VERSION 5.8 ;
BUSBITCHARS "[]" ;
DIVIDERCHAR "/" ;
UNITS
    DATABASE MICRONS 1000 ;
END UNITS

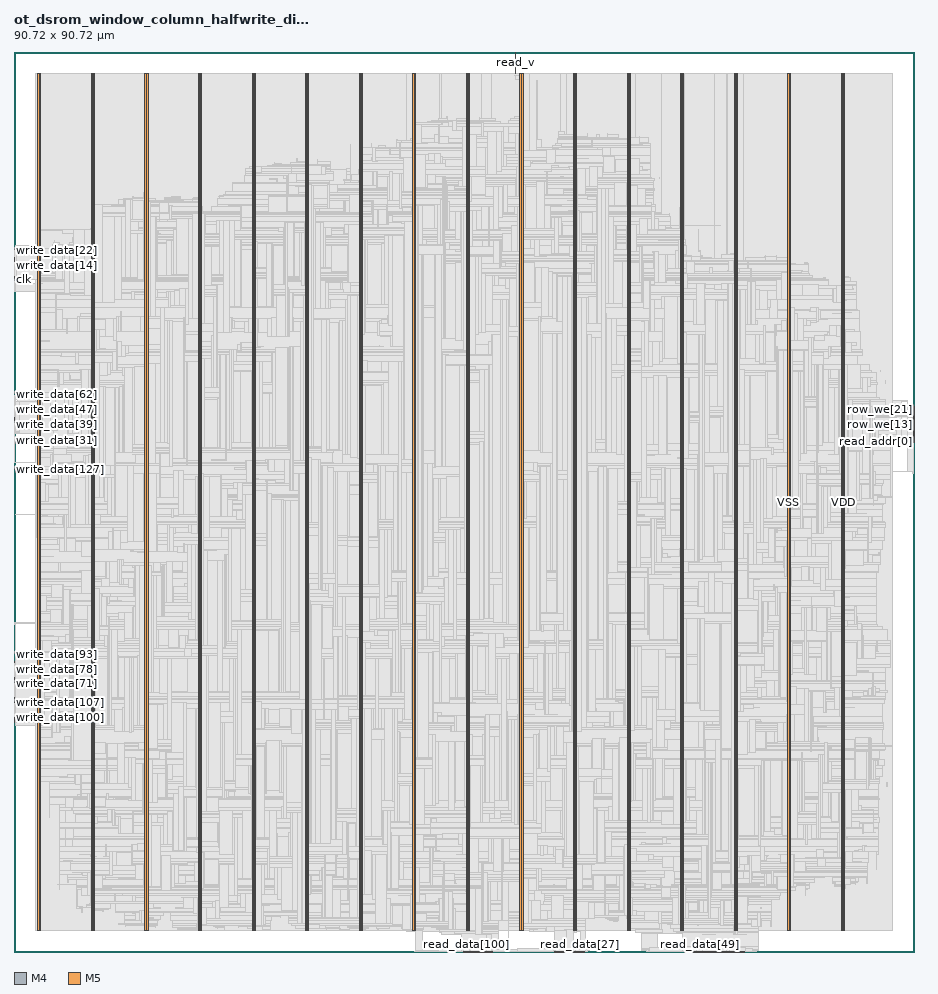
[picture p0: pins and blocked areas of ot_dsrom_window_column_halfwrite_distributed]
MACRO ot_dsrom_window_column_halfwrite_distributed
  FOREIGN ot_dsrom_window_column_halfwrite_distributed 0 0 ;
  CLASS BLOCK ;
  SIZE 90.72 BY 90.72 ;
  PIN clk
    DIRECTION INPUT ;
    USE SIGNAL ;
    PORT
      LAYER M4 ;
        RECT  0 67.728 0.084 67.752 ;
    END
  END clk
  PIN read_addr[0]
    DIRECTION INPUT ;
    USE SIGNAL ;
    PORT
      LAYER M4 ;
        RECT  90.636 51.408 90.72 51.432 ;
    END
  END read_addr[0]
  PIN read_addr[1]
    DIRECTION INPUT ;
    USE SIGNAL ;
    PORT
      LAYER M4 ;
        RECT  90.636 51.504 90.72 51.528 ;
    END
  END read_addr[1]
  PIN read_addr[2]
    DIRECTION INPUT ;
    USE SIGNAL ;
    PORT
      LAYER M4 ;
        RECT  90.636 51.6 90.72 51.624 ;
    END
  END read_addr[2]
  PIN read_addr[3]
    DIRECTION INPUT ;
    USE SIGNAL ;
    PORT
      LAYER M4 ;
        RECT  90.636 51.696 90.72 51.72 ;
    END
  END read_addr[3]
  PIN read_addr[4]
    DIRECTION INPUT ;
    USE SIGNAL ;
    PORT
      LAYER M4 ;
        RECT  90.636 51.792 90.72 51.816 ;
    END
  END read_addr[4]
  PIN read_data[0]
    DIRECTION OUTPUT ;
    USE SIGNAL ;
    PORT
      LAYER M5 ;
        RECT  54.48 0 54.504 0.084 ;
    END
  END read_data[0]
  PIN read_data[100]
    DIRECTION OUTPUT ;
    USE SIGNAL ;
    PORT
      LAYER M5 ;
        RECT  45.648 0 45.672 0.084 ;
    END
  END read_data[100]
  PIN read_data[101]
    DIRECTION OUTPUT ;
    USE SIGNAL ;
    PORT
      LAYER M5 ;
        RECT  45.744 0 45.768 0.084 ;
    END
  END read_data[101]
  PIN read_data[102]
    DIRECTION OUTPUT ;
    USE SIGNAL ;
    PORT
      LAYER M5 ;
        RECT  45.84 0 45.864 0.084 ;
    END
  END read_data[102]
  PIN read_data[103]
    DIRECTION OUTPUT ;
    USE SIGNAL ;
    PORT
      LAYER M5 ;
        RECT  45.936 0 45.96 0.084 ;
    END
  END read_data[103]
  PIN read_data[104]
    DIRECTION OUTPUT ;
    USE SIGNAL ;
    PORT
      LAYER M5 ;
        RECT  46.032 0 46.056 0.084 ;
    END
  END read_data[104]
  PIN read_data[105]
    DIRECTION OUTPUT ;
    USE SIGNAL ;
    PORT
      LAYER M5 ;
        RECT  46.128 0 46.152 0.084 ;
    END
  END read_data[105]
  PIN read_data[106]
    DIRECTION OUTPUT ;
    USE SIGNAL ;
    PORT
      LAYER M5 ;
        RECT  46.224 0 46.248 0.084 ;
    END
  END read_data[106]
  PIN read_data[107]
    DIRECTION OUTPUT ;
    USE SIGNAL ;
    PORT
      LAYER M5 ;
        RECT  46.32 0 46.344 0.084 ;
    END
  END read_data[107]
  PIN read_data[108]
    DIRECTION OUTPUT ;
    USE SIGNAL ;
    PORT
      LAYER M5 ;
        RECT  46.416 0 46.44 0.084 ;
    END
  END read_data[108]
  PIN read_data[109]
    DIRECTION OUTPUT ;
    USE SIGNAL ;
    PORT
      LAYER M5 ;
        RECT  46.512 0 46.536 0.084 ;
    END
  END read_data[109]
  PIN read_data[10]
    DIRECTION OUTPUT ;
    USE SIGNAL ;
    PORT
      LAYER M5 ;
        RECT  55.44 0 55.464 0.084 ;
    END
  END read_data[10]
  PIN read_data[110]
    DIRECTION OUTPUT ;
    USE SIGNAL ;
    PORT
      LAYER M5 ;
        RECT  46.608 0 46.632 0.084 ;
    END
  END read_data[110]
  PIN read_data[111]
    DIRECTION OUTPUT ;
    USE SIGNAL ;
    PORT
      LAYER M5 ;
        RECT  46.704 0 46.728 0.084 ;
    END
  END read_data[111]
  PIN read_data[112]
    DIRECTION OUTPUT ;
    USE SIGNAL ;
    PORT
      LAYER M5 ;
        RECT  46.8 0 46.824 0.084 ;
    END
  END read_data[112]
  PIN read_data[113]
    DIRECTION OUTPUT ;
    USE SIGNAL ;
    PORT
      LAYER M5 ;
        RECT  46.896 0 46.92 0.084 ;
    END
  END read_data[113]
  PIN read_data[114]
    DIRECTION OUTPUT ;
    USE SIGNAL ;
    PORT
      LAYER M5 ;
        RECT  46.992 0 47.016 0.084 ;
    END
  END read_data[114]
  PIN read_data[115]
    DIRECTION OUTPUT ;
    USE SIGNAL ;
    PORT
      LAYER M5 ;
        RECT  47.088 0 47.112 0.084 ;
    END
  END read_data[115]
  PIN read_data[116]
    DIRECTION OUTPUT ;
    USE SIGNAL ;
    PORT
      LAYER M5 ;
        RECT  47.184 0 47.208 0.084 ;
    END
  END read_data[116]
  PIN read_data[117]
    DIRECTION OUTPUT ;
    USE SIGNAL ;
    PORT
      LAYER M5 ;
        RECT  47.28 0 47.304 0.084 ;
    END
  END read_data[117]
  PIN read_data[118]
    DIRECTION OUTPUT ;
    USE SIGNAL ;
    PORT
      LAYER M5 ;
        RECT  47.376 0 47.4 0.084 ;
    END
  END read_data[118]
  PIN read_data[119]
    DIRECTION OUTPUT ;
    USE SIGNAL ;
    PORT
      LAYER M5 ;
        RECT  47.472 0 47.496 0.084 ;
    END
  END read_data[119]
  PIN read_data[11]
    DIRECTION OUTPUT ;
    USE SIGNAL ;
    PORT
      LAYER M5 ;
        RECT  55.536 0 55.56 0.084 ;
    END
  END read_data[11]
  PIN read_data[120]
    DIRECTION OUTPUT ;
    USE SIGNAL ;
    PORT
      LAYER M5 ;
        RECT  47.568 0 47.592 0.084 ;
    END
  END read_data[120]
  PIN read_data[121]
    DIRECTION OUTPUT ;
    USE SIGNAL ;
    PORT
      LAYER M5 ;
        RECT  47.664 0 47.688 0.084 ;
    END
  END read_data[121]
  PIN read_data[122]
    DIRECTION OUTPUT ;
    USE SIGNAL ;
    PORT
      LAYER M5 ;
        RECT  47.76 0 47.784 0.084 ;
    END
  END read_data[122]
  PIN read_data[123]
    DIRECTION OUTPUT ;
    USE SIGNAL ;
    PORT
      LAYER M5 ;
        RECT  47.856 0 47.88 0.084 ;
    END
  END read_data[123]
  PIN read_data[124]
    DIRECTION OUTPUT ;
    USE SIGNAL ;
    PORT
      LAYER M5 ;
        RECT  47.952 0 47.976 0.084 ;
    END
  END read_data[124]
  PIN read_data[125]
    DIRECTION OUTPUT ;
    USE SIGNAL ;
    PORT
      LAYER M5 ;
        RECT  48.048 0 48.072 0.084 ;
    END
  END read_data[125]
  PIN read_data[126]
    DIRECTION OUTPUT ;
    USE SIGNAL ;
    PORT
      LAYER M5 ;
        RECT  48.144 0 48.168 0.084 ;
    END
  END read_data[126]
  PIN read_data[127]
    DIRECTION OUTPUT ;
    USE SIGNAL ;
    PORT
      LAYER M5 ;
        RECT  48.24 0 48.264 0.084 ;
    END
  END read_data[127]
  PIN read_data[12]
    DIRECTION OUTPUT ;
    USE SIGNAL ;
    PORT
      LAYER M5 ;
        RECT  55.632 0 55.656 0.084 ;
    END
  END read_data[12]
  PIN read_data[13]
    DIRECTION OUTPUT ;
    USE SIGNAL ;
    PORT
      LAYER M5 ;
        RECT  55.728 0 55.752 0.084 ;
    END
  END read_data[13]
  PIN read_data[14]
    DIRECTION OUTPUT ;
    USE SIGNAL ;
    PORT
      LAYER M5 ;
        RECT  55.824 0 55.848 0.084 ;
    END
  END read_data[14]
  PIN read_data[15]
    DIRECTION OUTPUT ;
    USE SIGNAL ;
    PORT
      LAYER M5 ;
        RECT  55.92 0 55.944 0.084 ;
    END
  END read_data[15]
  PIN read_data[16]
    DIRECTION OUTPUT ;
    USE SIGNAL ;
    PORT
      LAYER M5 ;
        RECT  56.016 0 56.04 0.084 ;
    END
  END read_data[16]
  PIN read_data[17]
    DIRECTION OUTPUT ;
    USE SIGNAL ;
    PORT
      LAYER M5 ;
        RECT  56.112 0 56.136 0.084 ;
    END
  END read_data[17]
  PIN read_data[18]
    DIRECTION OUTPUT ;
    USE SIGNAL ;
    PORT
      LAYER M5 ;
        RECT  56.208 0 56.232 0.084 ;
    END
  END read_data[18]
  PIN read_data[19]
    DIRECTION OUTPUT ;
    USE SIGNAL ;
    PORT
      LAYER M5 ;
        RECT  56.304 0 56.328 0.084 ;
    END
  END read_data[19]
  PIN read_data[1]
    DIRECTION OUTPUT ;
    USE SIGNAL ;
    PORT
      LAYER M5 ;
        RECT  54.576 0 54.6 0.084 ;
    END
  END read_data[1]
  PIN read_data[20]
    DIRECTION OUTPUT ;
    USE SIGNAL ;
    PORT
      LAYER M5 ;
        RECT  56.4 0 56.424 0.084 ;
    END
  END read_data[20]
  PIN read_data[21]
    DIRECTION OUTPUT ;
    USE SIGNAL ;
    PORT
      LAYER M5 ;
        RECT  56.496 0 56.52 0.084 ;
    END
  END read_data[21]
  PIN read_data[22]
    DIRECTION OUTPUT ;
    USE SIGNAL ;
    PORT
      LAYER M5 ;
        RECT  56.592 0 56.616 0.084 ;
    END
  END read_data[22]
  PIN read_data[23]
    DIRECTION OUTPUT ;
    USE SIGNAL ;
    PORT
      LAYER M5 ;
        RECT  56.688 0 56.712 0.084 ;
    END
  END read_data[23]
  PIN read_data[24]
    DIRECTION OUTPUT ;
    USE SIGNAL ;
    PORT
      LAYER M5 ;
        RECT  56.784 0 56.808 0.084 ;
    END
  END read_data[24]
  PIN read_data[25]
    DIRECTION OUTPUT ;
    USE SIGNAL ;
    PORT
      LAYER M5 ;
        RECT  56.88 0 56.904 0.084 ;
    END
  END read_data[25]
  PIN read_data[26]
    DIRECTION OUTPUT ;
    USE SIGNAL ;
    PORT
      LAYER M5 ;
        RECT  56.976 0 57 0.084 ;
    END
  END read_data[26]
  PIN read_data[27]
    DIRECTION OUTPUT ;
    USE SIGNAL ;
    PORT
      LAYER M5 ;
        RECT  57.072 0 57.096 0.084 ;
    END
  END read_data[27]
  PIN read_data[28]
    DIRECTION OUTPUT ;
    USE SIGNAL ;
    PORT
      LAYER M5 ;
        RECT  57.168 0 57.192 0.084 ;
    END
  END read_data[28]
  PIN read_data[29]
    DIRECTION OUTPUT ;
    USE SIGNAL ;
    PORT
      LAYER M5 ;
        RECT  57.264 0 57.288 0.084 ;
    END
  END read_data[29]
  PIN read_data[2]
    DIRECTION OUTPUT ;
    USE SIGNAL ;
    PORT
      LAYER M5 ;
        RECT  54.672 0 54.696 0.084 ;
    END
  END read_data[2]
  PIN read_data[30]
    DIRECTION OUTPUT ;
    USE SIGNAL ;
    PORT
      LAYER M5 ;
        RECT  57.36 0 57.384 0.084 ;
    END
  END read_data[30]
  PIN read_data[31]
    DIRECTION OUTPUT ;
    USE SIGNAL ;
    PORT
      LAYER M5 ;
        RECT  57.456 0 57.48 0.084 ;
    END
  END read_data[31]
  PIN read_data[32]
    DIRECTION OUTPUT ;
    USE SIGNAL ;
    PORT
      LAYER M5 ;
        RECT  67.536 0 67.56 0.084 ;
    END
  END read_data[32]
  PIN read_data[33]
    DIRECTION OUTPUT ;
    USE SIGNAL ;
    PORT
      LAYER M5 ;
        RECT  67.632 0 67.656 0.084 ;
    END
  END read_data[33]
  PIN read_data[34]
    DIRECTION OUTPUT ;
    USE SIGNAL ;
    PORT
      LAYER M5 ;
        RECT  67.728 0 67.752 0.084 ;
    END
  END read_data[34]
  PIN read_data[35]
    DIRECTION OUTPUT ;
    USE SIGNAL ;
    PORT
      LAYER M5 ;
        RECT  67.824 0 67.848 0.084 ;
    END
  END read_data[35]
  PIN read_data[36]
    DIRECTION OUTPUT ;
    USE SIGNAL ;
    PORT
      LAYER M5 ;
        RECT  67.92 0 67.944 0.084 ;
    END
  END read_data[36]
  PIN read_data[37]
    DIRECTION OUTPUT ;
    USE SIGNAL ;
    PORT
      LAYER M5 ;
        RECT  68.016 0 68.04 0.084 ;
    END
  END read_data[37]
  PIN read_data[38]
    DIRECTION OUTPUT ;
    USE SIGNAL ;
    PORT
      LAYER M5 ;
        RECT  68.112 0 68.136 0.084 ;
    END
  END read_data[38]
  PIN read_data[39]
    DIRECTION OUTPUT ;
    USE SIGNAL ;
    PORT
      LAYER M5 ;
        RECT  68.208 0 68.232 0.084 ;
    END
  END read_data[39]
  PIN read_data[3]
    DIRECTION OUTPUT ;
    USE SIGNAL ;
    PORT
      LAYER M5 ;
        RECT  54.768 0 54.792 0.084 ;
    END
  END read_data[3]
  PIN read_data[40]
    DIRECTION OUTPUT ;
    USE SIGNAL ;
    PORT
      LAYER M5 ;
        RECT  68.304 0 68.328 0.084 ;
    END
  END read_data[40]
  PIN read_data[41]
    DIRECTION OUTPUT ;
    USE SIGNAL ;
    PORT
      LAYER M5 ;
        RECT  68.4 0 68.424 0.084 ;
    END
  END read_data[41]
  PIN read_data[42]
    DIRECTION OUTPUT ;
    USE SIGNAL ;
    PORT
      LAYER M5 ;
        RECT  68.496 0 68.52 0.084 ;
    END
  END read_data[42]
  PIN read_data[43]
    DIRECTION OUTPUT ;
    USE SIGNAL ;
    PORT
      LAYER M5 ;
        RECT  68.592 0 68.616 0.084 ;
    END
  END read_data[43]
  PIN read_data[44]
    DIRECTION OUTPUT ;
    USE SIGNAL ;
    PORT
      LAYER M5 ;
        RECT  68.688 0 68.712 0.084 ;
    END
  END read_data[44]
  PIN read_data[45]
    DIRECTION OUTPUT ;
    USE SIGNAL ;
    PORT
      LAYER M5 ;
        RECT  68.784 0 68.808 0.084 ;
    END
  END read_data[45]
  PIN read_data[46]
    DIRECTION OUTPUT ;
    USE SIGNAL ;
    PORT
      LAYER M5 ;
        RECT  68.88 0 68.904 0.084 ;
    END
  END read_data[46]
  PIN read_data[47]
    DIRECTION OUTPUT ;
    USE SIGNAL ;
    PORT
      LAYER M5 ;
        RECT  68.976 0 69 0.084 ;
    END
  END read_data[47]
  PIN read_data[48]
    DIRECTION OUTPUT ;
    USE SIGNAL ;
    PORT
      LAYER M5 ;
        RECT  69.072 0 69.096 0.084 ;
    END
  END read_data[48]
  PIN read_data[49]
    DIRECTION OUTPUT ;
    USE SIGNAL ;
    PORT
      LAYER M5 ;
        RECT  69.168 0 69.192 0.084 ;
    END
  END read_data[49]
  PIN read_data[4]
    DIRECTION OUTPUT ;
    USE SIGNAL ;
    PORT
      LAYER M5 ;
        RECT  54.864 0 54.888 0.084 ;
    END
  END read_data[4]
  PIN read_data[50]
    DIRECTION OUTPUT ;
    USE SIGNAL ;
    PORT
      LAYER M5 ;
        RECT  69.264 0 69.288 0.084 ;
    END
  END read_data[50]
  PIN read_data[51]
    DIRECTION OUTPUT ;
    USE SIGNAL ;
    PORT
      LAYER M5 ;
        RECT  69.36 0 69.384 0.084 ;
    END
  END read_data[51]
  PIN read_data[52]
    DIRECTION OUTPUT ;
    USE SIGNAL ;
    PORT
      LAYER M5 ;
        RECT  69.456 0 69.48 0.084 ;
    END
  END read_data[52]
  PIN read_data[53]
    DIRECTION OUTPUT ;
    USE SIGNAL ;
    PORT
      LAYER M5 ;
        RECT  69.552 0 69.576 0.084 ;
    END
  END read_data[53]
  PIN read_data[54]
    DIRECTION OUTPUT ;
    USE SIGNAL ;
    PORT
      LAYER M5 ;
        RECT  69.648 0 69.672 0.084 ;
    END
  END read_data[54]
  PIN read_data[55]
    DIRECTION OUTPUT ;
    USE SIGNAL ;
    PORT
      LAYER M5 ;
        RECT  69.744 0 69.768 0.084 ;
    END
  END read_data[55]
  PIN read_data[56]
    DIRECTION OUTPUT ;
    USE SIGNAL ;
    PORT
      LAYER M5 ;
        RECT  69.84 0 69.864 0.084 ;
    END
  END read_data[56]
  PIN read_data[57]
    DIRECTION OUTPUT ;
    USE SIGNAL ;
    PORT
      LAYER M5 ;
        RECT  69.936 0 69.96 0.084 ;
    END
  END read_data[57]
  PIN read_data[58]
    DIRECTION OUTPUT ;
    USE SIGNAL ;
    PORT
      LAYER M5 ;
        RECT  70.032 0 70.056 0.084 ;
    END
  END read_data[58]
  PIN read_data[59]
    DIRECTION OUTPUT ;
    USE SIGNAL ;
    PORT
      LAYER M5 ;
        RECT  70.128 0 70.152 0.084 ;
    END
  END read_data[59]
  PIN read_data[5]
    DIRECTION OUTPUT ;
    USE SIGNAL ;
    PORT
      LAYER M5 ;
        RECT  54.96 0 54.984 0.084 ;
    END
  END read_data[5]
  PIN read_data[60]
    DIRECTION OUTPUT ;
    USE SIGNAL ;
    PORT
      LAYER M5 ;
        RECT  70.224 0 70.248 0.084 ;
    END
  END read_data[60]
  PIN read_data[61]
    DIRECTION OUTPUT ;
    USE SIGNAL ;
    PORT
      LAYER M5 ;
        RECT  70.32 0 70.344 0.084 ;
    END
  END read_data[61]
  PIN read_data[62]
    DIRECTION OUTPUT ;
    USE SIGNAL ;
    PORT
      LAYER M5 ;
        RECT  70.416 0 70.44 0.084 ;
    END
  END read_data[62]
  PIN read_data[63]
    DIRECTION OUTPUT ;
    USE SIGNAL ;
    PORT
      LAYER M5 ;
        RECT  70.512 0 70.536 0.084 ;
    END
  END read_data[63]
  PIN read_data[64]
    DIRECTION OUTPUT ;
    USE SIGNAL ;
    PORT
      LAYER M5 ;
        RECT  70.608 0 70.632 0.084 ;
    END
  END read_data[64]
  PIN read_data[65]
    DIRECTION OUTPUT ;
    USE SIGNAL ;
    PORT
      LAYER M5 ;
        RECT  70.704 0 70.728 0.084 ;
    END
  END read_data[65]
  PIN read_data[66]
    DIRECTION OUTPUT ;
    USE SIGNAL ;
    PORT
      LAYER M5 ;
        RECT  70.8 0 70.824 0.084 ;
    END
  END read_data[66]
  PIN read_data[67]
    DIRECTION OUTPUT ;
    USE SIGNAL ;
    PORT
      LAYER M5 ;
        RECT  70.896 0 70.92 0.084 ;
    END
  END read_data[67]
  PIN read_data[68]
    DIRECTION OUTPUT ;
    USE SIGNAL ;
    PORT
      LAYER M5 ;
        RECT  70.992 0 71.016 0.084 ;
    END
  END read_data[68]
  PIN read_data[69]
    DIRECTION OUTPUT ;
    USE SIGNAL ;
    PORT
      LAYER M5 ;
        RECT  71.088 0 71.112 0.084 ;
    END
  END read_data[69]
  PIN read_data[6]
    DIRECTION OUTPUT ;
    USE SIGNAL ;
    PORT
      LAYER M5 ;
        RECT  55.056 0 55.08 0.084 ;
    END
  END read_data[6]
  PIN read_data[70]
    DIRECTION OUTPUT ;
    USE SIGNAL ;
    PORT
      LAYER M5 ;
        RECT  71.184 0 71.208 0.084 ;
    END
  END read_data[70]
  PIN read_data[71]
    DIRECTION OUTPUT ;
    USE SIGNAL ;
    PORT
      LAYER M5 ;
        RECT  71.28 0 71.304 0.084 ;
    END
  END read_data[71]
  PIN read_data[72]
    DIRECTION OUTPUT ;
    USE SIGNAL ;
    PORT
      LAYER M5 ;
        RECT  71.376 0 71.4 0.084 ;
    END
  END read_data[72]
  PIN read_data[73]
    DIRECTION OUTPUT ;
    USE SIGNAL ;
    PORT
      LAYER M5 ;
        RECT  71.472 0 71.496 0.084 ;
    END
  END read_data[73]
  PIN read_data[74]
    DIRECTION OUTPUT ;
    USE SIGNAL ;
    PORT
      LAYER M5 ;
        RECT  71.568 0 71.592 0.084 ;
    END
  END read_data[74]
  PIN read_data[75]
    DIRECTION OUTPUT ;
    USE SIGNAL ;
    PORT
      LAYER M5 ;
        RECT  71.664 0 71.688 0.084 ;
    END
  END read_data[75]
  PIN read_data[76]
    DIRECTION OUTPUT ;
    USE SIGNAL ;
    PORT
      LAYER M5 ;
        RECT  71.76 0 71.784 0.084 ;
    END
  END read_data[76]
  PIN read_data[77]
    DIRECTION OUTPUT ;
    USE SIGNAL ;
    PORT
      LAYER M5 ;
        RECT  71.856 0 71.88 0.084 ;
    END
  END read_data[77]
  PIN read_data[78]
    DIRECTION OUTPUT ;
    USE SIGNAL ;
    PORT
      LAYER M5 ;
        RECT  71.952 0 71.976 0.084 ;
    END
  END read_data[78]
  PIN read_data[79]
    DIRECTION OUTPUT ;
    USE SIGNAL ;
    PORT
      LAYER M5 ;
        RECT  72.048 0 72.072 0.084 ;
    END
  END read_data[79]
  PIN read_data[7]
    DIRECTION OUTPUT ;
    USE SIGNAL ;
    PORT
      LAYER M5 ;
        RECT  55.152 0 55.176 0.084 ;
    END
  END read_data[7]
  PIN read_data[80]
    DIRECTION OUTPUT ;
    USE SIGNAL ;
    PORT
      LAYER M5 ;
        RECT  72.144 0 72.168 0.084 ;
    END
  END read_data[80]
  PIN read_data[81]
    DIRECTION OUTPUT ;
    USE SIGNAL ;
    PORT
      LAYER M5 ;
        RECT  72.24 0 72.264 0.084 ;
    END
  END read_data[81]
  PIN read_data[82]
    DIRECTION OUTPUT ;
    USE SIGNAL ;
    PORT
      LAYER M5 ;
        RECT  72.336 0 72.36 0.084 ;
    END
  END read_data[82]
  PIN read_data[83]
    DIRECTION OUTPUT ;
    USE SIGNAL ;
    PORT
      LAYER M5 ;
        RECT  72.432 0 72.456 0.084 ;
    END
  END read_data[83]
  PIN read_data[84]
    DIRECTION OUTPUT ;
    USE SIGNAL ;
    PORT
      LAYER M5 ;
        RECT  72.528 0 72.552 0.084 ;
    END
  END read_data[84]
  PIN read_data[85]
    DIRECTION OUTPUT ;
    USE SIGNAL ;
    PORT
      LAYER M5 ;
        RECT  72.624 0 72.648 0.084 ;
    END
  END read_data[85]
  PIN read_data[86]
    DIRECTION OUTPUT ;
    USE SIGNAL ;
    PORT
      LAYER M5 ;
        RECT  72.72 0 72.744 0.084 ;
    END
  END read_data[86]
  PIN read_data[87]
    DIRECTION OUTPUT ;
    USE SIGNAL ;
    PORT
      LAYER M5 ;
        RECT  72.816 0 72.84 0.084 ;
    END
  END read_data[87]
  PIN read_data[88]
    DIRECTION OUTPUT ;
    USE SIGNAL ;
    PORT
      LAYER M5 ;
        RECT  72.912 0 72.936 0.084 ;
    END
  END read_data[88]
  PIN read_data[89]
    DIRECTION OUTPUT ;
    USE SIGNAL ;
    PORT
      LAYER M5 ;
        RECT  73.008 0 73.032 0.084 ;
    END
  END read_data[89]
  PIN read_data[8]
    DIRECTION OUTPUT ;
    USE SIGNAL ;
    PORT
      LAYER M5 ;
        RECT  55.248 0 55.272 0.084 ;
    END
  END read_data[8]
  PIN read_data[90]
    DIRECTION OUTPUT ;
    USE SIGNAL ;
    PORT
      LAYER M5 ;
        RECT  73.104 0 73.128 0.084 ;
    END
  END read_data[90]
  PIN read_data[91]
    DIRECTION OUTPUT ;
    USE SIGNAL ;
    PORT
      LAYER M5 ;
        RECT  73.2 0 73.224 0.084 ;
    END
  END read_data[91]
  PIN read_data[92]
    DIRECTION OUTPUT ;
    USE SIGNAL ;
    PORT
      LAYER M5 ;
        RECT  73.296 0 73.32 0.084 ;
    END
  END read_data[92]
  PIN read_data[93]
    DIRECTION OUTPUT ;
    USE SIGNAL ;
    PORT
      LAYER M5 ;
        RECT  73.392 0 73.416 0.084 ;
    END
  END read_data[93]
  PIN read_data[94]
    DIRECTION OUTPUT ;
    USE SIGNAL ;
    PORT
      LAYER M5 ;
        RECT  73.488 0 73.512 0.084 ;
    END
  END read_data[94]
  PIN read_data[95]
    DIRECTION OUTPUT ;
    USE SIGNAL ;
    PORT
      LAYER M5 ;
        RECT  73.584 0 73.608 0.084 ;
    END
  END read_data[95]
  PIN read_data[96]
    DIRECTION OUTPUT ;
    USE SIGNAL ;
    PORT
      LAYER M5 ;
        RECT  45.264 0 45.288 0.084 ;
    END
  END read_data[96]
  PIN read_data[97]
    DIRECTION OUTPUT ;
    USE SIGNAL ;
    PORT
      LAYER M5 ;
        RECT  45.36 0 45.384 0.084 ;
    END
  END read_data[97]
  PIN read_data[98]
    DIRECTION OUTPUT ;
    USE SIGNAL ;
    PORT
      LAYER M5 ;
        RECT  45.456 0 45.48 0.084 ;
    END
  END read_data[98]
  PIN read_data[99]
    DIRECTION OUTPUT ;
    USE SIGNAL ;
    PORT
      LAYER M5 ;
        RECT  45.552 0 45.576 0.084 ;
    END
  END read_data[99]
  PIN read_data[9]
    DIRECTION OUTPUT ;
    USE SIGNAL ;
    PORT
      LAYER M5 ;
        RECT  55.344 0 55.368 0.084 ;
    END
  END read_data[9]
  PIN read_v
    DIRECTION INPUT ;
    USE SIGNAL ;
    PORT
      LAYER M5 ;
        RECT  50.544 90.636 50.568 90.72 ;
    END
    PORT
      LAYER M5 ;
        RECT  50.544 88.583 50.568 90.704 ;
    END
  END read_v
  PIN row_we[0]
    DIRECTION INPUT ;
    USE SIGNAL ;
    PORT
      LAYER M4 ;
        RECT  90.636 51.888 90.72 51.912 ;
    END
  END row_we[0]
  PIN row_we[10]
    DIRECTION INPUT ;
    USE SIGNAL ;
    PORT
      LAYER M4 ;
        RECT  90.636 52.848 90.72 52.872 ;
    END
  END row_we[10]
  PIN row_we[11]
    DIRECTION INPUT ;
    USE SIGNAL ;
    PORT
      LAYER M4 ;
        RECT  90.636 52.944 90.72 52.968 ;
    END
  END row_we[11]
  PIN row_we[12]
    DIRECTION INPUT ;
    USE SIGNAL ;
    PORT
      LAYER M4 ;
        RECT  90.636 53.04 90.72 53.064 ;
    END
  END row_we[12]
  PIN row_we[13]
    DIRECTION INPUT ;
    USE SIGNAL ;
    PORT
      LAYER M4 ;
        RECT  90.636 53.136 90.72 53.16 ;
    END
  END row_we[13]
  PIN row_we[14]
    DIRECTION INPUT ;
    USE SIGNAL ;
    PORT
      LAYER M4 ;
        RECT  90.636 53.232 90.72 53.256 ;
    END
  END row_we[14]
  PIN row_we[15]
    DIRECTION INPUT ;
    USE SIGNAL ;
    PORT
      LAYER M4 ;
        RECT  90.636 53.328 90.72 53.352 ;
    END
  END row_we[15]
  PIN row_we[16]
    DIRECTION INPUT ;
    USE SIGNAL ;
    PORT
      LAYER M4 ;
        RECT  90.636 53.424 90.72 53.448 ;
    END
  END row_we[16]
  PIN row_we[17]
    DIRECTION INPUT ;
    USE SIGNAL ;
    PORT
      LAYER M4 ;
        RECT  90.636 53.52 90.72 53.544 ;
    END
  END row_we[17]
  PIN row_we[18]
    DIRECTION INPUT ;
    USE SIGNAL ;
    PORT
      LAYER M4 ;
        RECT  90.636 53.616 90.72 53.64 ;
    END
  END row_we[18]
  PIN row_we[19]
    DIRECTION INPUT ;
    USE SIGNAL ;
    PORT
      LAYER M4 ;
        RECT  90.636 53.712 90.72 53.736 ;
    END
  END row_we[19]
  PIN row_we[1]
    DIRECTION INPUT ;
    USE SIGNAL ;
    PORT
      LAYER M4 ;
        RECT  90.636 51.984 90.72 52.008 ;
    END
  END row_we[1]
  PIN row_we[20]
    DIRECTION INPUT ;
    USE SIGNAL ;
    PORT
      LAYER M4 ;
        RECT  90.636 53.808 90.72 53.832 ;
    END
  END row_we[20]
  PIN row_we[21]
    DIRECTION INPUT ;
    USE SIGNAL ;
    PORT
      LAYER M4 ;
        RECT  90.636 53.904 90.72 53.928 ;
    END
  END row_we[21]
  PIN row_we[22]
    DIRECTION INPUT ;
    USE SIGNAL ;
    PORT
      LAYER M4 ;
        RECT  90.636 54 90.72 54.024 ;
    END
  END row_we[22]
  PIN row_we[23]
    DIRECTION INPUT ;
    USE SIGNAL ;
    PORT
      LAYER M4 ;
        RECT  90.636 54.096 90.72 54.12 ;
    END
  END row_we[23]
  PIN row_we[24]
    DIRECTION INPUT ;
    USE SIGNAL ;
    PORT
      LAYER M4 ;
        RECT  90.636 54.192 90.72 54.216 ;
    END
  END row_we[24]
  PIN row_we[25]
    DIRECTION INPUT ;
    USE SIGNAL ;
    PORT
      LAYER M4 ;
        RECT  90.636 54.288 90.72 54.312 ;
    END
  END row_we[25]
  PIN row_we[26]
    DIRECTION INPUT ;
    USE SIGNAL ;
    PORT
      LAYER M4 ;
        RECT  90.636 54.384 90.72 54.408 ;
    END
  END row_we[26]
  PIN row_we[27]
    DIRECTION INPUT ;
    USE SIGNAL ;
    PORT
      LAYER M4 ;
        RECT  90.636 54.48 90.72 54.504 ;
    END
  END row_we[27]
  PIN row_we[28]
    DIRECTION INPUT ;
    USE SIGNAL ;
    PORT
      LAYER M4 ;
        RECT  90.636 54.576 90.72 54.6 ;
    END
  END row_we[28]
  PIN row_we[29]
    DIRECTION INPUT ;
    USE SIGNAL ;
    PORT
      LAYER M4 ;
        RECT  90.636 54.672 90.72 54.696 ;
    END
  END row_we[29]
  PIN row_we[2]
    DIRECTION INPUT ;
    USE SIGNAL ;
    PORT
      LAYER M4 ;
        RECT  90.636 52.08 90.72 52.104 ;
    END
  END row_we[2]
  PIN row_we[30]
    DIRECTION INPUT ;
    USE SIGNAL ;
    PORT
      LAYER M4 ;
        RECT  90.636 54.768 90.72 54.792 ;
    END
  END row_we[30]
  PIN row_we[31]
    DIRECTION INPUT ;
    USE SIGNAL ;
    PORT
      LAYER M4 ;
        RECT  90.636 54.864 90.72 54.888 ;
    END
  END row_we[31]
  PIN row_we[3]
    DIRECTION INPUT ;
    USE SIGNAL ;
    PORT
      LAYER M4 ;
        RECT  90.636 52.176 90.72 52.2 ;
    END
  END row_we[3]
  PIN row_we[4]
    DIRECTION INPUT ;
    USE SIGNAL ;
    PORT
      LAYER M4 ;
        RECT  90.636 52.272 90.72 52.296 ;
    END
  END row_we[4]
  PIN row_we[5]
    DIRECTION INPUT ;
    USE SIGNAL ;
    PORT
      LAYER M4 ;
        RECT  90.636 52.368 90.72 52.392 ;
    END
  END row_we[5]
  PIN row_we[6]
    DIRECTION INPUT ;
    USE SIGNAL ;
    PORT
      LAYER M4 ;
        RECT  90.636 52.464 90.72 52.488 ;
    END
  END row_we[6]
  PIN row_we[7]
    DIRECTION INPUT ;
    USE SIGNAL ;
    PORT
      LAYER M4 ;
        RECT  90.636 52.56 90.72 52.584 ;
    END
  END row_we[7]
  PIN row_we[8]
    DIRECTION INPUT ;
    USE SIGNAL ;
    PORT
      LAYER M4 ;
        RECT  90.636 52.656 90.72 52.68 ;
    END
  END row_we[8]
  PIN row_we[9]
    DIRECTION INPUT ;
    USE SIGNAL ;
    PORT
      LAYER M4 ;
        RECT  90.636 52.752 90.72 52.776 ;
    END
  END row_we[9]
  PIN rst_n
    DIRECTION INPUT ;
    USE SIGNAL ;
    PORT
      LAYER M4 ;
        RECT  90.636 54.96 90.72 54.984 ;
    END
  END rst_n
  PIN write_data[0]
    DIRECTION INPUT ;
    USE SIGNAL ;
    PORT
      LAYER M4 ;
        RECT  0 67.824 0.084 67.848 ;
    END
  END write_data[0]
  PIN write_data[100]
    DIRECTION INPUT ;
    USE SIGNAL ;
    PORT
      LAYER M4 ;
        RECT  0 23.664 0.084 23.688 ;
    END
  END write_data[100]
  PIN write_data[101]
    DIRECTION INPUT ;
    USE SIGNAL ;
    PORT
      LAYER M4 ;
        RECT  0 23.76 0.084 23.784 ;
    END
  END write_data[101]
  PIN write_data[102]
    DIRECTION INPUT ;
    USE SIGNAL ;
    PORT
      LAYER M4 ;
        RECT  0 23.856 0.084 23.88 ;
    END
  END write_data[102]
  PIN write_data[103]
    DIRECTION INPUT ;
    USE SIGNAL ;
    PORT
      LAYER M4 ;
        RECT  0 23.952 0.084 23.976 ;
    END
  END write_data[103]
  PIN write_data[104]
    DIRECTION INPUT ;
    USE SIGNAL ;
    PORT
      LAYER M4 ;
        RECT  0 24.048 0.084 24.072 ;
    END
  END write_data[104]
  PIN write_data[105]
    DIRECTION INPUT ;
    USE SIGNAL ;
    PORT
      LAYER M4 ;
        RECT  0 24.144 0.084 24.168 ;
    END
  END write_data[105]
  PIN write_data[106]
    DIRECTION INPUT ;
    USE SIGNAL ;
    PORT
      LAYER M4 ;
        RECT  0 24.24 0.084 24.264 ;
    END
  END write_data[106]
  PIN write_data[107]
    DIRECTION INPUT ;
    USE SIGNAL ;
    PORT
      LAYER M4 ;
        RECT  0 24.336 0.084 24.36 ;
    END
  END write_data[107]
  PIN write_data[108]
    DIRECTION INPUT ;
    USE SIGNAL ;
    PORT
      LAYER M4 ;
        RECT  0 24.432 0.084 24.456 ;
    END
  END write_data[108]
  PIN write_data[109]
    DIRECTION INPUT ;
    USE SIGNAL ;
    PORT
      LAYER M4 ;
        RECT  0 24.528 0.084 24.552 ;
    END
  END write_data[109]
  PIN write_data[10]
    DIRECTION INPUT ;
    USE SIGNAL ;
    PORT
      LAYER M4 ;
        RECT  0 68.784 0.084 68.808 ;
    END
  END write_data[10]
  PIN write_data[110]
    DIRECTION INPUT ;
    USE SIGNAL ;
    PORT
      LAYER M4 ;
        RECT  0 24.624 0.084 24.648 ;
    END
  END write_data[110]
  PIN write_data[111]
    DIRECTION INPUT ;
    USE SIGNAL ;
    PORT
      LAYER M4 ;
        RECT  0 24.72 0.084 24.744 ;
    END
  END write_data[111]
  PIN write_data[112]
    DIRECTION INPUT ;
    USE SIGNAL ;
    PORT
      LAYER M4 ;
        RECT  0 24.816 0.084 24.84 ;
    END
  END write_data[112]
  PIN write_data[113]
    DIRECTION INPUT ;
    USE SIGNAL ;
    PORT
      LAYER M4 ;
        RECT  0 24.912 0.084 24.936 ;
    END
  END write_data[113]
  PIN write_data[114]
    DIRECTION INPUT ;
    USE SIGNAL ;
    PORT
      LAYER M4 ;
        RECT  0 25.008 0.084 25.032 ;
    END
  END write_data[114]
  PIN write_data[115]
    DIRECTION INPUT ;
    USE SIGNAL ;
    PORT
      LAYER M4 ;
        RECT  0 25.104 0.084 25.128 ;
    END
  END write_data[115]
  PIN write_data[116]
    DIRECTION INPUT ;
    USE SIGNAL ;
    PORT
      LAYER M4 ;
        RECT  0 25.2 0.084 25.224 ;
    END
  END write_data[116]
  PIN write_data[117]
    DIRECTION INPUT ;
    USE SIGNAL ;
    PORT
      LAYER M4 ;
        RECT  0 25.296 0.084 25.32 ;
    END
  END write_data[117]
  PIN write_data[118]
    DIRECTION INPUT ;
    USE SIGNAL ;
    PORT
      LAYER M4 ;
        RECT  0 25.392 0.084 25.416 ;
    END
  END write_data[118]
  PIN write_data[119]
    DIRECTION INPUT ;
    USE SIGNAL ;
    PORT
      LAYER M4 ;
        RECT  0 25.488 0.084 25.512 ;
    END
  END write_data[119]
  PIN write_data[11]
    DIRECTION INPUT ;
    USE SIGNAL ;
    PORT
      LAYER M4 ;
        RECT  0 68.88 0.084 68.904 ;
    END
  END write_data[11]
  PIN write_data[120]
    DIRECTION INPUT ;
    USE SIGNAL ;
    PORT
      LAYER M4 ;
        RECT  0 25.584 0.084 25.608 ;
    END
  END write_data[120]
  PIN write_data[121]
    DIRECTION INPUT ;
    USE SIGNAL ;
    PORT
      LAYER M4 ;
        RECT  0 25.68 0.084 25.704 ;
    END
  END write_data[121]
  PIN write_data[122]
    DIRECTION INPUT ;
    USE SIGNAL ;
    PORT
      LAYER M4 ;
        RECT  0 25.776 0.084 25.8 ;
    END
  END write_data[122]
  PIN write_data[123]
    DIRECTION INPUT ;
    USE SIGNAL ;
    PORT
      LAYER M4 ;
        RECT  0 25.872 0.084 25.896 ;
    END
  END write_data[123]
  PIN write_data[124]
    DIRECTION INPUT ;
    USE SIGNAL ;
    PORT
      LAYER M4 ;
        RECT  0 25.968 0.084 25.992 ;
    END
  END write_data[124]
  PIN write_data[125]
    DIRECTION INPUT ;
    USE SIGNAL ;
    PORT
      LAYER M4 ;
        RECT  0 26.064 0.084 26.088 ;
    END
  END write_data[125]
  PIN write_data[126]
    DIRECTION INPUT ;
    USE SIGNAL ;
    PORT
      LAYER M4 ;
        RECT  0 26.16 0.084 26.184 ;
    END
  END write_data[126]
  PIN write_data[127]
    DIRECTION INPUT ;
    USE SIGNAL ;
    PORT
      LAYER M4 ;
        RECT  0 48.624 0.084 48.648 ;
    END
    PORT
      LAYER M4 ;
        RECT  0.06 48.624 2.408 48.648 ;
    END
  END write_data[127]
  PIN write_data[12]
    DIRECTION INPUT ;
    USE SIGNAL ;
    PORT
      LAYER M4 ;
        RECT  0 68.976 0.084 69 ;
    END
  END write_data[12]
  PIN write_data[13]
    DIRECTION INPUT ;
    USE SIGNAL ;
    PORT
      LAYER M4 ;
        RECT  0 69.072 0.084 69.096 ;
    END
  END write_data[13]
  PIN write_data[14]
    DIRECTION INPUT ;
    USE SIGNAL ;
    PORT
      LAYER M4 ;
        RECT  0 69.168 0.084 69.192 ;
    END
  END write_data[14]
  PIN write_data[15]
    DIRECTION INPUT ;
    USE SIGNAL ;
    PORT
      LAYER M4 ;
        RECT  0 69.264 0.084 69.288 ;
    END
  END write_data[15]
  PIN write_data[16]
    DIRECTION INPUT ;
    USE SIGNAL ;
    PORT
      LAYER M4 ;
        RECT  0 69.36 0.084 69.384 ;
    END
  END write_data[16]
  PIN write_data[17]
    DIRECTION INPUT ;
    USE SIGNAL ;
    PORT
      LAYER M4 ;
        RECT  0 69.456 0.084 69.48 ;
    END
  END write_data[17]
  PIN write_data[18]
    DIRECTION INPUT ;
    USE SIGNAL ;
    PORT
      LAYER M4 ;
        RECT  0 69.552 0.084 69.576 ;
    END
  END write_data[18]
  PIN write_data[19]
    DIRECTION INPUT ;
    USE SIGNAL ;
    PORT
      LAYER M4 ;
        RECT  0 69.648 0.084 69.672 ;
    END
  END write_data[19]
  PIN write_data[1]
    DIRECTION INPUT ;
    USE SIGNAL ;
    PORT
      LAYER M4 ;
        RECT  0 67.92 0.084 67.944 ;
    END
  END write_data[1]
  PIN write_data[20]
    DIRECTION INPUT ;
    USE SIGNAL ;
    PORT
      LAYER M4 ;
        RECT  0 69.744 0.084 69.768 ;
    END
  END write_data[20]
  PIN write_data[21]
    DIRECTION INPUT ;
    USE SIGNAL ;
    PORT
      LAYER M4 ;
        RECT  0 69.84 0.084 69.864 ;
    END
  END write_data[21]
  PIN write_data[22]
    DIRECTION INPUT ;
    USE SIGNAL ;
    PORT
      LAYER M4 ;
        RECT  0 69.936 0.084 69.96 ;
    END
  END write_data[22]
  PIN write_data[23]
    DIRECTION INPUT ;
    USE SIGNAL ;
    PORT
      LAYER M4 ;
        RECT  0 70.032 0.084 70.056 ;
    END
  END write_data[23]
  PIN write_data[24]
    DIRECTION INPUT ;
    USE SIGNAL ;
    PORT
      LAYER M4 ;
        RECT  0 70.128 0.084 70.152 ;
    END
  END write_data[24]
  PIN write_data[25]
    DIRECTION INPUT ;
    USE SIGNAL ;
    PORT
      LAYER M4 ;
        RECT  0 70.224 0.084 70.248 ;
    END
  END write_data[25]
  PIN write_data[26]
    DIRECTION INPUT ;
    USE SIGNAL ;
    PORT
      LAYER M4 ;
        RECT  0 70.32 0.084 70.344 ;
    END
  END write_data[26]
  PIN write_data[27]
    DIRECTION INPUT ;
    USE SIGNAL ;
    PORT
      LAYER M4 ;
        RECT  0 70.416 0.084 70.44 ;
    END
  END write_data[27]
  PIN write_data[28]
    DIRECTION INPUT ;
    USE SIGNAL ;
    PORT
      LAYER M4 ;
        RECT  0 70.512 0.084 70.536 ;
    END
  END write_data[28]
  PIN write_data[29]
    DIRECTION INPUT ;
    USE SIGNAL ;
    PORT
      LAYER M4 ;
        RECT  0 70.608 0.084 70.632 ;
    END
  END write_data[29]
  PIN write_data[2]
    DIRECTION INPUT ;
    USE SIGNAL ;
    PORT
      LAYER M4 ;
        RECT  0 68.016 0.084 68.04 ;
    END
  END write_data[2]
  PIN write_data[30]
    DIRECTION INPUT ;
    USE SIGNAL ;
    PORT
      LAYER M4 ;
        RECT  0 70.704 0.084 70.728 ;
    END
  END write_data[30]
  PIN write_data[31]
    DIRECTION INPUT ;
    USE SIGNAL ;
    PORT
      LAYER M4 ;
        RECT  0 52.368 0.084 52.392 ;
    END
  END write_data[31]
  PIN write_data[32]
    DIRECTION INPUT ;
    USE SIGNAL ;
    PORT
      LAYER M4 ;
        RECT  0 52.464 0.084 52.488 ;
    END
  END write_data[32]
  PIN write_data[33]
    DIRECTION INPUT ;
    USE SIGNAL ;
    PORT
      LAYER M4 ;
        RECT  0 52.56 0.084 52.584 ;
    END
  END write_data[33]
  PIN write_data[34]
    DIRECTION INPUT ;
    USE SIGNAL ;
    PORT
      LAYER M4 ;
        RECT  0 52.656 0.084 52.68 ;
    END
  END write_data[34]
  PIN write_data[35]
    DIRECTION INPUT ;
    USE SIGNAL ;
    PORT
      LAYER M4 ;
        RECT  0 52.752 0.084 52.776 ;
    END
  END write_data[35]
  PIN write_data[36]
    DIRECTION INPUT ;
    USE SIGNAL ;
    PORT
      LAYER M4 ;
        RECT  0 52.848 0.084 52.872 ;
    END
  END write_data[36]
  PIN write_data[37]
    DIRECTION INPUT ;
    USE SIGNAL ;
    PORT
      LAYER M4 ;
        RECT  0 52.944 0.084 52.968 ;
    END
  END write_data[37]
  PIN write_data[38]
    DIRECTION INPUT ;
    USE SIGNAL ;
    PORT
      LAYER M4 ;
        RECT  0 53.04 0.084 53.064 ;
    END
  END write_data[38]
  PIN write_data[39]
    DIRECTION INPUT ;
    USE SIGNAL ;
    PORT
      LAYER M4 ;
        RECT  0 53.136 0.084 53.16 ;
    END
  END write_data[39]
  PIN write_data[3]
    DIRECTION INPUT ;
    USE SIGNAL ;
    PORT
      LAYER M4 ;
        RECT  0 68.112 0.084 68.136 ;
    END
  END write_data[3]
  PIN write_data[40]
    DIRECTION INPUT ;
    USE SIGNAL ;
    PORT
      LAYER M4 ;
        RECT  0 53.232 0.084 53.256 ;
    END
  END write_data[40]
  PIN write_data[41]
    DIRECTION INPUT ;
    USE SIGNAL ;
    PORT
      LAYER M4 ;
        RECT  0 53.328 0.084 53.352 ;
    END
  END write_data[41]
  PIN write_data[42]
    DIRECTION INPUT ;
    USE SIGNAL ;
    PORT
      LAYER M4 ;
        RECT  0 53.424 0.084 53.448 ;
    END
  END write_data[42]
  PIN write_data[43]
    DIRECTION INPUT ;
    USE SIGNAL ;
    PORT
      LAYER M4 ;
        RECT  0 53.52 0.084 53.544 ;
    END
  END write_data[43]
  PIN write_data[44]
    DIRECTION INPUT ;
    USE SIGNAL ;
    PORT
      LAYER M4 ;
        RECT  0 53.616 0.084 53.64 ;
    END
  END write_data[44]
  PIN write_data[45]
    DIRECTION INPUT ;
    USE SIGNAL ;
    PORT
      LAYER M4 ;
        RECT  0 53.712 0.084 53.736 ;
    END
  END write_data[45]
  PIN write_data[46]
    DIRECTION INPUT ;
    USE SIGNAL ;
    PORT
      LAYER M4 ;
        RECT  0 53.808 0.084 53.832 ;
    END
  END write_data[46]
  PIN write_data[47]
    DIRECTION INPUT ;
    USE SIGNAL ;
    PORT
      LAYER M4 ;
        RECT  0 53.904 0.084 53.928 ;
    END
  END write_data[47]
  PIN write_data[48]
    DIRECTION INPUT ;
    USE SIGNAL ;
    PORT
      LAYER M4 ;
        RECT  0 54 0.084 54.024 ;
    END
  END write_data[48]
  PIN write_data[49]
    DIRECTION INPUT ;
    USE SIGNAL ;
    PORT
      LAYER M4 ;
        RECT  0 54.096 0.084 54.12 ;
    END
  END write_data[49]
  PIN write_data[4]
    DIRECTION INPUT ;
    USE SIGNAL ;
    PORT
      LAYER M4 ;
        RECT  0 68.208 0.084 68.232 ;
    END
  END write_data[4]
  PIN write_data[50]
    DIRECTION INPUT ;
    USE SIGNAL ;
    PORT
      LAYER M4 ;
        RECT  0 54.192 0.084 54.216 ;
    END
  END write_data[50]
  PIN write_data[51]
    DIRECTION INPUT ;
    USE SIGNAL ;
    PORT
      LAYER M4 ;
        RECT  0 54.288 0.084 54.312 ;
    END
  END write_data[51]
  PIN write_data[52]
    DIRECTION INPUT ;
    USE SIGNAL ;
    PORT
      LAYER M4 ;
        RECT  0 54.384 0.084 54.408 ;
    END
  END write_data[52]
  PIN write_data[53]
    DIRECTION INPUT ;
    USE SIGNAL ;
    PORT
      LAYER M4 ;
        RECT  0 54.48 0.084 54.504 ;
    END
  END write_data[53]
  PIN write_data[54]
    DIRECTION INPUT ;
    USE SIGNAL ;
    PORT
      LAYER M4 ;
        RECT  0 54.576 0.084 54.6 ;
    END
  END write_data[54]
  PIN write_data[55]
    DIRECTION INPUT ;
    USE SIGNAL ;
    PORT
      LAYER M4 ;
        RECT  0 54.672 0.084 54.696 ;
    END
  END write_data[55]
  PIN write_data[56]
    DIRECTION INPUT ;
    USE SIGNAL ;
    PORT
      LAYER M4 ;
        RECT  0 54.768 0.084 54.792 ;
    END
  END write_data[56]
  PIN write_data[57]
    DIRECTION INPUT ;
    USE SIGNAL ;
    PORT
      LAYER M4 ;
        RECT  0 54.864 0.084 54.888 ;
    END
  END write_data[57]
  PIN write_data[58]
    DIRECTION INPUT ;
    USE SIGNAL ;
    PORT
      LAYER M4 ;
        RECT  0 54.96 0.084 54.984 ;
    END
  END write_data[58]
  PIN write_data[59]
    DIRECTION INPUT ;
    USE SIGNAL ;
    PORT
      LAYER M4 ;
        RECT  0 55.056 0.084 55.08 ;
    END
  END write_data[59]
  PIN write_data[5]
    DIRECTION INPUT ;
    USE SIGNAL ;
    PORT
      LAYER M4 ;
        RECT  0 68.304 0.084 68.328 ;
    END
  END write_data[5]
  PIN write_data[60]
    DIRECTION INPUT ;
    USE SIGNAL ;
    PORT
      LAYER M4 ;
        RECT  0 55.152 0.084 55.176 ;
    END
  END write_data[60]
  PIN write_data[61]
    DIRECTION INPUT ;
    USE SIGNAL ;
    PORT
      LAYER M4 ;
        RECT  0 55.248 0.084 55.272 ;
    END
  END write_data[61]
  PIN write_data[62]
    DIRECTION INPUT ;
    USE SIGNAL ;
    PORT
      LAYER M4 ;
        RECT  0 55.344 0.084 55.368 ;
    END
  END write_data[62]
  PIN write_data[63]
    DIRECTION INPUT ;
    USE SIGNAL ;
    PORT
      LAYER M4 ;
        RECT  0 26.256 0.084 26.28 ;
    END
  END write_data[63]
  PIN write_data[64]
    DIRECTION INPUT ;
    USE SIGNAL ;
    PORT
      LAYER M4 ;
        RECT  0 26.352 0.084 26.376 ;
    END
  END write_data[64]
  PIN write_data[65]
    DIRECTION INPUT ;
    USE SIGNAL ;
    PORT
      LAYER M4 ;
        RECT  0 26.448 0.084 26.472 ;
    END
  END write_data[65]
  PIN write_data[66]
    DIRECTION INPUT ;
    USE SIGNAL ;
    PORT
      LAYER M4 ;
        RECT  0 26.544 0.084 26.568 ;
    END
  END write_data[66]
  PIN write_data[67]
    DIRECTION INPUT ;
    USE SIGNAL ;
    PORT
      LAYER M4 ;
        RECT  0 26.64 0.084 26.664 ;
    END
  END write_data[67]
  PIN write_data[68]
    DIRECTION INPUT ;
    USE SIGNAL ;
    PORT
      LAYER M4 ;
        RECT  0 26.736 0.084 26.76 ;
    END
  END write_data[68]
  PIN write_data[69]
    DIRECTION INPUT ;
    USE SIGNAL ;
    PORT
      LAYER M4 ;
        RECT  0 26.832 0.084 26.856 ;
    END
  END write_data[69]
  PIN write_data[6]
    DIRECTION INPUT ;
    USE SIGNAL ;
    PORT
      LAYER M4 ;
        RECT  0 68.4 0.084 68.424 ;
    END
  END write_data[6]
  PIN write_data[70]
    DIRECTION INPUT ;
    USE SIGNAL ;
    PORT
      LAYER M4 ;
        RECT  0 26.928 0.084 26.952 ;
    END
  END write_data[70]
  PIN write_data[71]
    DIRECTION INPUT ;
    USE SIGNAL ;
    PORT
      LAYER M4 ;
        RECT  0 27.024 0.084 27.048 ;
    END
  END write_data[71]
  PIN write_data[72]
    DIRECTION INPUT ;
    USE SIGNAL ;
    PORT
      LAYER M4 ;
        RECT  0 27.12 0.084 27.144 ;
    END
  END write_data[72]
  PIN write_data[73]
    DIRECTION INPUT ;
    USE SIGNAL ;
    PORT
      LAYER M4 ;
        RECT  0 27.216 0.084 27.24 ;
    END
  END write_data[73]
  PIN write_data[74]
    DIRECTION INPUT ;
    USE SIGNAL ;
    PORT
      LAYER M4 ;
        RECT  0 27.312 0.084 27.336 ;
    END
  END write_data[74]
  PIN write_data[75]
    DIRECTION INPUT ;
    USE SIGNAL ;
    PORT
      LAYER M4 ;
        RECT  0 27.408 0.084 27.432 ;
    END
  END write_data[75]
  PIN write_data[76]
    DIRECTION INPUT ;
    USE SIGNAL ;
    PORT
      LAYER M4 ;
        RECT  0 27.504 0.084 27.528 ;
    END
  END write_data[76]
  PIN write_data[77]
    DIRECTION INPUT ;
    USE SIGNAL ;
    PORT
      LAYER M4 ;
        RECT  0 27.6 0.084 27.624 ;
    END
  END write_data[77]
  PIN write_data[78]
    DIRECTION INPUT ;
    USE SIGNAL ;
    PORT
      LAYER M4 ;
        RECT  0 27.696 0.084 27.72 ;
    END
  END write_data[78]
  PIN write_data[79]
    DIRECTION INPUT ;
    USE SIGNAL ;
    PORT
      LAYER M4 ;
        RECT  0 27.792 0.084 27.816 ;
    END
  END write_data[79]
  PIN write_data[7]
    DIRECTION INPUT ;
    USE SIGNAL ;
    PORT
      LAYER M4 ;
        RECT  0 68.496 0.084 68.52 ;
    END
  END write_data[7]
  PIN write_data[80]
    DIRECTION INPUT ;
    USE SIGNAL ;
    PORT
      LAYER M4 ;
        RECT  0 27.888 0.084 27.912 ;
    END
  END write_data[80]
  PIN write_data[81]
    DIRECTION INPUT ;
    USE SIGNAL ;
    PORT
      LAYER M4 ;
        RECT  0 27.984 0.084 28.008 ;
    END
  END write_data[81]
  PIN write_data[82]
    DIRECTION INPUT ;
    USE SIGNAL ;
    PORT
      LAYER M4 ;
        RECT  0 28.08 0.084 28.104 ;
    END
  END write_data[82]
  PIN write_data[83]
    DIRECTION INPUT ;
    USE SIGNAL ;
    PORT
      LAYER M4 ;
        RECT  0 28.176 0.084 28.2 ;
    END
  END write_data[83]
  PIN write_data[84]
    DIRECTION INPUT ;
    USE SIGNAL ;
    PORT
      LAYER M4 ;
        RECT  0 28.272 0.084 28.296 ;
    END
  END write_data[84]
  PIN write_data[85]
    DIRECTION INPUT ;
    USE SIGNAL ;
    PORT
      LAYER M4 ;
        RECT  0 28.368 0.084 28.392 ;
    END
  END write_data[85]
  PIN write_data[86]
    DIRECTION INPUT ;
    USE SIGNAL ;
    PORT
      LAYER M4 ;
        RECT  0 28.464 0.084 28.488 ;
    END
  END write_data[86]
  PIN write_data[87]
    DIRECTION INPUT ;
    USE SIGNAL ;
    PORT
      LAYER M4 ;
        RECT  0 28.56 0.084 28.584 ;
    END
  END write_data[87]
  PIN write_data[88]
    DIRECTION INPUT ;
    USE SIGNAL ;
    PORT
      LAYER M4 ;
        RECT  0 28.656 0.084 28.68 ;
    END
  END write_data[88]
  PIN write_data[89]
    DIRECTION INPUT ;
    USE SIGNAL ;
    PORT
      LAYER M4 ;
        RECT  0 28.752 0.084 28.776 ;
    END
  END write_data[89]
  PIN write_data[8]
    DIRECTION INPUT ;
    USE SIGNAL ;
    PORT
      LAYER M4 ;
        RECT  0 68.592 0.084 68.616 ;
    END
  END write_data[8]
  PIN write_data[90]
    DIRECTION INPUT ;
    USE SIGNAL ;
    PORT
      LAYER M4 ;
        RECT  0 28.848 0.084 28.872 ;
    END
  END write_data[90]
  PIN write_data[91]
    DIRECTION INPUT ;
    USE SIGNAL ;
    PORT
      LAYER M4 ;
        RECT  0 28.944 0.084 28.968 ;
    END
  END write_data[91]
  PIN write_data[92]
    DIRECTION INPUT ;
    USE SIGNAL ;
    PORT
      LAYER M4 ;
        RECT  0 29.04 0.084 29.064 ;
    END
  END write_data[92]
  PIN write_data[93]
    DIRECTION INPUT ;
    USE SIGNAL ;
    PORT
      LAYER M4 ;
        RECT  0 29.136 0.084 29.16 ;
    END
  END write_data[93]
  PIN write_data[94]
    DIRECTION INPUT ;
    USE SIGNAL ;
    PORT
      LAYER M4 ;
        RECT  0 29.232 0.084 29.256 ;
    END
  END write_data[94]
  PIN write_data[95]
    DIRECTION INPUT ;
    USE SIGNAL ;
    PORT
      LAYER M4 ;
        RECT  0 23.184 0.084 23.208 ;
    END
  END write_data[95]
  PIN write_data[96]
    DIRECTION INPUT ;
    USE SIGNAL ;
    PORT
      LAYER M4 ;
        RECT  0 23.28 0.084 23.304 ;
    END
  END write_data[96]
  PIN write_data[97]
    DIRECTION INPUT ;
    USE SIGNAL ;
    PORT
      LAYER M4 ;
        RECT  0 23.376 0.084 23.4 ;
    END
  END write_data[97]
  PIN write_data[98]
    DIRECTION INPUT ;
    USE SIGNAL ;
    PORT
      LAYER M4 ;
        RECT  0 23.472 0.084 23.496 ;
    END
  END write_data[98]
  PIN write_data[99]
    DIRECTION INPUT ;
    USE SIGNAL ;
    PORT
      LAYER M4 ;
        RECT  0 23.568 0.084 23.592 ;
    END
  END write_data[99]
  PIN write_data[9]
    DIRECTION INPUT ;
    USE SIGNAL ;
    PORT
      LAYER M4 ;
        RECT  0 68.688 0.084 68.712 ;
    END
  END write_data[9]
  PIN VDD
    DIRECTION INOUT ;
    USE POWER ;
    PORT
      LAYER M5 ;
        RECT  83.592 2.151 83.712 88.569 ;
        RECT  78.192 2.151 78.312 88.569 ;
        RECT  72.792 2.151 72.912 88.569 ;
        RECT  67.392 2.151 67.512 88.569 ;
        RECT  61.992 2.151 62.112 88.569 ;
        RECT  56.592 2.151 56.712 88.569 ;
        RECT  51.192 2.151 51.312 88.569 ;
        RECT  45.792 2.151 45.912 88.569 ;
        RECT  40.392 2.151 40.512 88.569 ;
        RECT  34.992 2.151 35.112 88.569 ;
        RECT  29.592 2.151 29.712 88.569 ;
        RECT  24.192 2.151 24.312 88.569 ;
        RECT  18.792 2.151 18.912 88.569 ;
        RECT  13.392 2.151 13.512 88.569 ;
        RECT  7.992 2.151 8.112 88.569 ;
        RECT  2.592 2.151 2.712 88.569 ;
    END
  END VDD
  PIN VSS
    DIRECTION INOUT ;
    USE GROUND ;
    PORT
      LAYER M5 ;
        RECT  83.4 2.137 83.52 88.583 ;
        RECT  78 2.137 78.12 88.583 ;
        RECT  72.6 2.137 72.72 88.583 ;
        RECT  67.2 2.137 67.32 88.583 ;
        RECT  61.8 2.137 61.92 88.583 ;
        RECT  56.4 2.137 56.52 88.583 ;
        RECT  51 2.137 51.12 88.583 ;
        RECT  45.6 2.137 45.72 88.583 ;
        RECT  40.2 2.137 40.32 88.583 ;
        RECT  34.8 2.137 34.92 88.583 ;
        RECT  29.4 2.137 29.52 88.583 ;
        RECT  24 2.137 24.12 88.583 ;
        RECT  18.6 2.137 18.72 88.583 ;
        RECT  13.2 2.137 13.32 88.583 ;
        RECT  7.8 2.137 7.92 88.583 ;
        RECT  2.4 2.137 2.52 88.583 ;
    END
  END VSS
  OBS
    LAYER RVTN ;
     RECT  2.16 2.16 88.56 2.295 ;
     RECT  2.16 2.565 88.56 2.835 ;
     RECT  2.16 3.105 88.56 3.375 ;
     RECT  2.16 3.645 88.56 3.915 ;
     RECT  2.16 4.185 88.56 4.455 ;
     RECT  2.16 4.725 88.56 4.995 ;
     RECT  2.16 5.265 88.56 5.535 ;
     RECT  2.16 5.805 88.56 6.075 ;
     RECT  2.16 6.345 88.56 6.615 ;
     RECT  2.16 6.885 88.56 7.155 ;
     RECT  2.16 7.425 88.56 7.695 ;
     RECT  2.16 7.965 88.56 8.235 ;
     RECT  2.16 8.505 88.56 8.775 ;
     RECT  2.16 9.045 88.56 9.315 ;
     RECT  2.16 9.585 88.56 9.855 ;
     RECT  2.16 10.125 88.56 10.395 ;
     RECT  2.16 10.665 88.56 10.935 ;
     RECT  2.16 11.205 88.56 11.475 ;
     RECT  2.16 11.745 88.56 12.015 ;
     RECT  2.16 12.285 88.56 12.555 ;
     RECT  2.16 12.825 88.56 13.095 ;
     RECT  2.16 13.365 88.56 13.635 ;
     RECT  2.16 13.905 88.56 14.175 ;
     RECT  2.16 14.445 88.56 14.715 ;
     RECT  2.16 14.985 88.56 15.255 ;
     RECT  2.16 15.525 88.56 15.795 ;
     RECT  2.16 16.065 88.56 16.335 ;
     RECT  2.16 16.605 88.56 16.875 ;
     RECT  2.16 17.145 88.56 17.415 ;
     RECT  2.16 17.685 88.56 17.955 ;
     RECT  2.16 18.225 88.56 18.495 ;
     RECT  2.16 18.765 88.56 19.035 ;
     RECT  2.16 19.305 88.56 19.575 ;
     RECT  2.16 19.845 88.56 20.115 ;
     RECT  2.16 20.385 88.56 20.655 ;
     RECT  2.16 20.925 88.56 21.195 ;
     RECT  2.16 21.465 88.56 21.735 ;
     RECT  2.16 22.005 88.56 22.275 ;
     RECT  2.16 22.545 88.56 22.815 ;
     RECT  2.16 23.085 88.56 23.355 ;
     RECT  2.16 23.625 88.56 23.895 ;
     RECT  2.16 24.165 88.56 24.435 ;
     RECT  2.16 24.705 88.56 24.975 ;
     RECT  2.16 25.245 88.56 25.515 ;
     RECT  2.16 25.785 88.56 26.055 ;
     RECT  2.16 26.325 88.56 26.595 ;
     RECT  2.16 26.865 88.56 27.135 ;
     RECT  2.16 27.405 88.56 27.675 ;
     RECT  2.16 27.945 88.56 28.215 ;
     RECT  2.16 28.485 88.56 28.755 ;
     RECT  2.16 29.025 88.56 29.295 ;
     RECT  2.16 29.565 88.56 29.835 ;
     RECT  2.16 30.105 88.56 30.375 ;
     RECT  2.16 30.645 88.56 30.915 ;
     RECT  2.16 31.185 88.56 31.455 ;
     RECT  2.16 31.725 88.56 31.995 ;
     RECT  2.16 32.265 88.56 32.535 ;
     RECT  2.16 32.805 88.56 33.075 ;
     RECT  2.16 33.345 88.56 33.615 ;
     RECT  2.16 33.885 88.56 34.155 ;
     RECT  2.16 34.425 88.56 34.695 ;
     RECT  2.16 34.965 88.56 35.235 ;
     RECT  2.16 35.505 88.56 35.775 ;
     RECT  2.16 36.045 88.56 36.315 ;
     RECT  2.16 36.585 88.56 36.855 ;
     RECT  2.16 37.125 88.56 37.395 ;
     RECT  2.16 37.665 88.56 37.935 ;
     RECT  2.16 38.205 88.56 38.475 ;
     RECT  2.16 38.745 88.56 39.015 ;
     RECT  2.16 39.285 88.56 39.555 ;
     RECT  2.16 39.825 88.56 40.095 ;
     RECT  2.16 40.365 88.56 40.635 ;
     RECT  2.16 40.905 88.56 41.175 ;
     RECT  2.16 41.445 88.56 41.715 ;
     RECT  2.16 41.985 88.56 42.255 ;
     RECT  2.16 42.525 88.56 42.795 ;
     RECT  2.16 43.065 88.56 43.335 ;
     RECT  2.16 43.605 88.56 43.875 ;
     RECT  2.16 44.145 88.56 44.415 ;
     RECT  2.16 44.685 88.56 44.955 ;
     RECT  2.16 45.225 88.56 45.495 ;
     RECT  2.16 45.765 88.56 46.035 ;
     RECT  2.16 46.305 88.56 46.575 ;
     RECT  2.16 46.845 88.56 47.115 ;
     RECT  2.16 47.385 88.56 47.655 ;
     RECT  2.16 47.925 88.56 48.195 ;
     RECT  2.16 48.465 88.56 48.735 ;
     RECT  2.16 49.005 88.56 49.275 ;
     RECT  2.16 49.545 88.56 49.815 ;
     RECT  2.16 50.085 88.56 50.355 ;
     RECT  2.16 50.625 88.56 50.895 ;
     RECT  2.16 51.165 88.56 51.435 ;
     RECT  2.16 51.705 88.56 51.975 ;
     RECT  2.16 52.245 88.56 52.515 ;
     RECT  2.16 52.785 88.56 53.055 ;
     RECT  2.16 53.325 88.56 53.595 ;
     RECT  2.16 53.865 88.56 54.135 ;
     RECT  2.16 54.405 88.56 54.675 ;
     RECT  2.16 54.945 88.56 55.215 ;
     RECT  2.16 55.485 88.56 55.755 ;
     RECT  2.16 56.025 88.56 56.295 ;
     RECT  2.16 56.565 88.56 56.835 ;
     RECT  2.16 57.105 88.56 57.375 ;
     RECT  2.16 57.645 88.56 57.915 ;
     RECT  2.16 58.185 88.56 58.455 ;
     RECT  2.16 58.725 88.56 58.995 ;
     RECT  2.16 59.265 88.56 59.535 ;
     RECT  2.16 59.805 88.56 60.075 ;
     RECT  2.16 60.345 88.56 60.615 ;
     RECT  2.16 60.885 88.56 61.155 ;
     RECT  2.16 61.425 88.56 61.695 ;
     RECT  2.16 61.965 88.56 62.235 ;
     RECT  2.16 62.505 88.56 62.775 ;
     RECT  2.16 63.045 88.56 63.315 ;
     RECT  2.16 63.585 88.56 63.855 ;
     RECT  2.16 64.125 88.56 64.395 ;
     RECT  2.16 64.665 88.56 64.935 ;
     RECT  2.16 65.205 88.56 65.475 ;
     RECT  2.16 65.745 88.56 66.015 ;
     RECT  2.16 66.285 88.56 66.555 ;
     RECT  2.16 66.825 88.56 67.095 ;
     RECT  2.16 67.365 88.56 67.635 ;
     RECT  2.16 67.905 88.56 68.175 ;
     RECT  2.16 68.445 88.56 68.715 ;
     RECT  2.16 68.985 88.56 69.255 ;
     RECT  2.16 69.525 88.56 69.795 ;
     RECT  2.16 70.065 88.56 70.335 ;
     RECT  2.16 70.605 88.56 70.875 ;
     RECT  2.16 71.145 88.56 71.415 ;
     RECT  2.16 71.685 88.56 71.955 ;
     RECT  2.16 72.225 88.56 72.495 ;
     RECT  2.16 72.765 88.56 73.035 ;
     RECT  2.16 73.305 88.56 73.575 ;
     RECT  2.16 73.845 88.56 74.115 ;
     RECT  2.16 74.385 88.56 74.655 ;
     RECT  2.16 74.925 88.56 75.195 ;
     RECT  2.16 75.465 88.56 75.735 ;
     RECT  2.16 76.005 88.56 76.275 ;
     RECT  2.16 76.545 88.56 76.815 ;
     RECT  2.16 77.085 88.56 77.355 ;
     RECT  2.16 77.625 88.56 77.895 ;
     RECT  2.16 78.165 88.56 78.435 ;
     RECT  2.16 78.705 88.56 78.975 ;
     RECT  2.16 79.245 88.56 79.515 ;
     RECT  2.16 79.785 88.56 80.055 ;
     RECT  2.16 80.325 88.56 80.595 ;
     RECT  2.16 80.865 88.56 81.135 ;
     RECT  2.16 81.405 88.56 81.675 ;
     RECT  2.16 81.945 88.56 82.215 ;
     RECT  2.16 82.485 88.56 82.755 ;
     RECT  2.16 83.025 88.56 83.295 ;
     RECT  2.16 83.565 88.56 83.835 ;
     RECT  2.16 84.105 88.56 84.375 ;
     RECT  2.16 84.645 88.56 84.915 ;
     RECT  2.16 85.185 88.56 85.455 ;
     RECT  2.16 85.725 88.56 85.995 ;
     RECT  2.16 86.265 88.56 86.535 ;
     RECT  2.16 86.805 88.56 87.075 ;
     RECT  2.16 87.345 88.56 87.615 ;
     RECT  2.16 87.885 88.56 88.155 ;
     RECT  2.16 88.425 88.56 88.56 ;
    LAYER RVTP ;
     RECT  2.16 2.295 88.56 2.565 ;
     RECT  2.16 2.835 88.56 3.105 ;
     RECT  2.16 3.375 88.56 3.645 ;
     RECT  2.16 3.915 88.56 4.185 ;
     RECT  2.16 4.455 88.56 4.725 ;
     RECT  2.16 4.995 88.56 5.265 ;
     RECT  2.16 5.535 88.56 5.805 ;
     RECT  2.16 6.075 88.56 6.345 ;
     RECT  2.16 6.615 88.56 6.885 ;
     RECT  2.16 7.155 88.56 7.425 ;
     RECT  2.16 7.695 88.56 7.965 ;
     RECT  2.16 8.235 88.56 8.505 ;
     RECT  2.16 8.775 88.56 9.045 ;
     RECT  2.16 9.315 88.56 9.585 ;
     RECT  2.16 9.855 88.56 10.125 ;
     RECT  2.16 10.395 88.56 10.665 ;
     RECT  2.16 10.935 88.56 11.205 ;
     RECT  2.16 11.475 88.56 11.745 ;
     RECT  2.16 12.015 88.56 12.285 ;
     RECT  2.16 12.555 88.56 12.825 ;
     RECT  2.16 13.095 88.56 13.365 ;
     RECT  2.16 13.635 88.56 13.905 ;
     RECT  2.16 14.175 88.56 14.445 ;
     RECT  2.16 14.715 88.56 14.985 ;
     RECT  2.16 15.255 88.56 15.525 ;
     RECT  2.16 15.795 88.56 16.065 ;
     RECT  2.16 16.335 88.56 16.605 ;
     RECT  2.16 16.875 88.56 17.145 ;
     RECT  2.16 17.415 88.56 17.685 ;
     RECT  2.16 17.955 88.56 18.225 ;
     RECT  2.16 18.495 88.56 18.765 ;
     RECT  2.16 19.035 88.56 19.305 ;
     RECT  2.16 19.575 88.56 19.845 ;
     RECT  2.16 20.115 88.56 20.385 ;
     RECT  2.16 20.655 88.56 20.925 ;
     RECT  2.16 21.195 88.56 21.465 ;
     RECT  2.16 21.735 88.56 22.005 ;
     RECT  2.16 22.275 88.56 22.545 ;
     RECT  2.16 22.815 88.56 23.085 ;
     RECT  2.16 23.355 88.56 23.625 ;
     RECT  2.16 23.895 88.56 24.165 ;
     RECT  2.16 24.435 88.56 24.705 ;
     RECT  2.16 24.975 88.56 25.245 ;
     RECT  2.16 25.515 88.56 25.785 ;
     RECT  2.16 26.055 88.56 26.325 ;
     RECT  2.16 26.595 88.56 26.865 ;
     RECT  2.16 27.135 88.56 27.405 ;
     RECT  2.16 27.675 88.56 27.945 ;
     RECT  2.16 28.215 88.56 28.485 ;
     RECT  2.16 28.755 88.56 29.025 ;
     RECT  2.16 29.295 88.56 29.565 ;
     RECT  2.16 29.835 88.56 30.105 ;
     RECT  2.16 30.375 88.56 30.645 ;
     RECT  2.16 30.915 88.56 31.185 ;
     RECT  2.16 31.455 88.56 31.725 ;
     RECT  2.16 31.995 88.56 32.265 ;
     RECT  2.16 32.535 88.56 32.805 ;
     RECT  2.16 33.075 88.56 33.345 ;
     RECT  2.16 33.615 88.56 33.885 ;
     RECT  2.16 34.155 88.56 34.425 ;
     RECT  2.16 34.695 88.56 34.965 ;
     RECT  2.16 35.235 88.56 35.505 ;
     RECT  2.16 35.775 88.56 36.045 ;
     RECT  2.16 36.315 88.56 36.585 ;
     RECT  2.16 36.855 88.56 37.125 ;
     RECT  2.16 37.395 88.56 37.665 ;
     RECT  2.16 37.935 88.56 38.205 ;
     RECT  2.16 38.475 88.56 38.745 ;
     RECT  2.16 39.015 88.56 39.285 ;
     RECT  2.16 39.555 88.56 39.825 ;
     RECT  2.16 40.095 88.56 40.365 ;
     RECT  2.16 40.635 88.56 40.905 ;
     RECT  2.16 41.175 88.56 41.445 ;
     RECT  2.16 41.715 88.56 41.985 ;
     RECT  2.16 42.255 88.56 42.525 ;
     RECT  2.16 42.795 88.56 43.065 ;
     RECT  2.16 43.335 88.56 43.605 ;
     RECT  2.16 43.875 88.56 44.145 ;
     RECT  2.16 44.415 88.56 44.685 ;
     RECT  2.16 44.955 88.56 45.225 ;
     RECT  2.16 45.495 88.56 45.765 ;
     RECT  2.16 46.035 88.56 46.305 ;
     RECT  2.16 46.575 88.56 46.845 ;
     RECT  2.16 47.115 88.56 47.385 ;
     RECT  2.16 47.655 88.56 47.925 ;
     RECT  2.16 48.195 88.56 48.465 ;
     RECT  2.16 48.735 88.56 49.005 ;
     RECT  2.16 49.275 88.56 49.545 ;
     RECT  2.16 49.815 88.56 50.085 ;
     RECT  2.16 50.355 88.56 50.625 ;
     RECT  2.16 50.895 88.56 51.165 ;
     RECT  2.16 51.435 88.56 51.705 ;
     RECT  2.16 51.975 88.56 52.245 ;
     RECT  2.16 52.515 88.56 52.785 ;
     RECT  2.16 53.055 88.56 53.325 ;
     RECT  2.16 53.595 88.56 53.865 ;
     RECT  2.16 54.135 88.56 54.405 ;
     RECT  2.16 54.675 88.56 54.945 ;
     RECT  2.16 55.215 88.56 55.485 ;
     RECT  2.16 55.755 88.56 56.025 ;
     RECT  2.16 56.295 88.56 56.565 ;
     RECT  2.16 56.835 88.56 57.105 ;
     RECT  2.16 57.375 88.56 57.645 ;
     RECT  2.16 57.915 88.56 58.185 ;
     RECT  2.16 58.455 88.56 58.725 ;
     RECT  2.16 58.995 88.56 59.265 ;
     RECT  2.16 59.535 88.56 59.805 ;
     RECT  2.16 60.075 88.56 60.345 ;
     RECT  2.16 60.615 88.56 60.885 ;
     RECT  2.16 61.155 88.56 61.425 ;
     RECT  2.16 61.695 88.56 61.965 ;
     RECT  2.16 62.235 88.56 62.505 ;
     RECT  2.16 62.775 88.56 63.045 ;
     RECT  2.16 63.315 88.56 63.585 ;
     RECT  2.16 63.855 88.56 64.125 ;
     RECT  2.16 64.395 88.56 64.665 ;
     RECT  2.16 64.935 88.56 65.205 ;
     RECT  2.16 65.475 88.56 65.745 ;
     RECT  2.16 66.015 88.56 66.285 ;
     RECT  2.16 66.555 88.56 66.825 ;
     RECT  2.16 67.095 88.56 67.365 ;
     RECT  2.16 67.635 88.56 67.905 ;
     RECT  2.16 68.175 88.56 68.445 ;
     RECT  2.16 68.715 88.56 68.985 ;
     RECT  2.16 69.255 88.56 69.525 ;
     RECT  2.16 69.795 88.56 70.065 ;
     RECT  2.16 70.335 88.56 70.605 ;
     RECT  2.16 70.875 88.56 71.145 ;
     RECT  2.16 71.415 88.56 71.685 ;
     RECT  2.16 71.955 88.56 72.225 ;
     RECT  2.16 72.495 88.56 72.765 ;
     RECT  2.16 73.035 88.56 73.305 ;
     RECT  2.16 73.575 88.56 73.845 ;
     RECT  2.16 74.115 88.56 74.385 ;
     RECT  2.16 74.655 88.56 74.925 ;
     RECT  2.16 75.195 88.56 75.465 ;
     RECT  2.16 75.735 88.56 76.005 ;
     RECT  2.16 76.275 88.56 76.545 ;
     RECT  2.16 76.815 88.56 77.085 ;
     RECT  2.16 77.355 88.56 77.625 ;
     RECT  2.16 77.895 88.56 78.165 ;
     RECT  2.16 78.435 88.56 78.705 ;
     RECT  2.16 78.975 88.56 79.245 ;
     RECT  2.16 79.515 88.56 79.785 ;
     RECT  2.16 80.055 88.56 80.325 ;
     RECT  2.16 80.595 88.56 80.865 ;
     RECT  2.16 81.135 88.56 81.405 ;
     RECT  2.16 81.675 88.56 81.945 ;
     RECT  2.16 82.215 88.56 82.485 ;
     RECT  2.16 82.755 88.56 83.025 ;
     RECT  2.16 83.295 88.56 83.565 ;
     RECT  2.16 83.835 88.56 84.105 ;
     RECT  2.16 84.375 88.56 84.645 ;
     RECT  2.16 84.915 88.56 85.185 ;
     RECT  2.16 85.455 88.56 85.725 ;
     RECT  2.16 85.995 88.56 86.265 ;
     RECT  2.16 86.535 88.56 86.805 ;
     RECT  2.16 87.075 88.56 87.345 ;
     RECT  2.16 87.615 88.56 87.885 ;
     RECT  2.16 88.155 88.56 88.425 ;
    LAYER M1 ;
     RECT  2.16 2.151 88.56 88.569 ;
    LAYER M2 ;
     RECT  0.031 52.371 0.067 52.389 ;
     RECT  0.067 52.371 0.103 52.578 ;
     RECT  0.031 56.034 0.103 56.052 ;
     RECT  0.031 66.6 0.103 66.618 ;
     RECT  0.031 67.986 0.103 68.004 ;
     RECT  0.031 33.048 0.131 33.174 ;
     RECT  0.103 67.986 0.131 68.238 ;
     RECT  0.103 24.48 0.139 24.768 ;
     RECT  0.103 66.6 0.139 66.888 ;
     RECT  0.131 68.22 0.139 68.238 ;
     RECT  0.103 22.788 0.175 22.806 ;
     RECT  0.139 24.372 0.175 24.768 ;
     RECT  0.103 54.036 0.203 54.468 ;
     RECT  0.103 55.656 0.319 56.052 ;
     RECT  0.139 28.224 0.499 28.242 ;
     RECT  0.175 29.07 0.499 29.088 ;
     RECT  0.103 52.371 0.535 53.01 ;
     RECT  0.499 28.224 0.599 29.088 ;
     RECT  0.175 27.144 1.723 27.162 ;
     RECT  0.175 22.788 2.16 24.768 ;
     RECT  1.723 27.072 2.16 27.162 ;
     RECT  0.599 28.224 2.16 28.242 ;
     RECT  0.599 29.07 2.16 29.088 ;
     RECT  0.131 33.156 2.16 33.174 ;
     RECT  0.067 49.32 2.16 49.338 ;
     RECT  0.535 52.29 2.16 53.514 ;
     RECT  0.319 55.494 2.16 56.052 ;
     RECT  0.139 66.6 2.16 67.428 ;
     RECT  0.139 68.22 2.16 68.4 ;
     RECT  0.103 71.226 2.16 71.244 ;
     RECT  2.16 2.151 39.595 88.569 ;
     RECT  39.595 2.07 42.907 88.569 ;
     RECT  42.907 1.962 43.051 88.569 ;
     RECT  43.051 1.764 47.111 88.569 ;
     RECT  47.111 2.106 48.155 88.569 ;
     RECT  48.155 2.151 51.943 88.569 ;
     RECT  51.943 2.034 55.067 88.569 ;
     RECT  55.067 2.106 55.643 88.569 ;
     RECT  56.299 1.224 56.399 1.242 ;
     RECT  55.643 2.151 62.671 88.569 ;
     RECT  62.671 1.998 65.299 88.569 ;
     RECT  65.299 1.881 67.567 88.569 ;
     RECT  67.567 1.836 70.655 88.569 ;
     RECT  70.655 1.881 71.771 88.569 ;
     RECT  71.771 1.926 71.951 88.569 ;
     RECT  71.951 2.106 73.499 88.569 ;
     RECT  73.499 2.151 88.56 88.569 ;
     RECT  88.56 51.246 89.483 55.548 ;
     RECT  89.483 51.246 90.095 54.126 ;
     RECT  89.483 55.53 90.095 55.548 ;
     RECT  88.56 48.438 90.131 48.456 ;
     RECT  90.095 51.678 90.167 53.622 ;
     RECT  90.167 51.678 90.599 53.55 ;
     RECT  90.599 51.678 90.635 51.696 ;
     RECT  90.599 52.452 90.635 53.55 ;
    LAYER M3 ;
     RECT  40.428 0.043 40.446 0.091 ;
     RECT  68.76 0.043 68.778 0.091 ;
     RECT  40.428 0.091 41.022 0.139 ;
     RECT  42.84 0.091 42.858 0.139 ;
     RECT  45.936 0.091 46.134 0.139 ;
     RECT  46.872 0.091 48.042 0.139 ;
     RECT  50.832 0.091 50.85 0.139 ;
     RECT  63.72 0.043 63.738 0.139 ;
     RECT  74.808 0.091 74.826 0.139 ;
     RECT  45.72 0.139 48.366 0.187 ;
     RECT  50.832 0.139 50.922 0.187 ;
     RECT  63.72 0.139 64.386 0.187 ;
     RECT  42.768 0.139 42.858 0.221 ;
     RECT  67.608 0.091 72.486 0.235 ;
     RECT  73.908 0.187 73.926 0.235 ;
     RECT  74.808 0.139 75.006 0.235 ;
     RECT  50.724 0.187 50.922 0.269 ;
     RECT  63.252 0.187 64.386 0.283 ;
     RECT  42.768 0.221 42.786 0.317 ;
     RECT  50.724 0.269 50.742 0.317 ;
     RECT  63.252 0.283 64.566 0.331 ;
     RECT  55.404 0.091 56.106 0.427 ;
     RECT  55.044 0.427 56.106 0.475 ;
     RECT  45.72 0.187 48.798 0.523 ;
     RECT  54.936 0.475 56.394 0.523 ;
     RECT  67.608 0.235 75.006 0.571 ;
     RECT  45.072 0.523 48.798 1.831 ;
     RECT  44.784 1.831 48.798 1.876 ;
     RECT  63.252 0.331 64.89 1.876 ;
     RECT  43.056 1.759 43.074 1.957 ;
     RECT  67.428 0.571 75.006 1.957 ;
     RECT  63.252 1.876 65.322 1.993 ;
     RECT  42.912 1.957 43.074 2.029 ;
     RECT  44.388 1.876 48.798 2.029 ;
     RECT  66.744 1.957 75.006 2.029 ;
     RECT  42.912 2.029 48.798 2.065 ;
     RECT  51.948 2.029 51.966 2.101 ;
     RECT  39.6 2.065 39.618 2.143 ;
     RECT  40.428 0.139 41.166 2.143 ;
     RECT  54.468 0.523 56.394 2.143 ;
     RECT  57.132 0.235 57.582 2.143 ;
     RECT  53.64 2.101 53.658 2.191 ;
     RECT  62.676 1.993 65.322 2.219 ;
     RECT  25.704 2.191 25.83 2.227 ;
     RECT  18.615 2.143 18.705 2.251 ;
     RECT  39.6 2.143 41.166 2.263 ;
     RECT  51.948 2.101 52.362 2.263 ;
     RECT  18.468 2.251 18.705 2.299 ;
     RECT  34.815 2.143 34.905 2.299 ;
     RECT  36.72 2.227 36.738 2.299 ;
     RECT  42.84 2.065 48.798 2.299 ;
     RECT  39.456 2.263 41.238 2.335 ;
     RECT  66.492 2.029 75.006 2.335 ;
     RECT  29.415 2.143 29.505 2.347 ;
     RECT  16.452 2.227 16.47 2.371 ;
     RECT  17.712 2.227 17.73 2.371 ;
     RECT  18.468 2.299 18.738 2.371 ;
     RECT  24.015 2.143 24.105 2.371 ;
     RECT  29.415 2.347 30.078 2.371 ;
     RECT  31.5 2.263 31.518 2.371 ;
     RECT  32.832 2.251 32.85 2.371 ;
     RECT  33.768 2.251 33.786 2.371 ;
     RECT  34.815 2.299 35.442 2.371 ;
     RECT  36.684 2.299 36.738 2.371 ;
     RECT  42.588 2.299 48.798 2.371 ;
     RECT  51.015 2.143 51.105 2.371 ;
     RECT  51.948 2.263 52.794 2.371 ;
     RECT  53.568 2.191 53.658 2.371 ;
     RECT  2.415 2.143 2.505 2.413 ;
     RECT  7.815 2.143 7.905 2.413 ;
     RECT  13.215 2.143 13.305 2.413 ;
     RECT  16.452 2.371 18.738 2.413 ;
     RECT  23.544 2.371 24.105 2.413 ;
     RECT  61.815 2.143 61.905 2.413 ;
     RECT  62.676 2.219 65.034 2.413 ;
     RECT  78.015 2.143 78.105 2.413 ;
     RECT  83.415 2.143 83.505 2.413 ;
     RECT  31.392 2.371 31.734 2.461 ;
     RECT  32.472 2.371 32.85 2.461 ;
     RECT  33.768 2.371 35.73 2.461 ;
     RECT  42.552 2.371 48.798 2.461 ;
     RECT  16.452 2.413 18.897 2.497 ;
     RECT  20.484 2.371 20.502 2.497 ;
     RECT  21.24 2.299 21.258 2.497 ;
     RECT  13.215 2.413 13.497 2.569 ;
     RECT  14.22 2.497 14.238 2.569 ;
     RECT  20.268 2.497 21.258 2.569 ;
     RECT  36.576 2.371 37.818 2.569 ;
     RECT  39.06 2.335 41.238 2.569 ;
     RECT  42.12 2.461 48.798 2.569 ;
     RECT  76.284 2.533 76.302 2.569 ;
     RECT  22.644 2.497 22.662 2.605 ;
     RECT  23.544 2.413 24.297 2.605 ;
     RECT  25.056 2.227 25.83 2.605 ;
     RECT  33.588 2.461 35.73 2.605 ;
     RECT  36.576 2.569 48.798 2.605 ;
     RECT  49.86 0.235 49.878 2.605 ;
     RECT  51.015 2.371 53.658 2.605 ;
     RECT  54.468 2.143 57.582 2.605 ;
     RECT  11.196 2.605 11.214 2.641 ;
     RECT  13.215 2.569 14.238 2.641 ;
     RECT  15.984 2.497 18.897 2.641 ;
     RECT  20.088 2.569 21.258 2.641 ;
     RECT  22.644 2.605 25.83 2.641 ;
     RECT  28.368 2.371 30.078 2.641 ;
     RECT  31.392 2.461 32.85 2.641 ;
     RECT  33.588 2.605 48.798 2.641 ;
     RECT  11.196 2.641 14.49 2.731 ;
     RECT  66.204 2.335 75.006 2.731 ;
     RECT  11.16 2.731 14.49 2.803 ;
     RECT  27.972 2.641 48.798 2.827 ;
     RECT  15.984 2.641 25.83 2.831 ;
     RECT  10.548 2.803 14.49 2.861 ;
     RECT  49.86 2.605 57.582 2.875 ;
     RECT  25.128 2.831 25.83 2.911 ;
     RECT  61.815 2.413 65.034 3.001 ;
     RECT  65.844 2.731 75.006 3.001 ;
     RECT  15.984 2.831 24.297 3.145 ;
     RECT  27.684 2.827 48.798 3.145 ;
     RECT  49.824 2.875 57.582 3.145 ;
     RECT  60.408 3.109 60.786 3.145 ;
     RECT  61.815 3.001 75.006 3.145 ;
     RECT  11.16 2.861 14.49 3.181 ;
     RECT  25.128 2.911 25.902 3.181 ;
     RECT  60.048 3.145 60.786 3.181 ;
     RECT  61.815 3.145 75.258 3.181 ;
     RECT  76.284 2.569 76.374 3.181 ;
     RECT  11.16 3.181 14.526 3.271 ;
     RECT  60.048 3.181 60.966 3.307 ;
     RECT  27.684 3.145 57.582 3.343 ;
     RECT  61.815 3.181 76.374 3.343 ;
     RECT  27.684 3.343 57.942 3.379 ;
     RECT  59.868 3.307 60.966 3.415 ;
     RECT  27.684 3.379 58.518 3.451 ;
     RECT  59.58 3.415 60.966 3.451 ;
     RECT  25.128 3.181 25.974 3.577 ;
     RECT  26.82 3.451 26.838 3.577 ;
     RECT  25.128 3.577 26.838 3.595 ;
     RECT  15.804 3.145 24.297 3.643 ;
     RECT  25.128 3.595 26.874 3.649 ;
     RECT  27.684 3.451 60.966 3.649 ;
     RECT  25.128 3.649 61.002 3.685 ;
     RECT  61.74 3.343 76.374 3.685 ;
     RECT  11.16 3.271 14.742 3.721 ;
     RECT  15.804 3.643 24.354 3.721 ;
     RECT  25.128 3.685 76.374 3.721 ;
     RECT  11.16 3.721 15.066 3.955 ;
     RECT  11.088 3.955 15.066 3.991 ;
     RECT  15.804 3.721 76.374 3.991 ;
     RECT  10.98 3.991 76.374 4.109 ;
     RECT  10.224 3.979 10.242 4.117 ;
     RECT  10.98 4.109 20.034 4.117 ;
     RECT  7.815 2.413 8.097 4.225 ;
     RECT  8.964 4.117 8.982 4.225 ;
     RECT  6.84 3.991 6.858 4.261 ;
     RECT  7.815 4.225 8.982 4.261 ;
     RECT  6.768 4.261 6.858 4.387 ;
     RECT  7.815 4.261 9.486 4.531 ;
     RECT  6.336 4.387 6.858 4.541 ;
     RECT  7.632 4.531 9.486 4.651 ;
     RECT  7.272 4.651 9.486 4.793 ;
     RECT  20.808 4.109 76.374 4.829 ;
     RECT  7.632 4.793 9.486 4.891 ;
     RECT  10.224 4.117 20.034 4.891 ;
     RECT  7.632 4.891 20.034 4.919 ;
     RECT  20.808 4.829 52.434 4.919 ;
     RECT  53.352 4.829 76.374 5.063 ;
     RECT  7.704 4.919 20.034 5.071 ;
     RECT  20.808 4.919 22.518 5.071 ;
     RECT  53.496 5.063 76.374 5.341 ;
     RECT  53.496 5.341 77.166 5.459 ;
     RECT  7.704 5.071 22.518 5.707 ;
     RECT  66.168 5.459 77.166 5.737 ;
     RECT  7.488 5.707 22.518 5.881 ;
     RECT  23.292 4.919 52.434 5.881 ;
     RECT  53.496 5.459 65.286 5.881 ;
     RECT  66.168 5.737 77.238 6.007 ;
     RECT  78.015 2.413 78.297 6.007 ;
     RECT  66.168 6.007 78.297 6.151 ;
     RECT  7.452 5.881 52.434 6.235 ;
     RECT  53.172 5.881 65.286 6.235 ;
     RECT  79.776 5.737 79.794 6.277 ;
     RECT  6.336 4.541 6.354 6.313 ;
     RECT  6.336 6.313 6.426 6.349 ;
     RECT  7.452 6.235 65.286 6.349 ;
     RECT  79.776 6.277 80.01 6.385 ;
     RECT  79.776 6.385 80.082 6.421 ;
     RECT  83.415 2.413 83.697 6.421 ;
     RECT  6.336 6.349 65.286 6.523 ;
     RECT  66.168 6.151 78.75 6.523 ;
     RECT  6.3 6.523 78.75 6.575 ;
     RECT  83.415 6.421 83.862 6.583 ;
     RECT  66.312 6.575 78.75 6.613 ;
     RECT  66.312 6.613 78.822 6.619 ;
     RECT  79.776 6.421 80.154 6.655 ;
     RECT  66.312 6.619 78.894 6.691 ;
     RECT  79.668 6.655 80.154 6.691 ;
     RECT  82.728 6.583 83.862 6.691 ;
     RECT  6.3 6.575 65.358 6.719 ;
     RECT  4.608 6.277 4.626 6.781 ;
     RECT  66.312 6.691 80.154 6.817 ;
     RECT  4.428 6.781 4.626 6.845 ;
     RECT  66.312 6.817 80.226 6.845 ;
     RECT  82.692 6.691 83.862 6.902 ;
     RECT  84.852 6.781 84.87 6.902 ;
     RECT  82.692 6.902 84.87 6.925 ;
     RECT  66.564 6.845 80.226 6.961 ;
     RECT  82.512 6.925 84.87 7.051 ;
     RECT  85.968 6.889 85.986 7.087 ;
     RECT  82.512 7.051 85.05 7.099 ;
     RECT  66.564 6.961 80.694 7.259 ;
     RECT  5.436 6.961 5.454 7.357 ;
     RECT  6.3 6.719 65.178 7.357 ;
     RECT  66.564 7.259 73.638 7.388 ;
     RECT  66.564 7.388 73.602 7.427 ;
     RECT  74.484 7.259 80.694 7.465 ;
     RECT  82.512 7.099 85.122 7.465 ;
     RECT  85.932 7.087 85.986 7.465 ;
     RECT  5.436 7.357 65.178 7.501 ;
     RECT  74.484 7.465 81.198 7.501 ;
     RECT  74.484 7.501 81.702 7.591 ;
     RECT  82.512 7.465 85.986 7.591 ;
     RECT  4.608 6.845 4.626 7.771 ;
     RECT  5.436 7.501 65.574 7.771 ;
     RECT  74.484 7.591 85.986 8.041 ;
     RECT  66.564 7.427 73.566 8.155 ;
     RECT  74.34 8.041 85.986 8.155 ;
     RECT  4.608 7.771 65.574 8.167 ;
     RECT  66.456 8.155 85.986 8.167 ;
     RECT  4.608 8.167 85.986 8.195 ;
     RECT  74.484 8.195 85.986 8.437 ;
     RECT  74.484 8.437 86.058 8.609 ;
     RECT  5.724 8.195 73.674 8.941 ;
     RECT  74.484 8.609 80.982 8.941 ;
     RECT  81.792 8.609 86.058 9.049 ;
     RECT  4.608 8.195 4.626 9.121 ;
     RECT  5.724 8.941 80.982 9.121 ;
     RECT  4.608 9.121 80.982 9.391 ;
     RECT  81.792 9.049 86.094 9.391 ;
     RECT  86.904 8.311 86.922 9.787 ;
     RECT  4.608 9.391 86.094 10.093 ;
     RECT  86.904 9.787 87.138 10.093 ;
     RECT  4.608 10.093 87.138 10.625 ;
     RECT  4.608 10.625 5.202 11.371 ;
     RECT  5.94 10.625 87.138 11.371 ;
     RECT  4.608 11.371 87.138 11.435 ;
     RECT  5.976 11.435 87.138 11.669 ;
     RECT  4.608 11.435 5.202 12.487 ;
     RECT  6.012 11.669 87.138 12.487 ;
     RECT  4.608 12.487 87.138 12.595 ;
     RECT  4.608 12.595 87.174 13.055 ;
     RECT  6.084 13.055 87.174 13.085 ;
     RECT  6.228 13.085 87.174 13.091 ;
     RECT  14.472 13.091 87.174 13.099 ;
     RECT  14.472 13.099 87.21 13.559 ;
     RECT  6.228 13.091 13.698 13.873 ;
     RECT  14.472 13.559 87.174 13.873 ;
     RECT  6.228 13.873 87.174 13.981 ;
     RECT  4.608 13.055 5.202 14.251 ;
     RECT  6.012 13.981 87.174 14.251 ;
     RECT  4.536 14.251 87.174 14.573 ;
     RECT  3.528 13.603 3.546 14.881 ;
     RECT  4.536 14.573 5.202 14.881 ;
     RECT  6.012 14.573 87.174 15.331 ;
     RECT  6.012 15.331 87.246 15.449 ;
     RECT  3.528 14.881 5.202 15.601 ;
     RECT  6.012 15.449 87.174 15.601 ;
     RECT  3.528 15.601 87.174 15.629 ;
     RECT  22.248 15.629 87.174 15.719 ;
     RECT  3.528 15.629 21.51 16.411 ;
     RECT  22.248 15.719 87.138 16.411 ;
     RECT  3.528 16.411 87.138 16.951 ;
     RECT  87.984 16.681 88.002 17.069 ;
     RECT  2.415 2.413 2.697 17.185 ;
     RECT  3.528 16.951 87.246 17.185 ;
     RECT  2.415 17.185 87.246 17.653 ;
     RECT  2.415 17.653 87.498 18.463 ;
     RECT  2.415 18.463 87.57 18.841 ;
     RECT  2.415 18.841 87.75 19.373 ;
     RECT  2.415 19.373 87.246 19.535 ;
     RECT  2.415 19.535 87.21 20.353 ;
     RECT  2.415 20.353 87.786 20.389 ;
     RECT  2.415 20.389 87.894 20.695 ;
     RECT  2.415 20.695 88.434 20.849 ;
     RECT  2.415 20.849 87.786 20.993 ;
     RECT  2.415 20.993 87.57 22.477 ;
     RECT  2.415 22.477 87.678 22.585 ;
     RECT  2.34 22.585 87.678 22.781 ;
     RECT  7.668 22.781 87.678 23.009 ;
     RECT  0.108 22.783 0.126 23.083 ;
     RECT  0.108 23.083 0.162 23.125 ;
     RECT  7.668 23.009 87.606 23.153 ;
     RECT  2.34 22.781 6.894 23.275 ;
     RECT  0.108 23.125 0.198 23.371 ;
     RECT  0.108 23.371 0.342 23.693 ;
     RECT  0.144 23.693 0.342 23.701 ;
     RECT  2.304 23.275 6.894 23.701 ;
     RECT  7.668 23.153 87.534 23.701 ;
     RECT  0.144 23.701 0.558 23.947 ;
     RECT  0.144 23.947 0.666 24.077 ;
     RECT  0.144 24.077 0.198 24.365 ;
     RECT  0.144 24.365 0.162 24.475 ;
     RECT  2.304 23.701 87.534 25.015 ;
     RECT  0.108 24.475 0.162 25.133 ;
     RECT  0.108 25.133 0.126 25.325 ;
     RECT  2.304 25.015 87.714 25.447 ;
     RECT  2.304 25.447 87.858 25.579 ;
     RECT  2.268 25.579 87.858 25.771 ;
     RECT  1.728 25.771 87.858 26.131 ;
     RECT  0.144 25.867 0.162 26.251 ;
     RECT  1.728 26.131 88.038 26.357 ;
     RECT  0.108 26.251 0.342 26.443 ;
     RECT  0.108 26.443 0.378 26.827 ;
     RECT  0.108 26.827 0.45 27.053 ;
     RECT  1.728 26.357 87.858 27.095 ;
     RECT  2.268 27.095 87.858 27.239 ;
     RECT  2.304 27.239 87.858 27.365 ;
     RECT  0.108 27.053 0.342 27.883 ;
     RECT  0.108 27.883 0.414 27.979 ;
     RECT  2.34 27.365 87.858 28.175 ;
     RECT  2.34 28.175 8.766 28.247 ;
     RECT  0.108 27.979 0.522 28.411 ;
     RECT  0.108 28.411 0.594 28.481 ;
     RECT  0.108 28.481 0.522 28.493 ;
     RECT  9.54 28.175 87.858 28.723 ;
     RECT  0.108 28.493 0.378 28.973 ;
     RECT  2.34 28.247 8.658 29.029 ;
     RECT  9.54 28.723 88.362 29.029 ;
     RECT  0.108 28.973 0.306 29.069 ;
     RECT  0.108 29.069 0.198 29.093 ;
     RECT  0.108 29.093 0.162 29.597 ;
     RECT  2.34 29.029 88.362 29.795 ;
     RECT  17.928 29.795 88.362 30.077 ;
     RECT  46.944 30.077 88.362 30.137 ;
     RECT  2.34 29.795 17.154 30.299 ;
     RECT  3.744 30.299 17.154 30.569 ;
     RECT  3.78 30.569 17.154 30.571 ;
     RECT  17.928 30.077 46.134 30.571 ;
     RECT  3.78 30.571 46.134 30.859 ;
     RECT  46.98 30.137 88.362 30.859 ;
     RECT  3.78 30.859 88.362 31.109 ;
     RECT  3.78 31.109 88.326 31.379 ;
     RECT  2.34 30.299 2.862 31.423 ;
     RECT  3.78 31.379 88.002 31.423 ;
     RECT  2.34 31.423 88.002 32.459 ;
     RECT  2.34 32.459 87.534 32.837 ;
     RECT  2.34 32.837 86.994 32.999 ;
     RECT  0.108 29.597 0.126 33.043 ;
     RECT  0.036 33.043 0.126 33.071 ;
     RECT  0.036 33.071 0.054 33.179 ;
     RECT  2.34 32.999 86.958 33.269 ;
     RECT  2.376 33.269 86.958 34.079 ;
     RECT  2.415 34.079 86.958 34.925 ;
     RECT  2.415 34.925 52.434 35.339 ;
     RECT  2.415 35.339 8.946 35.401 ;
     RECT  9.72 35.339 52.434 35.803 ;
     RECT  53.172 34.925 86.958 35.803 ;
     RECT  2.34 35.401 8.946 36.121 ;
     RECT  9.72 35.803 86.958 36.121 ;
     RECT  2.34 36.121 86.958 36.815 ;
     RECT  9.612 36.815 86.958 36.851 ;
     RECT  2.34 36.815 8.838 37.364 ;
     RECT  2.376 37.364 8.838 37.589 ;
     RECT  2.415 37.589 8.838 37.633 ;
     RECT  9.612 36.851 43.326 37.633 ;
     RECT  2.415 37.633 43.326 37.669 ;
     RECT  44.1 36.851 86.958 37.669 ;
     RECT  2.415 37.669 86.958 38.281 ;
     RECT  2.415 38.281 87.102 38.399 ;
     RECT  14.796 38.399 87.102 39.091 ;
     RECT  2.415 38.399 14.058 39.217 ;
     RECT  14.796 39.091 87.39 39.217 ;
     RECT  2.415 39.217 87.39 40.603 ;
     RECT  2.415 40.603 87.57 41.485 ;
     RECT  2.376 41.485 87.57 41.521 ;
     RECT  2.376 41.521 87.786 41.791 ;
     RECT  2.304 41.791 87.786 42.835 ;
     RECT  2.304 42.835 87.894 43.133 ;
     RECT  2.304 43.133 4.194 43.169 ;
     RECT  4.932 43.133 87.894 43.331 ;
     RECT  4.932 43.331 87.786 43.403 ;
     RECT  2.304 43.169 3.978 43.915 ;
     RECT  4.932 43.403 87.534 43.915 ;
     RECT  2.304 43.915 87.534 44.653 ;
     RECT  2.304 44.653 87.57 45.157 ;
     RECT  2.304 45.157 87.606 45.193 ;
     RECT  2.304 45.193 87.822 45.841 ;
     RECT  2.304 45.841 88.434 45.959 ;
     RECT  2.304 45.959 87.498 45.995 ;
     RECT  2.304 45.995 87.462 46.067 ;
     RECT  2.304 46.067 87.426 47.011 ;
     RECT  2.304 47.011 87.57 47.191 ;
     RECT  88.38 45.959 88.398 47.353 ;
     RECT  2.304 47.191 87.606 47.623 ;
     RECT  88.344 47.353 88.398 47.623 ;
     RECT  2.304 47.623 88.398 48.119 ;
     RECT  90.612 48.187 90.63 48.433 ;
     RECT  2.304 48.119 9.018 48.619 ;
     RECT  2.268 48.619 9.018 48.965 ;
     RECT  2.34 48.965 9.018 49.003 ;
     RECT  9.756 48.119 88.398 49.003 ;
     RECT  2.34 49.003 88.398 49.235 ;
     RECT  2.34 49.235 32.166 49.307 ;
     RECT  2.34 49.307 32.13 49.379 ;
     RECT  2.34 49.379 32.094 50.323 ;
     RECT  2.34 50.323 32.238 50.521 ;
     RECT  33.084 49.235 88.398 50.521 ;
     RECT  2.34 50.521 88.398 50.549 ;
     RECT  2.34 50.549 3.978 50.717 ;
     RECT  5.292 50.549 48.618 50.729 ;
     RECT  5.364 50.729 48.618 50.819 ;
     RECT  90.108 48.433 90.63 51.241 ;
     RECT  9.432 50.819 48.618 51.331 ;
     RECT  49.608 50.549 88.398 51.331 ;
     RECT  5.364 50.819 8.622 51.539 ;
     RECT  90.072 51.241 90.63 51.745 ;
     RECT  9.432 51.331 88.398 51.809 ;
     RECT  90.036 51.745 90.63 51.917 ;
     RECT  12.456 51.809 88.398 52.177 ;
     RECT  0.072 49.315 0.09 52.285 ;
     RECT  0.072 52.285 0.558 52.366 ;
     RECT  5.364 51.539 8.478 52.411 ;
     RECT  9.432 51.809 11.646 52.411 ;
     RECT  2.34 50.717 3.942 52.591 ;
     RECT  5.364 52.411 11.646 52.591 ;
     RECT  12.456 52.177 88.938 52.591 ;
     RECT  2.34 52.591 4.41 52.651 ;
     RECT  2.304 52.651 4.41 52.681 ;
     RECT  90.072 51.917 90.63 52.717 ;
     RECT  5.364 52.591 88.938 52.817 ;
     RECT  2.304 52.681 4.554 52.829 ;
     RECT  2.304 52.829 3.222 52.843 ;
     RECT  2.268 52.843 3.222 52.889 ;
     RECT  90.036 52.717 90.63 52.939 ;
     RECT  89.46 52.939 90.63 52.979 ;
     RECT  2.304 52.889 3.222 53.393 ;
     RECT  90.036 52.979 90.63 53.555 ;
     RECT  2.415 53.393 3.222 53.599 ;
     RECT  4.14 52.829 4.554 53.599 ;
     RECT  5.364 52.817 88.398 53.6 ;
     RECT  10.26 53.6 88.398 53.611 ;
     RECT  2.415 53.599 4.554 53.671 ;
     RECT  5.364 53.6 9.486 53.671 ;
     RECT  0.036 52.366 0.558 53.837 ;
     RECT  90.036 53.555 90.558 53.837 ;
     RECT  10.26 53.611 88.902 53.869 ;
     RECT  10.26 53.869 88.938 53.941 ;
     RECT  90.036 53.837 90.162 53.941 ;
     RECT  10.26 53.941 90.162 54.029 ;
     RECT  2.415 53.671 9.486 54.373 ;
     RECT  10.26 54.029 90.09 54.373 ;
     RECT  2.415 54.373 90.09 54.571 ;
     RECT  2.304 54.571 90.09 54.608 ;
     RECT  0.036 53.837 0.198 54.859 ;
     RECT  2.412 54.608 90.09 54.977 ;
     RECT  88.884 54.977 90.09 55.175 ;
     RECT  88.884 55.175 88.902 55.247 ;
     RECT  2.412 54.977 87.858 55.445 ;
     RECT  0.036 54.859 0.342 55.517 ;
     RECT  90.072 55.175 90.09 55.553 ;
     RECT  0.036 55.517 0.126 55.679 ;
     RECT  2.415 55.445 87.858 55.715 ;
     RECT  2.415 55.715 87.246 55.859 ;
     RECT  0.036 55.679 0.054 56.057 ;
     RECT  2.415 55.859 86.922 56.371 ;
     RECT  2.376 56.371 86.922 57.181 ;
     RECT  2.376 57.181 87.066 57.407 ;
     RECT  2.376 57.407 86.922 57.569 ;
     RECT  87.804 57.307 87.822 57.569 ;
     RECT  2.415 57.569 86.922 58.415 ;
     RECT  2.415 58.415 86.454 58.649 ;
     RECT  87.372 58.531 87.39 58.649 ;
     RECT  2.415 58.649 86.274 59.189 ;
     RECT  2.415 59.189 85.302 59.267 ;
     RECT  2.415 59.267 85.05 60.151 ;
     RECT  2.376 60.151 85.518 60.413 ;
     RECT  2.415 60.413 85.518 60.575 ;
     RECT  2.415 60.575 85.482 60.683 ;
     RECT  2.415 60.683 85.302 62.537 ;
     RECT  2.415 62.537 85.23 63.851 ;
     RECT  77.004 63.851 85.23 64.661 ;
     RECT  77.004 64.661 85.014 64.769 ;
     RECT  2.415 63.851 76.194 64.975 ;
     RECT  2.415 64.975 76.266 65.821 ;
     RECT  77.004 64.769 84.906 65.821 ;
     RECT  2.415 65.821 84.906 66.325 ;
     RECT  2.415 66.325 84.942 66.479 ;
     RECT  2.415 66.479 84.906 66.515 ;
     RECT  2.415 66.515 33.174 66.821 ;
     RECT  0.036 66.595 0.054 66.865 ;
     RECT  33.912 66.515 84.906 67.181 ;
     RECT  33.912 67.181 82.314 67.199 ;
     RECT  83.376 67.181 84.906 67.289 ;
     RECT  0.036 66.865 0.126 67.405 ;
     RECT  83.415 67.289 84.906 67.595 ;
     RECT  2.415 66.821 33.066 67.603 ;
     RECT  2.415 67.603 33.102 67.675 ;
     RECT  33.912 67.199 82.062 67.675 ;
     RECT  2.415 67.675 82.062 67.829 ;
     RECT  2.415 67.829 81.774 67.865 ;
     RECT  2.415 67.865 80.478 67.981 ;
     RECT  0.036 67.405 0.162 68.009 ;
     RECT  81.612 67.865 81.774 68.009 ;
     RECT  83.415 67.595 84.294 68.009 ;
     RECT  83.415 68.009 84.114 68.099 ;
     RECT  2.304 67.981 80.478 68.171 ;
     RECT  2.304 68.171 80.226 68.369 ;
     RECT  2.304 68.369 80.118 68.377 ;
     RECT  2.232 68.377 80.118 68.381 ;
     RECT  0.108 68.009 0.162 68.429 ;
     RECT  2.232 68.381 67.806 68.477 ;
     RECT  0.144 68.429 0.162 68.525 ;
     RECT  68.544 68.381 80.118 68.639 ;
     RECT  2.268 68.477 67.806 68.909 ;
     RECT  68.544 68.639 80.082 69.251 ;
     RECT  68.544 69.251 78.786 69.449 ;
     RECT  79.704 69.251 80.082 69.449 ;
     RECT  79.704 69.449 80.01 69.485 ;
     RECT  12.672 68.909 67.806 69.601 ;
     RECT  68.544 69.449 78.297 69.601 ;
     RECT  0.144 69.307 0.162 69.643 ;
     RECT  12.672 69.601 78.297 69.719 ;
     RECT  0.144 69.643 0.306 69.821 ;
     RECT  69.156 69.719 72.897 69.863 ;
     RECT  2.268 68.909 11.934 69.871 ;
     RECT  12.672 69.719 68.31 69.871 ;
     RECT  69.156 69.863 70.326 69.989 ;
     RECT  73.728 69.719 75.726 69.989 ;
     RECT  76.86 69.719 78.297 69.989 ;
     RECT  73.728 69.989 73.746 70.025 ;
     RECT  74.88 69.989 75.726 70.025 ;
     RECT  2.268 69.871 68.31 70.157 ;
     RECT  69.156 69.989 69.39 70.157 ;
     RECT  75.708 70.025 75.726 70.157 ;
     RECT  76.86 69.989 76.878 70.157 ;
     RECT  2.268 70.157 67.806 70.253 ;
     RECT  71.28 69.863 72.897 70.259 ;
     RECT  2.304 70.253 67.806 70.295 ;
     RECT  71.28 70.259 71.298 70.295 ;
     RECT  72.18 70.259 72.897 70.403 ;
     RECT  0.144 69.821 0.198 70.411 ;
     RECT  2.304 70.295 3.078 70.565 ;
     RECT  69.156 70.157 69.174 70.645 ;
     RECT  69.012 70.645 69.174 70.673 ;
     RECT  0.108 70.411 0.198 70.699 ;
     RECT  2.415 70.565 3.078 70.799 ;
     RECT  0.108 70.699 0.234 70.877 ;
     RECT  3.996 70.295 67.806 71.177 ;
     RECT  0.108 70.877 0.126 71.249 ;
     RECT  3.996 71.177 67.734 71.311 ;
     RECT  3.888 71.311 67.734 71.339 ;
     RECT  3.888 71.339 4.59 71.357 ;
     RECT  5.616 71.339 67.734 71.483 ;
     RECT  3.996 71.357 4.59 71.519 ;
     RECT  4.032 71.519 4.05 71.717 ;
     RECT  5.868 71.483 67.734 71.789 ;
     RECT  5.868 71.789 67.497 72.023 ;
     RECT  6.264 72.023 67.497 72.149 ;
     RECT  6.264 72.149 6.642 72.293 ;
     RECT  7.38 72.149 67.497 72.329 ;
     RECT  7.632 72.329 67.497 72.689 ;
     RECT  6.264 72.293 6.318 72.725 ;
     RECT  7.668 72.689 67.497 72.725 ;
     RECT  6.264 72.725 6.282 72.797 ;
     RECT  69.012 70.673 69.03 72.869 ;
     RECT  7.668 72.725 11.754 72.959 ;
     RECT  12.528 72.725 67.497 72.959 ;
     RECT  12.528 72.959 66.294 72.995 ;
     RECT  9 72.959 11.754 73.651 ;
     RECT  12.528 72.995 66.15 73.651 ;
     RECT  9 73.651 66.15 73.679 ;
     RECT  7.815 72.959 8.262 73.885 ;
     RECT  9 73.679 14.634 73.885 ;
     RECT  15.444 73.679 66.15 74.147 ;
     RECT  15.444 74.147 66.078 74.381 ;
     RECT  7.815 73.885 14.634 74.425 ;
     RECT  15.444 74.381 65.214 74.425 ;
     RECT  66.06 74.381 66.078 74.453 ;
     RECT  7.815 74.425 65.214 74.579 ;
     RECT  15.552 74.579 64.71 74.651 ;
     RECT  67.032 72.959 67.497 75.029 ;
     RECT  19.908 74.651 64.71 75.155 ;
     RECT  8.892 74.579 14.634 75.191 ;
     RECT  15.552 74.651 18.954 75.191 ;
     RECT  9.828 75.191 14.634 75.227 ;
     RECT  8.892 75.191 8.91 75.389 ;
     RECT  9.828 75.227 10.026 75.389 ;
     RECT  10.764 75.227 14.634 75.389 ;
     RECT  20.52 75.155 64.71 75.389 ;
     RECT  9.828 75.389 9.846 75.395 ;
     RECT  11.124 75.389 14.634 75.505 ;
     RECT  15.552 75.191 18.897 75.505 ;
     RECT  11.124 75.505 18.897 75.659 ;
     RECT  11.124 75.659 17.118 75.731 ;
     RECT  15.156 75.731 17.118 75.869 ;
     RECT  11.124 75.731 14.238 75.929 ;
     RECT  15.156 75.869 16.83 75.929 ;
     RECT  18.036 75.659 18.897 75.929 ;
     RECT  20.52 75.389 64.494 75.965 ;
     RECT  11.916 75.929 13.497 76.073 ;
     RECT  15.192 75.929 16.83 76.073 ;
     RECT  18.108 75.929 18.897 76.073 ;
     RECT  11.916 76.073 12.078 76.109 ;
     RECT  15.876 76.073 16.83 76.109 ;
     RECT  18.576 76.073 18.897 76.109 ;
     RECT  11.916 76.109 11.934 76.199 ;
     RECT  15.876 76.109 16.074 76.199 ;
     RECT  16.812 76.109 16.83 76.199 ;
     RECT  20.664 75.965 64.494 76.235 ;
     RECT  21.312 76.235 64.494 76.307 ;
     RECT  21.312 76.307 27.846 76.343 ;
     RECT  28.692 76.307 64.494 76.541 ;
     RECT  13.068 76.073 13.497 76.577 ;
     RECT  21.312 76.343 27.63 76.613 ;
     RECT  32.58 76.541 64.494 76.711 ;
     RECT  32.58 76.711 64.53 76.855 ;
     RECT  32.58 76.855 64.602 77.009 ;
     RECT  28.692 76.541 31.842 77.161 ;
     RECT  32.58 77.009 64.458 77.357 ;
     RECT  21.996 76.613 27.63 77.431 ;
     RECT  28.404 77.161 31.842 77.431 ;
     RECT  21.996 77.431 31.842 77.549 ;
     RECT  33.264 77.357 64.458 77.585 ;
     RECT  28.44 77.549 31.842 77.791 ;
     RECT  34.704 77.585 64.458 77.791 ;
     RECT  33.264 77.585 33.966 77.837 ;
     RECT  34.704 77.791 64.53 77.927 ;
     RECT  34.704 77.927 64.278 78.089 ;
     RECT  65.016 77.935 65.034 78.089 ;
     RECT  23.22 77.549 27.702 78.269 ;
     RECT  33.48 77.837 33.966 78.331 ;
     RECT  34.704 78.089 64.206 78.331 ;
     RECT  33.48 78.331 64.206 78.359 ;
     RECT  33.516 78.359 64.206 78.395 ;
     RECT  28.44 77.791 32.238 78.431 ;
     RECT  23.364 78.269 27.702 78.511 ;
     RECT  28.44 78.431 32.166 78.511 ;
     RECT  23.364 78.511 32.166 78.629 ;
     RECT  33.516 78.395 33.966 78.665 ;
     RECT  23.364 78.629 31.914 78.701 ;
     RECT  34.704 78.395 64.206 78.899 ;
     RECT  23.364 78.701 31.878 78.935 ;
     RECT  33.516 78.665 33.894 78.935 ;
     RECT  23.724 78.935 31.878 79.169 ;
     RECT  23.724 79.169 24.297 79.205 ;
     RECT  25.524 79.169 31.878 79.229 ;
     RECT  25.668 79.229 31.878 79.313 ;
     RECT  26.028 79.313 31.878 79.349 ;
     RECT  26.208 79.349 26.982 79.439 ;
     RECT  34.815 78.899 64.206 79.439 ;
     RECT  26.208 79.439 26.91 79.475 ;
     RECT  26.208 79.475 26.226 79.547 ;
     RECT  27.864 79.349 29.697 79.547 ;
     RECT  54.468 79.439 64.206 79.619 ;
     RECT  28.476 79.547 29.697 79.709 ;
     RECT  30.564 79.349 31.878 79.709 ;
     RECT  34.815 79.439 53.694 79.781 ;
     RECT  30.564 79.709 30.582 79.853 ;
     RECT  28.512 79.709 28.53 79.979 ;
     RECT  36 79.781 53.694 80.051 ;
     RECT  54.576 79.619 64.206 80.249 ;
     RECT  36.144 80.051 53.694 80.789 ;
     RECT  52.236 80.789 53.694 80.825 ;
     RECT  52.704 80.825 53.694 80.923 ;
     RECT  54.576 80.249 59.31 80.923 ;
     RECT  36.144 80.789 51.297 81.019 ;
     RECT  36 81.019 51.297 81.059 ;
     RECT  52.704 80.923 59.31 81.067 ;
     RECT  60.084 80.249 64.206 81.067 ;
     RECT  36.756 81.059 51.297 81.095 ;
     RECT  52.704 81.067 64.206 81.095 ;
     RECT  36.756 81.095 37.494 81.329 ;
     RECT  54.324 81.095 64.206 81.329 ;
     RECT  33.876 78.935 33.894 81.437 ;
     RECT  36 81.059 36.018 81.473 ;
     RECT  54.612 81.329 64.206 81.473 ;
     RECT  54.828 81.473 63.954 81.509 ;
     RECT  38.592 81.095 51.297 81.599 ;
     RECT  62.892 81.509 63.954 81.599 ;
     RECT  38.592 81.599 39.114 81.779 ;
     RECT  38.592 81.779 38.61 81.869 ;
     RECT  54.828 81.509 62.154 81.869 ;
     RECT  52.704 81.095 53.154 81.905 ;
     RECT  54.828 81.869 62.097 81.977 ;
     RECT  39.996 81.599 51.297 82.049 ;
     RECT  54.828 81.977 60.93 82.049 ;
     RECT  54.864 82.049 60.93 82.139 ;
     RECT  63 81.599 63.954 82.139 ;
     RECT  54.864 82.139 57.834 82.175 ;
     RECT  63 82.139 63.018 82.175 ;
     RECT  54.864 82.175 56.697 82.409 ;
     RECT  58.68 82.139 58.986 82.409 ;
     RECT  59.832 82.139 60.93 82.409 ;
     RECT  57.816 82.175 57.834 82.553 ;
     RECT  59.832 82.409 59.85 82.553 ;
     RECT  54.864 82.409 55.494 82.679 ;
     RECT  40.215 82.049 51.297 83.255 ;
     RECT  44.568 83.255 51.297 83.525 ;
     RECT  40.215 83.255 43.794 83.597 ;
     RECT  40.215 83.597 43.65 83.633 ;
     RECT  41.688 83.633 43.65 83.669 ;
     RECT  44.604 83.525 49.014 83.669 ;
     RECT  44.604 83.669 48.906 83.759 ;
     RECT  42.048 83.669 43.65 83.795 ;
     RECT  44.604 83.759 48.546 83.795 ;
     RECT  49.824 83.525 51.297 83.795 ;
     RECT  44.604 83.795 45.897 84.029 ;
     RECT  46.944 83.795 48.546 84.029 ;
     RECT  42.768 83.795 43.65 84.065 ;
     RECT  50.004 83.795 51.297 84.065 ;
     RECT  46.944 84.029 46.962 84.101 ;
     RECT  43.632 84.065 43.65 84.209 ;
     RECT  50.4 84.065 51.297 84.209 ;
     RECT  52.704 81.905 52.722 87.809 ;
     RECT  51.015 84.209 51.297 87.961 ;
     RECT  2.415 70.799 2.697 88.307 ;
     RECT  7.815 74.579 8.097 88.307 ;
     RECT  13.215 76.577 13.497 88.307 ;
     RECT  18.615 76.109 18.897 88.307 ;
     RECT  24.015 79.205 24.297 88.307 ;
     RECT  29.415 79.709 29.697 88.307 ;
     RECT  34.815 79.781 35.097 88.307 ;
     RECT  40.215 83.633 40.497 88.307 ;
     RECT  45.615 84.029 45.897 88.307 ;
     RECT  50.508 87.961 51.297 88.307 ;
     RECT  56.415 82.409 56.697 88.307 ;
     RECT  61.815 81.977 62.097 88.307 ;
     RECT  67.215 75.029 67.497 88.307 ;
     RECT  72.615 70.403 72.897 88.307 ;
     RECT  78.015 69.989 78.297 88.307 ;
     RECT  83.415 68.099 83.697 88.307 ;
     RECT  50.508 88.307 51.105 88.397 ;
     RECT  2.415 88.307 2.505 88.577 ;
     RECT  7.815 88.307 7.905 88.577 ;
     RECT  13.215 88.307 13.305 88.577 ;
     RECT  18.615 88.307 18.705 88.577 ;
     RECT  24.015 88.307 24.105 88.577 ;
     RECT  29.415 88.307 29.505 88.577 ;
     RECT  34.815 88.307 34.905 88.577 ;
     RECT  40.215 88.307 40.305 88.577 ;
     RECT  45.615 88.307 45.705 88.577 ;
     RECT  51.015 88.397 51.105 88.577 ;
     RECT  56.415 88.307 56.505 88.577 ;
     RECT  61.815 88.307 61.905 88.577 ;
     RECT  67.215 88.307 67.305 88.577 ;
     RECT  72.615 88.307 72.705 88.577 ;
     RECT  78.015 88.307 78.105 88.577 ;
     RECT  83.415 88.307 83.505 88.577 ;
    LAYER M4 ;
     RECT  0.06 23.184 0.133 29.256 ;
     RECT  0.06 52.368 0.137 55.368 ;
     RECT  0.137 52.464 0.169 55.368 ;
     RECT  0.06 67.728 0.205 70.728 ;
     RECT  0.205 67.728 0.227 70.872 ;
     RECT  0.169 52.464 0.569 55.512 ;
     RECT  0.181 44.112 2.329 44.136 ;
     RECT  2.329 47.136 2.365 47.16 ;
     RECT  0.133 23.088 2.408 29.592 ;
     RECT  2.329 43.872 2.408 44.136 ;
     RECT  2.365 45.456 2.408 45.48 ;
     RECT  2.365 47.136 2.408 47.352 ;
     RECT  2.365 49.872 2.408 49.896 ;
     RECT  0.569 52.656 2.408 55.512 ;
     RECT  0.227 67.824 2.408 70.872 ;
     RECT  2.408 2.148 2.512 88.572 ;
     RECT  2.512 2.418 2.704 88.302 ;
     RECT  2.704 52.752 2.839 55.848 ;
     RECT  2.704 43.872 2.867 44.136 ;
     RECT  2.704 67.392 2.909 67.416 ;
     RECT  2.704 23.088 3.089 30.216 ;
     RECT  2.704 45.456 3.161 47.352 ;
     RECT  2.704 34.32 3.269 35.928 ;
     RECT  2.867 44.016 3.413 44.136 ;
     RECT  3.161 45.456 3.449 47.16 ;
     RECT  3.089 26.304 3.593 30.216 ;
     RECT  2.704 42.768 3.593 42.792 ;
     RECT  2.704 61.584 3.593 61.608 ;
     RECT  2.839 52.8 3.629 55.848 ;
     RECT  2.704 33.168 3.697 33.192 ;
     RECT  3.269 34.32 3.697 34.488 ;
     RECT  2.704 48.96 3.697 49.896 ;
     RECT  2.704 21.648 3.805 21.672 ;
     RECT  3.089 23.088 3.805 25.32 ;
     RECT  3.269 35.712 3.805 35.928 ;
     RECT  2.704 37.056 3.805 37.08 ;
     RECT  2.704 68.544 3.877 70.872 ;
     RECT  3.805 21.648 3.881 25.32 ;
     RECT  3.697 48.96 3.905 50.136 ;
     RECT  3.905 48.96 3.913 50.184 ;
     RECT  3.769 30.768 3.917 30.792 ;
     RECT  3.913 48.96 3.949 50.28 ;
     RECT  2.704 39.888 3.953 39.912 ;
     RECT  3.949 48.288 3.971 50.712 ;
     RECT  2.704 31.824 3.989 31.896 ;
     RECT  3.877 68.544 4.201 71.352 ;
     RECT  3.629 52.848 4.205 55.848 ;
     RECT  2.704 62.736 4.22 64.44 ;
     RECT  2.704 65.808 4.22 66.408 ;
     RECT  3.881 22.176 4.273 25.32 ;
     RECT  3.593 26.304 4.273 29.496 ;
     RECT  4.22 62.736 4.277 66.408 ;
     RECT  4.277 62.736 4.307 64.872 ;
     RECT  2.704 57.168 4.345 57.192 ;
     RECT  2.704 58.656 4.345 58.68 ;
     RECT  2.704 41.04 4.381 41.592 ;
     RECT  4.345 57.168 4.381 58.68 ;
     RECT  3.971 48.288 4.385 48.984 ;
     RECT  3.989 31.824 4.453 31.848 ;
     RECT  2.704 38.256 4.453 38.28 ;
     RECT  3.413 44.112 4.453 44.136 ;
     RECT  3.449 45.84 4.453 47.16 ;
     RECT  4.385 48.288 4.453 48.312 ;
     RECT  4.381 57.024 4.457 58.68 ;
     RECT  4.457 57.024 4.547 58.392 ;
     RECT  4.381 41.04 4.561 41.64 ;
     RECT  4.273 22.176 4.565 29.496 ;
     RECT  4.565 22.176 4.637 24.264 ;
     RECT  4.453 38.256 4.732 39.24 ;
     RECT  4.669 60 4.741 60.024 ;
     RECT  3.697 33.168 4.748 34.488 ;
     RECT  4.453 45.84 4.813 48.312 ;
     RECT  2.704 72.768 4.885 72.792 ;
     RECT  4.307 62.736 4.889 64.776 ;
     RECT  4.201 67.776 4.931 71.352 ;
     RECT  4.748 33.024 4.933 34.488 ;
     RECT  3.805 35.712 4.933 37.08 ;
     RECT  4.933 33.024 4.979 37.08 ;
     RECT  4.547 57.168 4.997 58.392 ;
     RECT  4.885 42.768 5.036 42.792 ;
     RECT  4.453 43.92 5.036 44.136 ;
     RECT  4.201 21.12 5.065 21.144 ;
     RECT  4.561 40.416 5.077 41.64 ;
     RECT  5.036 42.768 5.077 44.136 ;
     RECT  4.277 66.384 5.077 66.408 ;
     RECT  4.931 67.776 5.077 70.872 ;
     RECT  4.205 53.088 5.137 55.848 ;
     RECT  4.453 31.248 5.173 31.848 ;
     RECT  5.077 40.416 5.249 44.136 ;
     RECT  3.971 50.112 5.321 50.712 ;
     RECT  4.889 62.736 5.324 63.864 ;
     RECT  5.324 62.352 5.411 63.864 ;
     RECT  4.633 17.616 5.425 17.64 ;
     RECT  5.137 53.088 5.461 56.088 ;
     RECT  5.461 52.848 5.497 56.088 ;
     RECT  5.249 42.768 5.533 44.136 ;
     RECT  4.813 45.792 5.533 48.312 ;
     RECT  4.732 39.216 5.537 39.24 ;
     RECT  4.997 57.648 5.573 58.392 ;
     RECT  5.173 31.248 5.605 31.992 ;
     RECT  4.979 33.024 5.605 36.504 ;
     RECT  5.077 66.384 5.609 70.872 ;
     RECT  4.565 25.68 5.641 29.496 ;
     RECT  5.533 42.768 5.645 48.312 ;
     RECT  5.533 19.344 5.677 19.368 ;
     RECT  5.065 21.12 5.677 21.768 ;
     RECT  5.605 31.248 5.681 36.504 ;
     RECT  5.641 25.44 5.713 29.496 ;
     RECT  5.609 66.384 5.713 66.408 ;
     RECT  5.573 57.648 5.717 58.104 ;
     RECT  5.677 19.344 5.749 21.768 ;
     RECT  4.637 22.752 5.749 24.264 ;
     RECT  5.321 50.112 5.749 50.136 ;
     RECT  5.681 36.48 5.753 36.504 ;
     RECT  4.741 11.376 5.789 11.4 ;
     RECT  4.849 14.256 5.821 14.28 ;
     RECT  5.713 25.44 5.821 30.168 ;
     RECT  5.681 31.248 5.821 35.064 ;
     RECT  5.749 49.344 5.825 50.136 ;
     RECT  5.497 52.224 5.857 56.088 ;
     RECT  5.821 14.256 5.861 14.568 ;
     RECT  4.993 9.216 5.897 9.24 ;
     RECT  5.821 25.44 5.933 35.064 ;
     RECT  5.749 19.344 5.965 24.264 ;
     RECT  5.933 25.44 5.965 32.472 ;
     RECT  5.965 19.344 5.969 32.472 ;
     RECT  5.933 33.552 6.005 35.064 ;
     RECT  5.609 67.536 6.037 70.872 ;
     RECT  4.885 72.384 6.037 72.792 ;
     RECT  5.425 17.616 6.073 17.88 ;
     RECT  6.073 17.088 6.181 17.88 ;
     RECT  5.249 40.416 6.185 41.64 ;
     RECT  4.741 60 6.217 60.408 ;
     RECT  5.645 43.056 6.221 48.312 ;
     RECT  4.417 6.816 6.289 6.84 ;
     RECT  6.289 6.528 6.329 6.84 ;
     RECT  5.411 62.544 6.397 63.864 ;
     RECT  6.38 15.888 6.421 15.912 ;
     RECT  6.217 59.28 6.473 60.408 ;
     RECT  6.473 59.28 6.509 59.304 ;
     RECT  5.857 52.224 6.541 56.424 ;
     RECT  6.397 62.544 6.581 64.056 ;
     RECT  5.717 57.648 6.685 57.672 ;
     RECT  6.649 58.656 6.685 58.68 ;
     RECT  6.421 15.696 6.721 15.912 ;
     RECT  6.181 16.896 6.721 17.928 ;
     RECT  6.581 64.032 6.721 64.056 ;
     RECT  6.649 38.4 6.757 38.424 ;
     RECT  6.541 51.888 6.757 56.424 ;
     RECT  6.685 57.648 6.757 58.68 ;
     RECT  5.857 8.016 6.785 8.04 ;
     RECT  6.757 37.488 6.793 38.424 ;
     RECT  6.185 40.416 6.793 41.4 ;
     RECT  6.329 6.528 6.805 6.552 ;
     RECT  6.721 15.696 6.833 17.928 ;
     RECT  6.785 7.824 6.865 8.04 ;
     RECT  5.825 49.344 7.009 49.416 ;
     RECT  5.713 66.144 7.153 66.408 ;
     RECT  6.037 67.536 7.153 72.792 ;
     RECT  6.221 43.056 7.225 47.832 ;
     RECT  7.009 49.344 7.225 50.088 ;
     RECT  6.613 4.512 7.261 4.536 ;
     RECT  5.861 14.544 7.333 14.568 ;
     RECT  6.805 5.712 7.369 6.552 ;
     RECT  6.865 7.728 7.369 8.04 ;
     RECT  5.969 31.68 7.369 32.472 ;
     RECT  6.005 33.552 7.369 34.92 ;
     RECT  7.333 14.544 7.405 14.712 ;
     RECT  6.833 15.696 7.405 16.008 ;
     RECT  7.225 43.056 7.477 50.088 ;
     RECT  6.757 51.888 7.477 58.68 ;
     RECT  7.405 14.544 7.657 16.008 ;
     RECT  7.477 51.456 7.669 58.68 ;
     RECT  6.613 9.792 7.693 9.816 ;
     RECT  7.369 5.712 7.729 8.04 ;
     RECT  7.261 4.512 7.808 4.68 ;
     RECT  7.729 5.712 7.808 8.184 ;
     RECT  7.693 9.6 7.808 9.816 ;
     RECT  6.073 13.056 7.808 13.08 ;
     RECT  7.657 14.496 7.808 16.008 ;
     RECT  6.833 17.088 7.808 17.928 ;
     RECT  5.969 19.344 7.808 30.6 ;
     RECT  7.369 31.68 7.808 34.92 ;
     RECT  6.793 36.096 7.808 38.424 ;
     RECT  6.793 39.888 7.808 41.4 ;
     RECT  7.477 43.056 7.808 50.136 ;
     RECT  7.669 51.36 7.808 58.68 ;
     RECT  6.473 60.384 7.808 60.408 ;
     RECT  6.581 62.544 7.808 62.568 ;
     RECT  6.721 64.032 7.808 64.392 ;
     RECT  7.153 66.144 7.808 72.792 ;
     RECT  7.808 2.148 7.912 88.572 ;
     RECT  7.912 2.418 8.104 88.302 ;
     RECT  8.104 22.752 8.165 29.592 ;
     RECT  8.104 9.6 8.273 9.624 ;
     RECT  8.104 60.576 8.345 62.76 ;
     RECT  8.104 12.912 8.387 13.656 ;
     RECT  8.345 60.768 8.579 62.76 ;
     RECT  8.104 31.392 8.597 36.648 ;
     RECT  8.104 45.792 8.597 59.4 ;
     RECT  8.104 43.056 8.705 44.136 ;
     RECT  8.597 32.928 8.849 36.12 ;
     RECT  8.104 6.384 8.921 7.752 ;
     RECT  8.705 43.056 8.921 43.08 ;
     RECT  8.104 65.424 8.921 75.384 ;
     RECT  8.597 45.792 9.029 57 ;
     RECT  8.597 31.392 9.097 31.896 ;
     RECT  9.029 45.792 9.097 47.832 ;
     RECT  8.104 17.088 9.133 18.264 ;
     RECT  8.579 62.016 9.205 62.76 ;
     RECT  8.104 63.792 9.205 63.816 ;
     RECT  8.921 7.44 9.209 7.752 ;
     RECT  8.104 14.688 9.209 15.576 ;
     RECT  8.579 60.768 9.209 60.792 ;
     RECT  9.068 9.648 9.241 9.672 ;
     RECT  9.205 10.848 9.241 10.872 ;
     RECT  8.104 37.872 9.241 39.336 ;
     RECT  8.104 20.016 9.245 21.144 ;
     RECT  9.029 49.008 9.245 57 ;
     RECT  9.209 15.36 9.277 15.576 ;
     RECT  9.133 16.992 9.277 18.264 ;
     RECT  9.245 20.016 9.277 21 ;
     RECT  9.241 9.648 9.292 10.872 ;
     RECT  9.241 37.68 9.349 39.336 ;
     RECT  8.849 32.928 9.353 35.88 ;
     RECT  9.277 16.992 9.385 21 ;
     RECT  8.597 58.128 9.389 59.4 ;
     RECT  9.353 34.896 9.395 35.88 ;
     RECT  8.387 13.152 9.421 13.656 ;
     RECT  8.165 22.848 9.421 29.592 ;
     RECT  9.097 30.816 9.421 31.896 ;
     RECT  9.385 16.944 9.425 21 ;
     RECT  8.705 44.112 9.457 44.136 ;
     RECT  9.097 45.408 9.457 47.832 ;
     RECT  9.277 15.36 9.497 15.96 ;
     RECT  9.421 22.848 9.565 31.896 ;
     RECT  9.353 32.928 9.565 33.864 ;
     RECT  8.104 40.56 9.565 41.64 ;
     RECT  9.349 37.632 9.601 39.336 ;
     RECT  9.425 16.944 9.605 18.264 ;
     RECT  9.565 22.848 9.605 33.864 ;
     RECT  9.395 35.136 9.605 35.88 ;
     RECT  9.209 7.728 9.637 7.752 ;
     RECT  9.292 9.648 9.637 10.152 ;
     RECT  9.601 37.632 9.637 39.384 ;
     RECT  8.104 4.368 9.713 4.92 ;
     RECT  9.389 58.176 9.749 59.4 ;
     RECT  9.457 44.112 9.781 47.832 ;
     RECT  8.921 6.384 9.821 6.408 ;
     RECT  9.605 22.848 9.857 32.52 ;
     RECT  9.421 13.152 9.877 14.328 ;
     RECT  9.877 13.056 9.884 14.328 ;
     RECT  9.749 58.656 9.889 59.4 ;
     RECT  9.565 40.56 9.961 42.36 ;
     RECT  9.637 7.728 9.971 10.152 ;
     RECT  9.205 62.016 10.033 63.816 ;
     RECT  9.497 15.36 10.073 15.576 ;
     RECT  9.961 40.56 10.073 42.648 ;
     RECT  9.781 43.872 10.105 47.832 ;
     RECT  9.245 49.008 10.105 56.904 ;
     RECT  9.884 12.72 10.115 14.328 ;
     RECT  8.921 65.424 10.145 74.136 ;
     RECT  9.925 5.088 10.177 5.112 ;
     RECT  9.857 22.848 10.177 24.456 ;
     RECT  10.177 5.088 10.253 5.88 ;
     RECT  10.115 12.72 10.259 14.04 ;
     RECT  10.073 15.408 10.259 15.576 ;
     RECT  10.105 43.872 10.259 56.904 ;
     RECT  9.889 58.656 10.285 60.552 ;
     RECT  10.033 61.68 10.285 63.816 ;
     RECT  9.971 8.688 10.289 10.152 ;
     RECT  10.285 58.656 10.289 63.816 ;
     RECT  10.289 62.544 10.357 63.816 ;
     RECT  9.605 16.992 10.393 18.264 ;
     RECT  9.425 19.632 10.393 21 ;
     RECT  9.857 25.68 10.397 32.52 ;
     RECT  10.289 58.656 10.397 61.56 ;
     RECT  9.637 37.2 10.465 39.384 ;
     RECT  9.605 35.424 10.469 35.88 ;
     RECT  8.921 75.36 10.501 75.384 ;
     RECT  10.259 50.304 10.537 56.904 ;
     RECT  10.357 62.544 10.537 64.056 ;
     RECT  10.397 25.68 10.541 29.88 ;
     RECT  10.259 12.72 10.573 13.656 ;
     RECT  9.605 33.552 10.573 33.864 ;
     RECT  10.465 37.2 10.645 39.528 ;
     RECT  10.537 50.304 10.681 56.952 ;
     RECT  10.537 62.544 10.748 64.104 ;
     RECT  10.573 11.952 10.757 13.656 ;
     RECT  10.073 40.56 10.757 42.504 ;
     RECT  10.145 65.808 10.787 74.136 ;
     RECT  10.397 60.048 10.801 61.56 ;
     RECT  10.645 37.008 10.829 39.528 ;
     RECT  10.748 62.544 10.835 64.584 ;
     RECT  10.469 35.424 10.865 35.448 ;
     RECT  10.177 22.224 10.897 24.456 ;
     RECT  10.253 5.712 10.901 5.88 ;
     RECT  10.681 50.304 10.933 57 ;
     RECT  10.397 58.656 10.933 58.92 ;
     RECT  10.933 50.304 11.016 57.096 ;
     RECT  10.829 37.008 11.081 37.656 ;
     RECT  10.829 38.976 11.081 39.528 ;
     RECT  10.501 75.36 11.084 75.864 ;
     RECT  10.393 16.992 11.113 21 ;
     RECT  10.397 31.344 11.113 32.52 ;
     RECT  10.573 33.552 11.113 34.2 ;
     RECT  11.016 50.304 11.113 57.144 ;
     RECT  10.933 58.128 11.113 58.92 ;
     RECT  11.113 16.992 11.117 21.096 ;
     RECT  10.897 22.224 11.149 24.648 ;
     RECT  10.541 25.68 11.149 29.688 ;
     RECT  11.117 20.976 11.153 21.096 ;
     RECT  11.113 31.344 11.153 34.2 ;
     RECT  11.084 75.36 11.171 75.912 ;
     RECT  10.787 67.968 11.221 74.136 ;
     RECT  11.171 75.36 11.221 75.864 ;
     RECT  10.537 2.832 11.225 2.856 ;
     RECT  10.801 60.048 11.225 61.176 ;
     RECT  10.757 41.28 11.473 42.504 ;
     RECT  10.259 43.872 11.473 49.032 ;
     RECT  11.473 41.28 11.477 49.032 ;
     RECT  11.117 16.992 11.509 19.656 ;
     RECT  10.259 15.408 11.545 15.432 ;
     RECT  11.225 60.288 11.549 61.176 ;
     RECT  11.081 37.008 11.581 37.608 ;
     RECT  11.149 22.224 11.617 29.688 ;
     RECT  11.221 67.968 11.747 75.864 ;
     RECT  10.289 8.688 11.797 10.008 ;
     RECT  11.545 15.312 11.797 15.432 ;
     RECT  11.509 16.56 11.797 19.656 ;
     RECT  10.787 65.808 11.797 66.408 ;
     RECT  11.617 22.128 11.801 29.688 ;
     RECT  11.081 38.976 11.905 39 ;
     RECT  11.113 50.304 11.909 58.92 ;
     RECT  10.213 3.984 11.941 4.008 ;
     RECT  11.747 73.872 11.945 75.864 ;
     RECT  10.757 11.952 11.977 13.464 ;
     RECT  11.153 31.632 11.977 34.2 ;
     RECT  11.797 8.688 11.981 10.824 ;
     RECT  10.901 5.712 11.989 5.736 ;
     RECT  11.977 31.632 12.013 34.776 ;
     RECT  11.801 22.272 12.017 29.688 ;
     RECT  11.477 41.424 12.017 49.032 ;
     RECT  11.581 36.768 12.085 37.608 ;
     RECT  11.977 11.952 12.089 14.136 ;
     RECT  11.761 40.368 12.089 40.44 ;
     RECT  11.797 65.808 12.161 66.6 ;
     RECT  12.085 35.856 12.193 37.608 ;
     RECT  11.905 38.784 12.193 39 ;
     RECT  11.909 51.12 12.193 58.92 ;
     RECT  11.989 5.136 12.197 5.736 ;
     RECT  11.797 15.312 12.197 19.656 ;
     RECT  11.941 3.888 12.229 4.008 ;
     RECT  10.537 7.344 12.229 7.368 ;
     RECT  11.981 8.688 12.229 8.856 ;
     RECT  11.948 50.112 12.229 50.136 ;
     RECT  12.013 31.632 12.265 34.872 ;
     RECT  12.193 35.856 12.265 39 ;
     RECT  12.089 40.368 12.409 40.392 ;
     RECT  12.017 22.8 12.445 29.688 ;
     RECT  11.981 10.224 12.481 10.824 ;
     RECT  11.747 67.968 12.481 72.408 ;
     RECT  11.153 21.072 12.517 21.096 ;
     RECT  12.265 31.632 12.661 39 ;
     RECT  12.229 3.168 12.697 4.008 ;
     RECT  12.445 22.8 12.697 29.88 ;
     RECT  12.661 31.104 12.697 39 ;
     RECT  10.835 62.544 12.733 64.056 ;
     RECT  12.697 3.168 12.805 4.152 ;
     RECT  12.089 13.92 12.985 14.136 ;
     RECT  12.197 15.312 12.985 18.984 ;
     RECT  12.017 41.424 13.021 48.264 ;
     RECT  12.985 13.92 13.057 18.984 ;
     RECT  12.481 67.824 13.057 72.408 ;
     RECT  11.945 73.872 13.057 75.72 ;
     RECT  12.229 7.344 13.093 8.856 ;
     RECT  12.805 2.88 13.208 4.152 ;
     RECT  12.197 5.136 13.208 5.544 ;
     RECT  13.093 6.624 13.208 8.856 ;
     RECT  12.481 10.224 13.208 10.968 ;
     RECT  12.089 11.952 13.208 12.792 ;
     RECT  13.057 13.872 13.208 18.984 ;
     RECT  12.517 20.448 13.208 21.096 ;
     RECT  12.697 22.8 13.208 39 ;
     RECT  12.409 40.32 13.208 40.392 ;
     RECT  13.021 41.376 13.208 48.264 ;
     RECT  12.229 49.248 13.208 50.136 ;
     RECT  12.193 51.12 13.208 59.064 ;
     RECT  11.549 60.384 13.208 61.176 ;
     RECT  12.733 62.544 13.208 64.104 ;
     RECT  12.161 66.576 13.208 66.6 ;
     RECT  13.057 67.824 13.208 75.72 ;
     RECT  13.208 2.148 13.312 88.572 ;
     RECT  13.312 2.418 13.504 88.302 ;
     RECT  13.504 20.496 13.529 39 ;
     RECT  13.504 64.08 13.709 75.672 ;
     RECT  13.504 6.624 13.817 13.896 ;
     RECT  13.529 26.112 13.817 39 ;
     RECT  13.817 26.112 13.853 38.472 ;
     RECT  13.504 15.024 13.997 19.416 ;
     RECT  13.853 26.112 14.033 37.944 ;
     RECT  13.504 3.408 14.051 3.432 ;
     RECT  13.504 4.416 14.092 4.872 ;
     RECT  13.709 64.08 14.243 74.136 ;
     RECT  13.504 49.248 14.285 59.304 ;
     RECT  14.243 64.08 14.285 66.744 ;
     RECT  13.504 40.368 14.321 48.264 ;
     RECT  14.243 68.112 14.321 74.136 ;
     RECT  14.321 40.368 14.357 44.712 ;
     RECT  14.321 45.696 14.357 48.264 ;
     RECT  14.033 30.576 14.393 37.944 ;
     RECT  13.997 15.024 14.429 18.024 ;
     RECT  14.285 65.952 14.429 66.744 ;
     RECT  14.321 68.112 14.429 72.696 ;
     RECT  14.357 40.368 14.435 43.128 ;
     RECT  14.429 68.112 14.465 71.448 ;
     RECT  14.429 72.432 14.465 72.696 ;
     RECT  13.529 20.496 14.483 24.936 ;
     RECT  13.709 75.648 14.501 75.672 ;
     RECT  14.393 30.576 14.573 32.52 ;
     RECT  14.465 72.432 14.609 72.6 ;
     RECT  14.033 26.112 14.641 29.592 ;
     RECT  13.997 19.392 14.677 19.416 ;
     RECT  14.357 45.84 14.713 48.264 ;
     RECT  14.285 49.248 14.713 50.232 ;
     RECT  14.321 73.872 14.713 74.136 ;
     RECT  13.817 6.624 14.717 12.792 ;
     RECT  14.713 45.84 14.717 50.232 ;
     RECT  14.285 51.36 14.741 59.304 ;
     RECT  14.741 51.36 14.785 60.024 ;
     RECT  13.504 61.2 14.785 62.856 ;
     RECT  14.285 64.08 14.785 64.968 ;
     RECT  14.092 4.416 14.789 4.44 ;
     RECT  14.609 72.432 14.789 72.456 ;
     RECT  14.717 6.624 14.821 9.768 ;
     RECT  14.393 33.84 14.857 37.944 ;
     RECT  14.857 33.84 14.929 38.856 ;
     RECT  14.929 33.84 15.068 39 ;
     RECT  14.483 21.456 15.073 24.936 ;
     RECT  14.717 10.848 15.109 12.792 ;
     RECT  13.817 13.872 15.109 13.896 ;
     RECT  15.068 33.84 15.185 39.048 ;
     RECT  14.785 51.36 15.185 64.968 ;
     RECT  15.185 35.232 15.217 39.048 ;
     RECT  14.429 15.552 15.289 18.024 ;
     RECT  14.677 19.392 15.289 20.232 ;
     RECT  15.217 35.232 15.361 39.096 ;
     RECT  14.429 65.952 15.397 66.504 ;
     RECT  14.465 68.16 15.397 71.448 ;
     RECT  15.289 15.552 15.401 20.232 ;
     RECT  15.109 10.848 15.433 13.896 ;
     RECT  14.435 40.368 15.433 41.112 ;
     RECT  14.435 42.144 15.433 43.128 ;
     RECT  15.073 21.456 15.469 25.032 ;
     RECT  14.641 26.064 15.469 29.592 ;
     RECT  15.185 51.36 15.469 63.672 ;
     RECT  15.401 15.552 15.473 18.936 ;
     RECT  15.185 64.944 15.541 64.968 ;
     RECT  15.397 65.952 15.541 66.552 ;
     RECT  14.573 30.864 15.613 32.52 ;
     RECT  14.717 48.96 15.649 50.232 ;
     RECT  15.469 51.216 15.649 63.672 ;
     RECT  14.713 73.872 15.649 74.472 ;
     RECT  15.433 40.368 15.653 43.128 ;
     RECT  15.541 64.944 15.725 66.552 ;
     RECT  14.821 6.24 15.772 9.768 ;
     RECT  14.357 44.112 15.829 44.712 ;
     RECT  15.772 6.24 15.833 8.856 ;
     RECT  15.469 21.456 15.869 29.592 ;
     RECT  15.397 68.16 15.869 71.736 ;
     RECT  15.401 20.112 15.901 20.232 ;
     RECT  15.869 21.456 15.901 25.128 ;
     RECT  15.649 73.872 15.905 75.24 ;
     RECT  15.361 35.232 15.977 39.336 ;
     RECT  15.649 48.96 15.977 63.672 ;
     RECT  15.905 75.216 15.977 75.24 ;
     RECT  15.433 10.848 16.009 14.184 ;
     RECT  15.473 17.376 16.013 18.936 ;
     RECT  15.977 37.92 16.013 39.336 ;
     RECT  15.977 48.96 16.013 63.576 ;
     RECT  14.717 45.84 16.045 47.832 ;
     RECT  15.869 68.256 16.045 71.736 ;
     RECT  15.653 40.368 16.049 42.744 ;
     RECT  15.829 43.824 16.067 44.712 ;
     RECT  16.009 10.224 16.081 14.184 ;
     RECT  15.473 15.552 16.081 16.008 ;
     RECT  16.045 68.256 16.081 72.456 ;
     RECT  15.757 5.088 16.085 5.112 ;
     RECT  15.977 35.232 16.121 36.84 ;
     RECT  15.833 6.528 16.157 8.856 ;
     RECT  15.725 65.136 16.225 66.552 ;
     RECT  16.049 42.192 16.265 42.744 ;
     RECT  16.081 68.256 16.369 72.792 ;
     RECT  15.905 73.872 16.369 73.896 ;
     RECT  16.049 40.368 16.477 40.92 ;
     RECT  16.081 10.224 16.549 16.008 ;
     RECT  16.157 6.864 16.553 8.856 ;
     RECT  15.613 30.672 16.561 32.52 ;
     RECT  16.067 43.968 16.621 44.712 ;
     RECT  16.045 45.84 16.621 48.504 ;
     RECT  16.561 30.672 16.625 32.376 ;
     RECT  16.621 43.968 16.625 48.504 ;
     RECT  16.625 30.672 16.657 31.944 ;
     RECT  16.225 65.136 16.657 66.696 ;
     RECT  16.013 38.496 16.981 39.336 ;
     RECT  16.297 4.416 17.053 4.44 ;
     RECT  16.837 5.52 17.053 5.544 ;
     RECT  16.013 17.664 17.053 18.936 ;
     RECT  15.901 20.112 17.053 25.128 ;
     RECT  16.013 49.728 17.053 63.576 ;
     RECT  16.625 44.112 17.057 48.504 ;
     RECT  16.477 40.32 17.077 40.92 ;
     RECT  16.549 10.224 17.089 16.68 ;
     RECT  17.053 17.664 17.089 25.128 ;
     RECT  17.057 44.112 17.093 47.784 ;
     RECT  17.089 10.224 17.129 25.128 ;
     RECT  17.129 10.224 17.161 15.576 ;
     RECT  17.077 40.32 17.164 41.16 ;
     RECT  16.553 8.688 17.165 8.856 ;
     RECT  17.053 49.728 17.165 63.912 ;
     RECT  16.121 36.816 17.233 36.84 ;
     RECT  16.553 6.864 17.237 7.704 ;
     RECT  17.165 60.672 17.237 63.912 ;
     RECT  16.657 30.576 17.273 31.944 ;
     RECT  17.237 63.216 17.305 63.912 ;
     RECT  16.657 65.136 17.305 66.888 ;
     RECT  17.161 10.176 17.345 15.576 ;
     RECT  17.165 49.728 17.377 59.544 ;
     RECT  17.129 16.656 17.381 25.128 ;
     RECT  17.233 36.816 17.449 37.128 ;
     RECT  16.981 38.208 17.449 39.336 ;
     RECT  15.869 26.256 17.485 29.592 ;
     RECT  16.121 35.232 17.485 35.544 ;
     RECT  17.449 36.816 17.485 39.336 ;
     RECT  17.164 40.32 17.485 41.112 ;
     RECT  17.273 31.104 17.489 31.944 ;
     RECT  17.377 49.008 17.489 59.544 ;
     RECT  17.165 8.736 17.521 8.856 ;
     RECT  17.305 63.216 17.561 66.888 ;
     RECT  16.265 42.24 17.593 42.744 ;
     RECT  17.489 31.488 17.629 31.944 ;
     RECT  15.185 33.84 17.629 34.2 ;
     RECT  17.561 63.888 17.629 66.888 ;
     RECT  16.369 68.256 17.629 73.896 ;
     RECT  17.593 42.24 17.917 43.128 ;
     RECT  17.629 33.552 17.941 34.2 ;
     RECT  17.485 35.232 17.941 41.112 ;
     RECT  17.629 63.888 17.989 73.896 ;
     RECT  17.053 4.416 18.097 5.544 ;
     RECT  17.237 7.152 18.205 7.704 ;
     RECT  17.521 8.736 18.205 9.048 ;
     RECT  17.381 16.656 18.277 24.504 ;
     RECT  17.629 31.488 18.277 32.472 ;
     RECT  17.941 33.552 18.277 41.112 ;
     RECT  17.093 44.112 18.277 47.592 ;
     RECT  17.345 10.176 18.385 10.488 ;
     RECT  17.345 11.52 18.385 15.576 ;
     RECT  18.277 16.56 18.385 24.504 ;
     RECT  16.441 2.256 18.421 2.28 ;
     RECT  18.421 2.256 18.493 2.808 ;
     RECT  18.097 3.84 18.493 5.544 ;
     RECT  18.277 31.488 18.493 41.112 ;
     RECT  17.917 42.192 18.493 43.128 ;
     RECT  18.277 44.112 18.493 47.88 ;
     RECT  18.385 10.08 18.565 10.488 ;
     RECT  18.385 11.52 18.565 24.504 ;
     RECT  17.485 26.208 18.565 29.592 ;
     RECT  18.493 2.256 18.608 5.544 ;
     RECT  18.205 7.152 18.608 9.048 ;
     RECT  18.565 10.08 18.608 24.504 ;
     RECT  18.565 26.208 18.608 29.64 ;
     RECT  18.493 31.392 18.608 41.112 ;
     RECT  18.493 42.192 18.608 47.88 ;
     RECT  17.489 49.584 18.608 59.544 ;
     RECT  17.237 60.672 18.608 62.232 ;
     RECT  17.989 63.888 18.608 74.424 ;
     RECT  16.441 75.84 18.608 75.864 ;
     RECT  18.608 2.148 18.712 88.572 ;
     RECT  18.712 2.418 18.904 88.302 ;
     RECT  18.904 11.136 18.929 29.88 ;
     RECT  18.904 61.008 18.929 62.184 ;
     RECT  18.904 6.384 19.073 10.056 ;
     RECT  18.904 30.912 19.073 48.264 ;
     RECT  19.073 6.528 19.181 10.056 ;
     RECT  18.904 63.36 19.181 74.424 ;
     RECT  19.181 6.816 19.187 10.056 ;
     RECT  18.904 50.88 19.217 59.832 ;
     RECT  19.181 72.432 19.325 74.424 ;
     RECT  18.904 2.784 19.361 4.536 ;
     RECT  18.929 14.208 19.433 29.88 ;
     RECT  19.325 74.4 19.433 74.424 ;
     RECT  19.073 30.912 19.505 40.488 ;
     RECT  19.433 16.56 19.613 29.88 ;
     RECT  19.073 41.76 19.715 47.928 ;
     RECT  19.181 67.2 19.859 71.112 ;
     RECT  19.217 56.88 19.897 59.832 ;
     RECT  18.929 61.008 19.897 61.56 ;
     RECT  19.897 56.88 19.957 61.56 ;
     RECT  19.897 49.584 19.969 49.608 ;
     RECT  19.957 56.88 20.077 62.184 ;
     RECT  19.181 63.36 20.077 66.12 ;
     RECT  19.969 49.536 20.189 49.608 ;
     RECT  19.361 3.36 20.329 4.536 ;
     RECT  19.505 40.464 20.369 40.488 ;
     RECT  19.325 72.432 20.401 73.368 ;
     RECT  20.077 56.88 20.437 66.12 ;
     RECT  19.859 67.2 20.437 67.272 ;
     RECT  18.929 11.136 20.473 13.08 ;
     RECT  19.505 30.912 20.473 39.432 ;
     RECT  20.437 56.88 20.477 67.272 ;
     RECT  19.613 26.256 20.533 29.88 ;
     RECT  20.473 30.864 20.533 39.432 ;
     RECT  19.217 50.88 20.545 55.704 ;
     RECT  20.477 61.536 20.549 67.272 ;
     RECT  20.473 11.088 20.581 13.08 ;
     RECT  19.187 6.816 20.621 9.288 ;
     RECT  19.433 14.208 20.627 15.576 ;
     RECT  20.581 10.8 20.636 13.08 ;
     RECT  20.329 3.36 20.677 5.208 ;
     RECT  20.636 10.56 20.689 13.08 ;
     RECT  19.859 68.256 20.689 71.112 ;
     RECT  20.401 72.432 20.689 73.752 ;
     RECT  20.677 3.36 20.723 5.832 ;
     RECT  20.723 4.512 20.725 5.832 ;
     RECT  20.621 6.816 20.725 8.856 ;
     RECT  20.689 9.84 20.761 13.08 ;
     RECT  20.627 14.208 20.761 14.232 ;
     RECT  20.545 50.88 20.761 55.752 ;
     RECT  20.477 56.88 20.761 60.264 ;
     RECT  19.715 43.872 20.773 47.928 ;
     RECT  20.761 50.88 20.773 60.264 ;
     RECT  19.613 16.56 20.801 25.176 ;
     RECT  20.723 3.36 20.837 3.384 ;
     RECT  19.715 41.76 20.945 42.744 ;
     RECT  20.773 43.872 20.945 48.12 ;
     RECT  20.627 15.504 21.049 15.576 ;
     RECT  20.801 16.56 21.049 23.112 ;
     RECT  20.533 26.256 21.053 39.432 ;
     RECT  20.653 76.176 21.109 76.2 ;
     RECT  21.109 76.176 21.155 76.392 ;
     RECT  20.549 62.4 21.157 67.272 ;
     RECT  20.689 68.256 21.157 73.752 ;
     RECT  21.053 30.72 21.193 39.432 ;
     RECT  21.049 15.504 21.197 23.112 ;
     RECT  21.193 30.72 21.269 40.104 ;
     RECT  20.189 49.584 21.308 49.608 ;
     RECT  20.773 50.784 21.308 60.264 ;
     RECT  21.197 15.504 21.377 16.248 ;
     RECT  21.308 49.584 21.377 60.264 ;
     RECT  21.377 50.112 21.395 60.264 ;
     RECT  21.269 30.864 21.413 40.104 ;
     RECT  20.945 43.872 21.521 46.728 ;
     RECT  20.945 41.76 21.589 42.648 ;
     RECT  20.725 4.512 21.593 8.856 ;
     RECT  19.897 75.12 21.625 75.144 ;
     RECT  21.413 31.344 21.661 40.104 ;
     RECT  21.589 41.232 21.661 42.648 ;
     RECT  21.377 15.552 21.665 16.248 ;
     RECT  21.625 75.12 21.665 75.24 ;
     RECT  20.801 24.288 21.697 25.176 ;
     RECT  21.053 26.256 21.697 29.592 ;
     RECT  21.395 50.688 21.697 60.264 ;
     RECT  21.157 62.4 21.701 73.752 ;
     RECT  20.945 48.096 21.773 48.12 ;
     RECT  21.661 31.344 21.881 42.648 ;
     RECT  21.697 50.688 21.881 60.696 ;
     RECT  21.701 62.4 21.917 63.912 ;
     RECT  20.761 9.84 21.989 14.232 ;
     RECT  21.917 62.832 21.989 63.912 ;
     RECT  21.155 76.368 22.025 76.392 ;
     RECT  21.521 43.872 22.061 45.624 ;
     RECT  21.985 77.52 22.069 77.544 ;
     RECT  21.197 17.328 22.129 23.112 ;
     RECT  21.697 24.288 22.129 29.592 ;
     RECT  21.881 51.312 22.133 60.696 ;
     RECT  21.521 46.704 22.165 46.728 ;
     RECT  21.593 5.664 22.201 8.856 ;
     RECT  21.989 9.84 22.201 13.56 ;
     RECT  21.989 62.832 22.241 63.624 ;
     RECT  21.701 65.04 22.241 73.752 ;
     RECT  21.665 16.224 22.277 16.248 ;
     RECT  22.129 17.328 22.313 29.592 ;
     RECT  22.313 17.328 22.345 18.792 ;
     RECT  22.133 59.52 22.421 60.696 ;
     RECT  22.061 43.872 22.453 44.472 ;
     RECT  22.313 19.872 22.489 29.592 ;
     RECT  21.881 31.344 22.489 32.472 ;
     RECT  22.421 60.672 22.489 60.696 ;
     RECT  22.201 5.664 22.493 13.56 ;
     RECT  22.061 45.504 22.525 45.624 ;
     RECT  22.165 46.704 22.525 47.304 ;
     RECT  21.593 4.512 22.813 4.536 ;
     RECT  22.493 5.664 22.813 5.88 ;
     RECT  22.241 65.04 22.813 71.784 ;
     RECT  22.241 72.768 22.813 73.752 ;
     RECT  21.665 75.216 22.813 75.24 ;
     RECT  21.881 33.456 22.817 42.648 ;
     RECT  22.813 72.768 22.817 75.24 ;
     RECT  22.133 51.312 22.853 58.488 ;
     RECT  22.489 60.672 22.857 61.224 ;
     RECT  21.193 2.832 22.889 2.856 ;
     RECT  22.489 19.872 22.889 32.472 ;
     RECT  22.857 60.672 22.931 61.464 ;
     RECT  22.813 64.992 22.961 71.784 ;
     RECT  22.817 73.056 22.961 75.24 ;
     RECT  22.493 7.392 22.993 13.56 ;
     RECT  22.453 43.632 23.029 44.472 ;
     RECT  22.525 45.504 23.029 47.304 ;
     RECT  23.029 43.632 23.033 47.304 ;
     RECT  22.241 62.832 23.281 63.576 ;
     RECT  22.813 4.512 23.317 5.88 ;
     RECT  22.817 36.576 23.317 42.648 ;
     RECT  23.033 43.632 23.317 46.104 ;
     RECT  22.201 48.672 23.317 48.888 ;
     RECT  23.033 47.28 23.461 47.304 ;
     RECT  23.317 48.672 23.461 49.512 ;
     RECT  22.345 16.56 23.641 18.792 ;
     RECT  23.281 62.496 23.641 63.576 ;
     RECT  23.641 15.984 23.857 18.792 ;
     RECT  22.993 7.392 23.929 14.28 ;
     RECT  22.853 51.36 23.929 58.488 ;
     RECT  23.929 7.392 23.965 14.808 ;
     RECT  23.857 15.84 23.965 18.792 ;
     RECT  22.961 73.056 23.965 73.08 ;
     RECT  23.965 7.392 24.001 18.792 ;
     RECT  22.889 19.872 24.001 25.176 ;
     RECT  23.929 50.928 24.001 58.488 ;
     RECT  23.893 2.784 24.008 2.808 ;
     RECT  23.317 4.032 24.008 5.88 ;
     RECT  24.001 7.392 24.008 25.176 ;
     RECT  22.889 26.256 24.008 32.472 ;
     RECT  22.817 33.456 24.008 35.304 ;
     RECT  23.317 36.576 24.008 46.104 ;
     RECT  23.461 47.28 24.008 49.512 ;
     RECT  24.001 50.832 24.008 58.488 ;
     RECT  22.421 59.52 24.008 59.544 ;
     RECT  22.931 60.912 24.008 61.464 ;
     RECT  23.641 62.496 24.008 63.816 ;
     RECT  22.961 64.992 24.008 70.824 ;
     RECT  23.965 72.96 24.008 73.08 ;
     RECT  22.961 74.064 24.008 75.24 ;
     RECT  24.008 2.148 24.112 88.572 ;
     RECT  24.112 2.418 24.304 88.302 ;
     RECT  24.304 74.544 24.365 74.712 ;
     RECT  24.304 11.424 24.473 20.712 ;
     RECT  24.304 60.912 24.508 63.864 ;
     RECT  24.508 60.912 24.509 61.128 ;
     RECT  24.304 68.976 24.563 71.592 ;
     RECT  24.304 64.992 24.581 67.848 ;
     RECT  24.508 62.496 24.617 63.864 ;
     RECT  24.304 47.712 24.689 47.736 ;
     RECT  24.304 50.832 24.725 59.544 ;
     RECT  24.509 60.912 24.869 61.08 ;
     RECT  24.869 61.008 24.877 61.08 ;
     RECT  24.304 22.512 24.905 25.272 ;
     RECT  24.304 78.624 24.905 79.224 ;
     RECT  24.304 2.688 24.941 8.856 ;
     RECT  24.725 50.88 25.049 59.544 ;
     RECT  24.941 2.688 25.113 4.68 ;
     RECT  25.113 2.688 25.129 3.672 ;
     RECT  24.877 61.056 25.157 61.08 ;
     RECT  24.365 74.544 25.193 74.664 ;
     RECT  24.941 5.808 25.229 8.856 ;
     RECT  24.473 11.52 25.265 20.712 ;
     RECT  24.905 22.512 25.265 24.552 ;
     RECT  25.129 2.784 25.301 3.672 ;
     RECT  25.265 22.848 25.301 24.552 ;
     RECT  25.265 15.984 25.369 20.712 ;
     RECT  24.304 49.344 25.369 49.512 ;
     RECT  24.304 42.144 25.405 46.488 ;
     RECT  25.369 47.472 25.405 47.496 ;
     RECT  24.304 33.552 25.441 41.016 ;
     RECT  25.405 42.144 25.441 47.496 ;
     RECT  24.581 65.088 25.441 67.848 ;
     RECT  24.563 68.976 25.441 71.448 ;
     RECT  25.369 15.984 25.445 21.096 ;
     RECT  25.445 16.32 25.477 21.096 ;
     RECT  25.229 7.392 25.513 8.856 ;
     RECT  24.304 10.176 25.513 10.44 ;
     RECT  24.617 62.496 25.513 63.816 ;
     RECT  25.369 49.344 25.549 49.656 ;
     RECT  25.441 33.552 25.589 47.496 ;
     RECT  25.193 74.592 25.621 74.664 ;
     RECT  24.304 75.84 25.621 76.392 ;
     RECT  25.301 23.04 25.625 24.552 ;
     RECT  24.304 26.256 25.625 32.424 ;
     RECT  25.549 48.672 25.693 49.656 ;
     RECT  25.621 74.592 25.697 76.392 ;
     RECT  25.513 7.392 25.705 10.44 ;
     RECT  25.705 9.648 25.729 10.44 ;
     RECT  25.265 11.52 25.729 14.28 ;
     RECT  25.113 4.656 25.756 4.68 ;
     RECT  25.049 50.88 25.765 56.28 ;
     RECT  25.513 62.064 25.909 63.816 ;
     RECT  25.589 33.552 25.913 46.2 ;
     RECT  25.049 57.408 25.945 59.544 ;
     RECT  25.441 65.088 25.945 71.448 ;
     RECT  25.945 57.408 25.981 59.928 ;
     RECT  25.765 50.832 26.089 56.28 ;
     RECT  25.981 57.408 26.089 60.456 ;
     RECT  25.945 64.992 26.093 71.448 ;
     RECT  26.093 64.992 26.129 71.256 ;
     RECT  26.129 67.152 26.201 71.256 ;
     RECT  25.229 5.808 26.269 6.264 ;
     RECT  25.705 7.392 26.269 8.52 ;
     RECT  25.693 48.48 26.273 49.656 ;
     RECT  25.589 47.232 26.309 47.496 ;
     RECT  26.089 50.832 26.341 60.456 ;
     RECT  26.341 50.832 26.381 60.984 ;
     RECT  25.909 62.064 26.413 63.96 ;
     RECT  26.129 64.992 26.413 66.168 ;
     RECT  25.729 9.648 26.417 14.28 ;
     RECT  25.729 77.904 26.444 77.928 ;
     RECT  24.905 79.2 26.485 79.224 ;
     RECT  26.417 9.648 26.525 11.976 ;
     RECT  26.444 77.712 26.531 77.928 ;
     RECT  26.485 79.2 26.589 79.32 ;
     RECT  26.269 5.808 26.593 8.52 ;
     RECT  25.625 26.304 26.629 32.424 ;
     RECT  24.304 72.96 26.629 72.984 ;
     RECT  25.301 3.648 26.737 3.672 ;
     RECT  25.625 23.04 26.737 24.408 ;
     RECT  25.477 16.32 26.773 21.288 ;
     RECT  26.629 26.208 26.773 32.424 ;
     RECT  26.737 23.04 26.809 24.504 ;
     RECT  26.737 3.6 26.885 3.672 ;
     RECT  26.417 13.44 26.953 14.28 ;
     RECT  26.773 26.208 26.953 32.568 ;
     RECT  25.913 33.552 26.953 45.576 ;
     RECT  26.773 16.08 26.993 21.288 ;
     RECT  26.593 5.28 27.013 8.52 ;
     RECT  26.953 13.44 27.133 14.664 ;
     RECT  26.993 16.08 27.133 20.712 ;
     RECT  26.953 26.208 27.137 45.576 ;
     RECT  26.201 67.248 27.169 71.256 ;
     RECT  26.629 72.672 27.169 72.984 ;
     RECT  27.169 78 27.205 78.024 ;
     RECT  27.169 67.248 27.277 72.984 ;
     RECT  26.309 47.232 27.313 47.304 ;
     RECT  26.273 48.48 27.313 49.608 ;
     RECT  27.137 26.208 27.317 45.528 ;
     RECT  26.413 62.064 27.352 66.168 ;
     RECT  27.352 62.064 27.385 66.216 ;
     RECT  27.277 67.248 27.385 73.512 ;
     RECT  27.133 13.44 27.425 20.712 ;
     RECT  25.697 74.592 27.425 76.2 ;
     RECT  27.425 74.688 27.452 76.2 ;
     RECT  27.452 74.688 27.493 76.68 ;
     RECT  27.205 78 27.493 78.264 ;
     RECT  27.493 74.688 27.539 78.264 ;
     RECT  26.381 51.024 27.565 60.984 ;
     RECT  27.385 62.064 27.605 73.512 ;
     RECT  27.605 62.064 27.641 66.936 ;
     RECT  27.644 3.168 27.673 3.192 ;
     RECT  26.525 9.648 27.673 11.688 ;
     RECT  27.673 9.648 27.709 12.024 ;
     RECT  27.565 50.928 27.709 60.984 ;
     RECT  27.539 77.232 27.713 78.264 ;
     RECT  27.709 50.64 27.745 60.984 ;
     RECT  27.641 62.064 27.749 66.648 ;
     RECT  27.749 62.064 27.785 66.504 ;
     RECT  27.313 47.232 27.817 49.608 ;
     RECT  27.317 26.304 27.821 45.528 ;
     RECT  27.709 9.6 27.889 12.024 ;
     RECT  27.425 13.44 27.889 14.088 ;
     RECT  27.817 46.56 27.889 49.608 ;
     RECT  27.745 50.64 27.889 61.032 ;
     RECT  26.809 22.752 27.893 24.504 ;
     RECT  27.893 22.752 27.925 24.408 ;
     RECT  26.589 79.296 27.932 79.32 ;
     RECT  27.932 78.528 28.019 79.32 ;
     RECT  27.013 4.224 28.069 8.52 ;
     RECT  27.889 9.6 28.069 14.088 ;
     RECT  27.889 46.56 28.069 61.032 ;
     RECT  27.785 62.544 28.109 66.504 ;
     RECT  27.605 68.112 28.141 73.512 ;
     RECT  28.109 62.544 28.145 63.96 ;
     RECT  28.109 64.944 28.145 66.504 ;
     RECT  28.069 46.512 28.181 61.032 ;
     RECT  28.141 68.112 28.253 73.56 ;
     RECT  27.673 2.832 28.537 3.192 ;
     RECT  28.069 4.224 28.537 14.088 ;
     RECT  27.821 33.264 28.645 45.528 ;
     RECT  28.181 46.512 28.645 48.264 ;
     RECT  27.821 26.304 28.753 32.28 ;
     RECT  28.753 25.488 28.789 32.28 ;
     RECT  28.645 33.264 28.789 48.264 ;
     RECT  28.253 68.112 28.825 72.552 ;
     RECT  28.181 49.584 28.861 61.032 ;
     RECT  28.145 62.544 28.861 63.528 ;
     RECT  28.537 2.832 28.969 14.088 ;
     RECT  27.425 15.072 28.969 20.712 ;
     RECT  28.825 67.68 28.969 72.552 ;
     RECT  27.925 22.032 29.005 24.408 ;
     RECT  28.969 2.832 29.077 20.712 ;
     RECT  29.005 21.984 29.077 24.408 ;
     RECT  28.861 49.584 29.221 63.528 ;
     RECT  28.145 64.944 29.221 66.168 ;
     RECT  28.969 67.152 29.269 72.552 ;
     RECT  28.253 73.536 29.269 73.56 ;
     RECT  28.789 25.488 29.365 48.264 ;
     RECT  27.713 77.232 29.365 77.544 ;
     RECT  28.019 79.296 29.365 79.32 ;
     RECT  29.077 2.832 29.408 24.408 ;
     RECT  29.365 25.44 29.408 48.264 ;
     RECT  29.221 49.584 29.408 66.168 ;
     RECT  29.269 67.152 29.408 73.56 ;
     RECT  27.539 74.688 29.408 76.2 ;
     RECT  29.365 77.232 29.408 79.32 ;
     RECT  29.408 2.148 29.512 88.572 ;
     RECT  29.512 2.352 29.704 88.302 ;
     RECT  29.704 10.896 29.801 37.176 ;
     RECT  29.704 5.76 29.837 7.752 ;
     RECT  29.801 10.896 29.909 35.448 ;
     RECT  29.909 10.896 29.945 35.016 ;
     RECT  29.704 50.928 29.945 77.352 ;
     RECT  29.837 5.856 29.981 7.752 ;
     RECT  29.704 43.344 30.017 49.8 ;
     RECT  29.945 50.928 30.161 77.256 ;
     RECT  30.161 64.848 30.197 77.256 ;
     RECT  29.945 10.896 30.341 24.408 ;
     RECT  30.197 64.848 30.413 74.952 ;
     RECT  29.801 36.576 30.733 37.176 ;
     RECT  29.704 38.16 30.733 41.976 ;
     RECT  30.017 43.344 30.733 49.608 ;
     RECT  29.981 7.2 30.769 7.752 ;
     RECT  29.704 2.352 30.773 2.808 ;
     RECT  30.413 74.688 30.773 74.952 ;
     RECT  30.341 10.896 30.845 22.44 ;
     RECT  30.733 36.576 30.845 49.608 ;
     RECT  30.413 64.848 30.851 73.56 ;
     RECT  30.769 7.2 30.949 8.232 ;
     RECT  29.945 25.44 30.953 35.016 ;
     RECT  29.704 3.984 30.985 4.776 ;
     RECT  30.845 36.576 31.021 49.032 ;
     RECT  30.161 50.928 31.021 63.768 ;
     RECT  29.704 78.384 31.043 79.32 ;
     RECT  30.985 3.456 31.057 4.776 ;
     RECT  29.981 5.856 31.057 6.12 ;
     RECT  30.953 30.576 31.097 35.016 ;
     RECT  31.021 36.432 31.097 49.032 ;
     RECT  31.057 3.456 31.129 6.12 ;
     RECT  30.949 7.2 31.129 8.568 ;
     RECT  30.341 23.472 31.237 24.408 ;
     RECT  30.953 25.44 31.237 29.592 ;
     RECT  30.851 68.976 31.241 73.56 ;
     RECT  31.237 23.472 31.321 29.592 ;
     RECT  31.129 3.456 31.345 8.568 ;
     RECT  29.704 9.6 31.345 9.816 ;
     RECT  31.345 3.456 31.385 9.816 ;
     RECT  31.097 36.432 31.385 37.176 ;
     RECT  31.241 68.976 31.385 73.032 ;
     RECT  31.043 78.384 31.385 79.224 ;
     RECT  30.851 64.848 31.421 67.704 ;
     RECT  30.773 74.928 31.493 74.952 ;
     RECT  31.385 78.864 31.493 79.224 ;
     RECT  31.021 50.4 31.529 63.768 ;
     RECT  30.197 75.984 31.561 77.256 ;
     RECT  31.561 74.976 31.597 77.256 ;
     RECT  31.097 38.16 31.601 49.032 ;
     RECT  31.421 64.848 31.709 67.464 ;
     RECT  31.385 36.432 31.741 37.128 ;
     RECT  31.709 64.848 31.745 65.784 ;
     RECT  31.529 50.688 31.765 63.768 ;
     RECT  31.597 74.976 31.781 77.352 ;
     RECT  31.765 50.688 31.852 63.816 ;
     RECT  30.845 10.896 31.853 18.84 ;
     RECT  31.853 11.28 31.885 18.84 ;
     RECT  30.845 19.92 31.885 22.44 ;
     RECT  31.745 64.896 31.889 65.784 ;
     RECT  31.885 11.28 31.925 22.44 ;
     RECT  31.925 11.328 31.957 22.44 ;
     RECT  31.321 23.472 31.957 24.408 ;
     RECT  31.385 68.976 31.993 71.256 ;
     RECT  31.385 72.24 32.003 73.032 ;
     RECT  31.097 30.576 32.069 34.728 ;
     RECT  31.385 3.456 32.105 7.752 ;
     RECT  31.321 25.584 32.173 29.592 ;
     RECT  32.069 30.576 32.173 31.8 ;
     RECT  32.069 32.832 32.173 34.728 ;
     RECT  31.741 35.712 32.173 37.128 ;
     RECT  31.601 38.16 32.249 48.792 ;
     RECT  32.173 32.832 32.389 37.128 ;
     RECT  32.249 38.16 32.389 48.456 ;
     RECT  32.105 7.584 32.425 7.752 ;
     RECT  31.385 8.976 32.425 9.816 ;
     RECT  31.957 11.328 32.429 24.408 ;
     RECT  32.425 7.584 32.465 9.816 ;
     RECT  32.429 11.328 32.483 22.344 ;
     RECT  32.389 32.832 32.579 48.456 ;
     RECT  32.465 9.6 32.609 9.816 ;
     RECT  32.483 14.496 32.609 22.344 ;
     RECT  32.429 23.328 32.627 24.408 ;
     RECT  32.627 23.376 32.636 24.408 ;
     RECT  32.173 25.584 32.636 31.8 ;
     RECT  32.579 32.832 32.645 40.968 ;
     RECT  31.852 50.688 32.677 63.432 ;
     RECT  31.781 77.328 32.717 77.352 ;
     RECT  32.636 23.376 32.723 31.8 ;
     RECT  30.773 2.352 32.821 2.376 ;
     RECT  32.677 50.592 32.857 63.432 ;
     RECT  32.821 2.256 32.861 2.376 ;
     RECT  32.105 3.456 32.861 6.312 ;
     RECT  31.709 66.768 32.933 67.464 ;
     RECT  32.609 9.792 32.965 9.816 ;
     RECT  32.965 9.792 33.073 9.864 ;
     RECT  32.483 11.328 33.073 13.128 ;
     RECT  32.723 25.824 33.109 31.8 ;
     RECT  32.645 32.832 33.109 35.832 ;
     RECT  32.857 50.592 33.145 63.624 ;
     RECT  32.003 72.96 33.181 73.032 ;
     RECT  31.781 74.976 33.217 75.768 ;
     RECT  32.465 7.584 33.253 8.568 ;
     RECT  33.217 74.736 33.317 75.768 ;
     RECT  33.181 72.384 33.349 73.032 ;
     RECT  33.145 50.16 33.433 63.624 ;
     RECT  31.889 64.944 33.433 65.784 ;
     RECT  33.317 74.688 33.433 75.768 ;
     RECT  33.109 25.824 33.437 35.832 ;
     RECT  33.073 9.792 33.473 13.128 ;
     RECT  31.493 78.864 33.545 78.888 ;
     RECT  32.645 37.008 33.577 40.968 ;
     RECT  32.579 42 33.577 48.456 ;
     RECT  33.433 50.16 33.577 65.784 ;
     RECT  32.861 5.232 33.596 6.312 ;
     RECT  33.253 7.392 33.596 8.568 ;
     RECT  32.933 67.44 33.613 67.464 ;
     RECT  31.993 68.64 33.613 71.256 ;
     RECT  33.596 5.232 33.649 8.568 ;
     RECT  33.473 9.792 33.649 12.984 ;
     RECT  33.437 25.824 33.653 31.944 ;
     RECT  33.577 37.008 33.653 48.456 ;
     RECT  33.649 5.232 33.683 12.984 ;
     RECT  33.613 67.44 33.721 71.256 ;
     RECT  33.349 72.384 33.721 73.32 ;
     RECT  32.723 23.376 33.725 24.792 ;
     RECT  33.683 7.392 33.761 12.984 ;
     RECT  33.761 7.392 33.772 9.48 ;
     RECT  33.433 74.592 33.793 75.768 ;
     RECT  32.861 2.256 33.797 2.28 ;
     RECT  33.653 41.856 33.797 48.456 ;
     RECT  32.861 3.456 33.829 3.96 ;
     RECT  33.683 5.232 33.829 6.312 ;
     RECT  33.725 23.376 33.901 23.496 ;
     RECT  33.577 50.16 33.937 66.168 ;
     RECT  32.609 14.496 33.973 22.056 ;
     RECT  33.901 23.04 33.973 23.496 ;
     RECT  33.253 77.808 34.045 77.832 ;
     RECT  33.761 10.656 34.441 12.984 ;
     RECT  34.441 10.656 34.549 13.08 ;
     RECT  33.973 14.496 34.549 23.496 ;
     RECT  33.829 3.456 34.657 6.312 ;
     RECT  33.772 7.392 34.657 9.288 ;
     RECT  33.725 24.48 34.657 24.792 ;
     RECT  33.653 25.824 34.657 31.752 ;
     RECT  33.937 49.824 34.657 66.168 ;
     RECT  34.657 24.48 34.801 31.752 ;
     RECT  33.797 47.136 34.801 48.456 ;
     RECT  34.657 49.776 34.801 66.168 ;
     RECT  34.657 3.456 34.808 9.288 ;
     RECT  34.549 10.656 34.808 23.496 ;
     RECT  34.801 24.48 34.808 31.992 ;
     RECT  33.437 33.024 34.808 35.832 ;
     RECT  33.653 37.008 34.808 40.872 ;
     RECT  33.797 41.856 34.808 46.104 ;
     RECT  34.801 47.136 34.808 66.168 ;
     RECT  33.721 67.44 34.808 73.32 ;
     RECT  33.793 74.592 34.808 76.392 ;
     RECT  34.045 77.808 34.808 78.36 ;
     RECT  34.808 2.148 34.912 88.572 ;
     RECT  34.912 2.418 35.104 88.302 ;
     RECT  35.104 5.76 35.309 24.552 ;
     RECT  35.104 62.208 35.309 71.832 ;
     RECT  35.104 48.384 35.381 57.144 ;
     RECT  35.309 62.448 35.381 71.832 ;
     RECT  35.104 25.824 35.389 31.224 ;
     RECT  35.381 62.448 35.453 63.576 ;
     RECT  35.104 58.512 35.597 59.592 ;
     RECT  35.381 65.232 35.597 71.832 ;
     RECT  35.104 75.696 35.633 75.768 ;
     RECT  35.104 37.008 35.777 47.352 ;
     RECT  35.104 32.352 35.795 35.736 ;
     RECT  35.389 30.576 35.957 31.224 ;
     RECT  35.309 5.76 36.065 10.248 ;
     RECT  35.309 11.664 36.065 24.552 ;
     RECT  35.104 74.4 36.085 74.664 ;
     RECT  35.633 75.696 36.085 75.72 ;
     RECT  36.065 5.76 36.097 9.816 ;
     RECT  35.104 80.4 36.097 81.048 ;
     RECT  35.104 73.296 36.133 73.32 ;
     RECT  36.085 74.4 36.133 75.72 ;
     RECT  35.104 77.28 36.133 78.648 ;
     RECT  36.065 22.464 36.209 24.552 ;
     RECT  36.133 73.296 36.245 75.72 ;
     RECT  35.381 48.384 36.277 49.128 ;
     RECT  36.133 77.28 36.281 78.696 ;
     RECT  35.795 32.352 36.313 32.472 ;
     RECT  35.104 2.832 36.457 3.912 ;
     RECT  36.097 5.328 36.457 9.816 ;
     RECT  36.209 22.56 36.457 24.552 ;
     RECT  35.389 25.824 36.457 29.592 ;
     RECT  36.097 79.728 36.461 81.048 ;
     RECT  36.281 77.28 36.529 78.648 ;
     RECT  35.795 33.552 36.533 35.736 ;
     RECT  36.245 73.296 36.601 74.808 ;
     RECT  36.461 79.728 36.605 79.752 ;
     RECT  35.777 41.856 36.637 47.352 ;
     RECT  36.277 48.336 36.637 49.128 ;
     RECT  35.453 62.496 36.637 63.576 ;
     RECT  36.313 31.92 36.641 32.472 ;
     RECT  36.637 41.856 36.641 49.128 ;
     RECT  36.529 77.04 36.641 78.648 ;
     RECT  36.457 22.56 36.713 29.592 ;
     RECT  35.777 37.008 36.745 40.728 ;
     RECT  36.641 41.856 36.745 49.08 ;
     RECT  36.745 37.008 36.785 49.08 ;
     RECT  36.601 72.912 36.785 74.808 ;
     RECT  35.104 61.008 36.805 61.032 ;
     RECT  36.637 62.112 36.817 63.576 ;
     RECT  36.817 62.112 36.821 63.672 ;
     RECT  36.533 33.6 36.889 35.736 ;
     RECT  36.785 37.008 36.889 42.6 ;
     RECT  36.805 61.008 36.892 61.128 ;
     RECT  36.785 43.584 36.893 49.08 ;
     RECT  36.821 62.112 36.961 62.136 ;
     RECT  36.821 63.312 36.997 63.672 ;
     RECT  35.597 65.232 36.997 71.352 ;
     RECT  35.381 50.112 37.033 57.144 ;
     RECT  36.065 11.664 37.037 21.384 ;
     RECT  36.713 22.56 37.037 24.552 ;
     RECT  35.597 58.512 37.037 59.544 ;
     RECT  37.037 11.664 37.141 14.28 ;
     RECT  36.892 61.008 37.217 61.032 ;
     RECT  37.033 50.112 37.285 57.24 ;
     RECT  37.141 10.848 37.289 14.28 ;
     RECT  37.037 15.264 37.321 21.384 ;
     RECT  37.037 22.56 37.321 24.504 ;
     RECT  36.889 33.6 37.325 42.6 ;
     RECT  36.997 65.232 37.357 71.4 ;
     RECT  36.893 43.584 37.397 49.032 ;
     RECT  36.457 2.832 37.541 9.816 ;
     RECT  36.785 73.296 37.573 74.808 ;
     RECT  36.997 63.312 37.609 63.72 ;
     RECT  37.573 73.296 37.609 75.384 ;
     RECT  37.325 35.712 37.613 42.6 ;
     RECT  37.609 73.296 37.621 75.768 ;
     RECT  36.641 77.04 37.621 78.168 ;
     RECT  37.621 73.296 37.667 78.168 ;
     RECT  37.541 6.384 37.681 9.816 ;
     RECT  37.289 10.848 37.681 14.232 ;
     RECT  37.285 50.112 37.753 57.384 ;
     RECT  37.037 58.512 37.753 59.496 ;
     RECT  37.609 63.312 37.753 64.2 ;
     RECT  37.357 65.232 37.753 72.216 ;
     RECT  37.667 73.296 37.757 74.232 ;
     RECT  35.957 30.576 37.789 30.6 ;
     RECT  36.641 31.92 37.789 32.424 ;
     RECT  37.753 63.312 37.789 72.216 ;
     RECT  36.461 81.024 37.82 81.048 ;
     RECT  37.667 75.744 37.825 78.168 ;
     RECT  37.82 80.928 37.861 81.048 ;
     RECT  37.681 6.384 37.907 14.232 ;
     RECT  37.861 80.4 37.907 81.048 ;
     RECT  36.961 62.016 37.969 62.136 ;
     RECT  37.541 2.832 37.973 5.352 ;
     RECT  36.713 25.728 37.973 29.592 ;
     RECT  37.907 6.384 38.045 12.024 ;
     RECT  37.973 25.824 38.045 29.592 ;
     RECT  37.613 35.904 38.045 42.6 ;
     RECT  38.045 6.384 38.081 11.928 ;
     RECT  37.969 61.056 38.113 62.136 ;
     RECT  37.789 63.12 38.113 72.216 ;
     RECT  37.973 2.832 38.149 4.68 ;
     RECT  37.321 15.264 38.185 24.504 ;
     RECT  37.757 73.488 38.189 74.232 ;
     RECT  37.825 75.744 38.195 78.696 ;
     RECT  38.045 26.208 38.197 29.592 ;
     RECT  37.789 30.576 38.197 32.424 ;
     RECT  38.045 38.448 38.257 42.6 ;
     RECT  37.397 43.584 38.257 48.408 ;
     RECT  37.907 13.152 38.329 14.232 ;
     RECT  38.185 15.216 38.329 24.504 ;
     RECT  38.197 26.208 38.437 32.424 ;
     RECT  37.325 33.6 38.653 34.632 ;
     RECT  38.045 35.904 38.653 37.368 ;
     RECT  38.257 38.448 38.653 48.408 ;
     RECT  38.329 13.152 38.657 24.504 ;
     RECT  38.437 26.208 38.725 32.52 ;
     RECT  38.653 33.6 38.725 37.368 ;
     RECT  38.653 38.448 38.725 48.936 ;
     RECT  37.753 50.112 38.725 59.496 ;
     RECT  38.081 6.384 38.729 11.784 ;
     RECT  38.729 6.72 38.801 11.784 ;
     RECT  38.801 7.344 38.812 11.784 ;
     RECT  38.657 13.152 38.837 16.968 ;
     RECT  38.657 18 38.837 22.2 ;
     RECT  38.195 75.744 38.869 78.504 ;
     RECT  37.907 80.4 38.869 80.424 ;
     RECT  38.581 81.6 38.869 81.624 ;
     RECT  38.725 26.208 38.909 37.368 ;
     RECT  38.837 18 38.945 22.104 ;
     RECT  38.909 26.208 38.945 31.416 ;
     RECT  38.869 80.016 38.953 81.624 ;
     RECT  38.189 73.488 39.049 73.608 ;
     RECT  38.869 74.928 39.053 78.504 ;
     RECT  38.953 81.6 39.085 81.624 ;
     RECT  38.945 26.208 39.089 30.84 ;
     RECT  38.725 38.448 39.089 59.496 ;
     RECT  38.149 2.736 39.157 4.68 ;
     RECT  38.657 23.28 39.161 24.504 ;
     RECT  38.909 32.976 39.161 37.368 ;
     RECT  39.053 74.928 39.193 75 ;
     RECT  38.812 7.344 39.233 9.096 ;
     RECT  39.089 49.632 39.301 59.496 ;
     RECT  38.113 61.056 39.301 72.216 ;
     RECT  39.053 76.656 39.301 78.504 ;
     RECT  38.953 80.016 39.301 80.136 ;
     RECT  39.161 23.472 39.349 24.504 ;
     RECT  39.349 23.472 39.373 24.936 ;
     RECT  39.089 26.208 39.373 30.6 ;
     RECT  39.301 49.632 39.397 72.216 ;
     RECT  39.049 73.392 39.397 73.608 ;
     RECT  39.161 33.072 39.589 37.368 ;
     RECT  39.089 38.448 39.589 48.36 ;
     RECT  38.837 13.152 39.841 16.824 ;
     RECT  38.761 5.712 39.949 5.736 ;
     RECT  39.157 2.256 39.985 4.68 ;
     RECT  39.949 5.712 39.985 5.784 ;
     RECT  39.193 74.64 40.021 75 ;
     RECT  39.373 23.472 40.069 30.6 ;
     RECT  38.945 18 40.165 21.672 ;
     RECT  39.841 12.864 40.201 16.824 ;
     RECT  40.165 18 40.201 22.296 ;
     RECT  39.985 2.256 40.208 5.784 ;
     RECT  39.233 7.344 40.208 8.52 ;
     RECT  38.812 10.848 40.208 11.784 ;
     RECT  40.201 12.864 40.208 22.296 ;
     RECT  40.069 23.472 40.208 30.696 ;
     RECT  39.589 33.072 40.208 48.36 ;
     RECT  39.397 49.632 40.208 73.608 ;
     RECT  40.021 74.592 40.208 75 ;
     RECT  39.301 76.656 40.208 80.136 ;
     RECT  39.085 81.6 40.208 81.768 ;
     RECT  40.208 2.148 40.312 88.572 ;
     RECT  40.312 2.256 40.349 88.302 ;
     RECT  40.349 2.418 40.504 88.302 ;
     RECT  40.504 19.632 40.673 32.52 ;
     RECT  40.504 36.24 40.717 75.288 ;
     RECT  40.717 36.24 40.739 75.24 ;
     RECT  40.504 4.992 40.889 8.52 ;
     RECT  40.417 0.048 40.993 0.072 ;
     RECT  40.504 81.456 41.027 83.448 ;
     RECT  40.739 36.24 41.069 70.296 ;
     RECT  41.027 82.608 41.105 83.448 ;
     RECT  40.993 0.048 41.137 0.12 ;
     RECT  41.069 36.288 41.141 70.296 ;
     RECT  40.739 71.328 41.177 75.24 ;
     RECT  40.504 10.176 41.249 11.832 ;
     RECT  41.141 36.576 41.249 70.296 ;
     RECT  41.249 36.816 41.321 70.296 ;
     RECT  40.504 12.864 41.357 18.504 ;
     RECT  40.504 77.04 41.465 80.376 ;
     RECT  40.889 4.992 41.501 5.784 ;
     RECT  40.504 3.12 41.573 3.864 ;
     RECT  41.177 71.328 41.609 71.832 ;
     RECT  40.673 31.536 41.612 32.52 ;
     RECT  40.504 33.936 41.612 35.16 ;
     RECT  41.027 81.456 41.645 81.624 ;
     RECT  41.321 36.816 41.681 49.272 ;
     RECT  41.465 77.04 41.681 78.408 ;
     RECT  41.465 79.824 41.749 80.376 ;
     RECT  40.673 19.632 41.753 30.216 ;
     RECT  41.501 4.992 41.785 5.016 ;
     RECT  40.889 6.96 41.857 8.52 ;
     RECT  41.249 10.176 41.857 10.584 ;
     RECT  41.612 31.536 41.897 35.16 ;
     RECT  41.249 11.76 41.941 11.832 ;
     RECT  41.357 12.864 41.941 13.608 ;
     RECT  41.857 6.96 42.001 10.584 ;
     RECT  41.941 11.76 42.028 13.608 ;
     RECT  42.028 13.056 42.113 13.608 ;
     RECT  41.753 23.088 42.145 30.216 ;
     RECT  41.681 37.872 42.185 49.272 ;
     RECT  41.357 14.784 42.217 18.504 ;
     RECT  41.753 19.632 42.217 21.912 ;
     RECT  42.001 6.72 42.221 10.584 ;
     RECT  42.221 9.12 42.257 10.584 ;
     RECT  41.897 31.536 42.289 35.016 ;
     RECT  42.145 23.088 42.293 30.312 ;
     RECT  42.185 37.872 42.293 47.688 ;
     RECT  42.185 48.816 42.361 49.272 ;
     RECT  41.321 50.544 42.361 64.008 ;
     RECT  42.361 48.816 42.397 64.008 ;
     RECT  41.321 65.184 42.397 70.296 ;
     RECT  41.177 72.96 42.397 75.24 ;
     RECT  41.749 79.824 42.433 80.472 ;
     RECT  41.645 81.6 42.433 81.624 ;
     RECT  41.681 77.472 42.437 78.408 ;
     RECT  42.257 10.176 42.469 10.584 ;
     RECT  42.028 11.76 42.469 11.832 ;
     RECT  42.217 14.784 42.473 21.912 ;
     RECT  42.473 14.784 42.509 21.192 ;
     RECT  42.397 48.816 42.515 70.296 ;
     RECT  41.785 4.848 42.517 5.016 ;
     RECT  42.517 4.848 42.577 5.112 ;
     RECT  42.113 13.056 42.581 13.416 ;
     RECT  42.469 10.176 42.589 11.832 ;
     RECT  42.293 23.088 42.653 24.12 ;
     RECT  41.609 71.328 42.721 71.64 ;
     RECT  42.397 72.96 42.721 75.336 ;
     RECT  41.137 0.048 42.757 0.168 ;
     RECT  41.681 36.816 42.757 36.888 ;
     RECT  42.433 81.6 42.757 82.392 ;
     RECT  41.105 83.424 42.757 83.448 ;
     RECT  42.509 14.976 42.761 21.192 ;
     RECT  41.573 3.12 42.793 3.384 ;
     RECT  42.293 37.872 42.797 41.256 ;
     RECT  42.293 42.24 42.797 47.688 ;
     RECT  42.577 4.8 42.829 5.112 ;
     RECT  42.757 81.456 42.844 83.448 ;
     RECT  42.793 3.12 42.865 3.624 ;
     RECT  42.829 4.8 42.865 5.352 ;
     RECT  42.589 10.176 42.869 10.2 ;
     RECT  42.293 25.104 42.937 30.312 ;
     RECT  42.289 31.344 42.937 35.016 ;
     RECT  42.257 9.12 42.977 9.192 ;
     RECT  42.797 43.584 42.977 47.688 ;
     RECT  42.721 71.328 42.997 75.336 ;
     RECT  42.433 79.44 43.013 80.472 ;
     RECT  42.653 23.856 43.049 24.12 ;
     RECT  42.937 25.104 43.049 35.016 ;
     RECT  43.049 33.12 43.081 35.016 ;
     RECT  42.844 83.424 43.117 83.448 ;
     RECT  42.515 48.96 43.121 70.296 ;
     RECT  43.117 83.424 43.157 83.784 ;
     RECT  42.865 3.12 43.189 5.352 ;
     RECT  42.589 11.424 43.189 11.832 ;
     RECT  42.997 71.328 43.189 75.864 ;
     RECT  42.437 77.472 43.189 78.168 ;
     RECT  43.121 48.96 43.193 60.408 ;
     RECT  43.189 3.12 43.225 5.688 ;
     RECT  42.221 6.72 43.225 7.656 ;
     RECT  43.013 79.44 43.229 80.232 ;
     RECT  43.121 61.824 43.297 70.296 ;
     RECT  43.189 71.328 43.297 78.168 ;
     RECT  43.225 3.12 43.333 7.656 ;
     RECT  42.977 9.12 43.333 9.144 ;
     RECT  43.081 33.12 43.369 35.352 ;
     RECT  42.757 36.624 43.369 36.888 ;
     RECT  43.333 3.12 43.373 9.144 ;
     RECT  43.297 61.824 43.373 78.168 ;
     RECT  43.373 3.12 43.379 8.568 ;
     RECT  43.369 33.12 43.405 35.592 ;
     RECT  43.369 36.624 43.405 37.704 ;
     RECT  43.049 30.816 43.409 31.8 ;
     RECT  43.373 72.768 43.409 78.168 ;
     RECT  43.379 7.248 43.417 8.568 ;
     RECT  43.373 61.824 43.445 71.544 ;
     RECT  43.193 48.96 43.475 60.264 ;
     RECT  42.797 38.688 43.513 41.256 ;
     RECT  42.797 42.24 43.513 42.6 ;
     RECT  43.475 48.96 43.513 59.16 ;
     RECT  43.229 79.44 43.513 79.848 ;
     RECT  43.409 72.864 43.517 78.168 ;
     RECT  43.517 72.864 43.553 77.736 ;
     RECT  42.977 43.776 43.621 47.688 ;
     RECT  43.553 72.864 43.733 77.304 ;
     RECT  43.621 14.256 43.765 14.28 ;
     RECT  42.761 15.264 43.765 21.192 ;
     RECT  43.405 33.12 43.801 37.704 ;
     RECT  43.513 38.688 43.801 42.6 ;
     RECT  43.475 60.24 43.805 60.264 ;
     RECT  42.844 81.456 43.805 82.248 ;
     RECT  43.379 3.12 43.837 6.12 ;
     RECT  42.581 13.056 43.877 13.08 ;
     RECT  43.049 25.104 43.877 29.592 ;
     RECT  43.733 72.864 43.877 75.672 ;
     RECT  43.445 70.8 43.913 71.544 ;
     RECT  43.877 72.864 43.913 75.24 ;
     RECT  43.513 22.8 44.017 22.824 ;
     RECT  44.017 22.272 44.125 22.824 ;
     RECT  43.157 83.76 44.161 83.784 ;
     RECT  43.837 2.256 44.237 6.12 ;
     RECT  43.049 23.856 44.341 23.88 ;
     RECT  43.409 31.536 44.341 31.8 ;
     RECT  43.801 33.12 44.341 42.6 ;
     RECT  44.237 2.256 44.345 5.352 ;
     RECT  43.417 7.248 44.381 7.944 ;
     RECT  43.765 14.256 44.381 21.192 ;
     RECT  43.733 76.752 44.417 77.304 ;
     RECT  44.381 7.248 44.449 7.272 ;
     RECT  44.125 22.224 44.449 22.824 ;
     RECT  44.341 23.808 44.449 23.88 ;
     RECT  44.381 15.12 44.453 21.192 ;
     RECT  43.877 25.632 44.485 29.592 ;
     RECT  43.445 61.824 44.485 69.432 ;
     RECT  43.913 70.8 44.485 70.824 ;
     RECT  43.913 72.864 44.485 74.664 ;
     RECT  44.345 2.256 44.489 4.392 ;
     RECT  44.449 6.864 44.489 7.272 ;
     RECT  44.485 61.824 44.521 69.528 ;
     RECT  44.485 72.768 44.521 74.664 ;
     RECT  44.489 6.864 44.561 6.888 ;
     RECT  44.449 22.224 44.561 23.88 ;
     RECT  44.341 31.536 44.597 42.6 ;
     RECT  44.597 33.12 44.633 42.6 ;
     RECT  44.161 82.848 44.633 83.784 ;
     RECT  44.485 25.632 44.737 30.072 ;
     RECT  43.189 11.424 44.773 11.928 ;
     RECT  44.417 77.136 44.78 77.304 ;
     RECT  43.621 43.776 44.953 47.88 ;
     RECT  43.513 48.912 44.953 59.16 ;
     RECT  44.633 38.208 44.965 42.6 ;
     RECT  44.485 70.656 44.965 70.824 ;
     RECT  44.521 71.856 44.965 74.664 ;
     RECT  42.757 0.048 45.061 0.312 ;
     RECT  44.521 61.632 45.061 69.528 ;
     RECT  44.965 70.656 45.061 74.664 ;
     RECT  43.513 79.2 45.205 79.848 ;
     RECT  43.805 81.456 45.205 81.48 ;
     RECT  44.633 82.848 45.205 83.256 ;
     RECT  44.629 9.792 45.212 9.816 ;
     RECT  44.773 10.8 45.212 11.928 ;
     RECT  44.78 77.136 45.241 77.784 ;
     RECT  45.205 79.2 45.241 83.256 ;
     RECT  45.061 0.048 45.341 0.552 ;
     RECT  44.377 60.624 45.349 60.648 ;
     RECT  45.061 61.632 45.349 74.664 ;
     RECT  44.453 15.264 45.421 21.192 ;
     RECT  44.965 38.208 45.457 42.696 ;
     RECT  44.953 43.776 45.457 59.16 ;
     RECT  44.737 25.632 45.493 30.12 ;
     RECT  44.597 31.536 45.493 31.944 ;
     RECT  44.489 2.256 45.608 4.104 ;
     RECT  45.529 6.096 45.608 6.12 ;
     RECT  45.233 8.496 45.608 8.52 ;
     RECT  45.212 9.792 45.608 11.928 ;
     RECT  45.421 14.64 45.608 21.192 ;
     RECT  44.561 22.272 45.608 23.88 ;
     RECT  45.493 25.632 45.608 31.944 ;
     RECT  44.633 33.552 45.608 37.08 ;
     RECT  45.457 38.208 45.608 59.16 ;
     RECT  45.349 60.624 45.608 74.664 ;
     RECT  45.241 77.136 45.608 83.256 ;
     RECT  45.608 2.148 45.712 88.572 ;
     RECT  45.341 0.048 45.889 0.6 ;
     RECT  45.712 2.148 45.904 88.302 ;
     RECT  45.889 0.048 45.973 0.648 ;
     RECT  45.904 12.528 46.019 18.84 ;
     RECT  45.904 75.696 46.145 78.12 ;
     RECT  45.904 25.104 46.211 30.888 ;
     RECT  45.904 71.088 46.217 74.712 ;
     RECT  45.904 19.824 46.259 21.912 ;
     RECT  45.904 31.92 46.361 32.184 ;
     RECT  45.904 2.148 46.501 6.36 ;
     RECT  46.211 25.104 46.505 25.128 ;
     RECT  45.904 58.704 46.505 59.064 ;
     RECT  45.904 60.24 46.505 70.104 ;
     RECT  46.217 72.72 46.577 74.712 ;
     RECT  45.904 79.2 46.649 82.44 ;
     RECT  46.211 26.352 46.721 30.888 ;
     RECT  46.505 62.208 46.787 70.104 ;
     RECT  45.904 8.016 46.865 11.4 ;
     RECT  45.904 33.504 46.969 51.144 ;
     RECT  45.904 52.464 46.969 57.432 ;
     RECT  46.505 58.704 46.969 58.728 ;
     RECT  46.019 13.104 47.005 18.84 ;
     RECT  46.649 82.176 47.077 82.44 ;
     RECT  45.904 83.52 47.077 83.592 ;
     RECT  46.787 62.496 47.117 70.104 ;
     RECT  46.501 1.728 47.149 6.36 ;
     RECT  46.865 8.016 47.149 9.048 ;
     RECT  46.577 72.816 47.149 74.712 ;
     RECT  46.361 32.064 47.189 32.184 ;
     RECT  46.259 19.824 47.221 21.768 ;
     RECT  46.217 71.088 47.257 71.688 ;
     RECT  47.149 1.728 47.261 9.048 ;
     RECT  47.005 13.056 47.261 18.84 ;
     RECT  47.077 82.176 47.297 83.592 ;
     RECT  46.969 33.504 47.333 51.48 ;
     RECT  47.261 3.12 47.369 9.048 ;
     RECT  47.333 33.648 47.401 51.48 ;
     RECT  46.969 52.464 47.401 58.728 ;
     RECT  47.261 15.12 47.473 18.84 ;
     RECT  47.221 19.824 47.473 21.96 ;
     RECT  45.904 23.088 47.473 23.688 ;
     RECT  47.117 62.496 47.507 68.424 ;
     RECT  47.473 15.12 47.509 23.688 ;
     RECT  46.721 26.352 47.509 30.84 ;
     RECT  46.145 76.368 47.509 78.12 ;
     RECT  46.649 79.2 47.509 81.048 ;
     RECT  47.509 76.368 47.545 81.048 ;
     RECT  47.545 76.176 47.549 81.048 ;
     RECT  47.507 62.496 47.555 68.184 ;
     RECT  45.973 0.048 47.612 0.6 ;
     RECT  47.261 1.728 47.612 1.8 ;
     RECT  47.549 78.384 47.761 81.048 ;
     RECT  47.297 82.176 47.761 82.728 ;
     RECT  47.369 3.12 47.765 8.04 ;
     RECT  47.765 3.12 47.801 7.08 ;
     RECT  47.369 9.024 47.833 9.048 ;
     RECT  46.865 10.128 47.833 11.4 ;
     RECT  47.509 25.92 47.833 30.84 ;
     RECT  47.189 32.064 47.833 32.088 ;
     RECT  47.401 33.648 47.833 58.728 ;
     RECT  46.505 60.24 47.833 61.224 ;
     RECT  47.257 71.088 47.852 71.736 ;
     RECT  47.149 72.816 47.852 75.144 ;
     RECT  47.261 13.056 47.909 13.992 ;
     RECT  47.833 33.648 47.909 59.208 ;
     RECT  47.852 71.088 47.939 75.144 ;
     RECT  47.509 15.12 47.945 23.928 ;
     RECT  47.801 3.168 48.017 7.08 ;
     RECT  47.833 9.024 48.085 11.4 ;
     RECT  47.833 60.24 48.157 61.512 ;
     RECT  47.612 0.048 48.179 1.8 ;
     RECT  47.909 38.208 48.233 59.208 ;
     RECT  48.233 38.256 48.265 59.208 ;
     RECT  48.157 60.24 48.265 62.232 ;
     RECT  47.555 63.216 48.269 68.184 ;
     RECT  48.179 0.048 48.275 1.128 ;
     RECT  47.939 72.816 48.301 75.144 ;
     RECT  47.549 76.176 48.301 77.16 ;
     RECT  47.909 33.648 48.337 37.032 ;
     RECT  48.085 9.024 48.373 11.448 ;
     RECT  47.117 69.408 48.373 70.104 ;
     RECT  47.939 71.088 48.373 71.736 ;
     RECT  47.909 13.488 48.409 13.992 ;
     RECT  47.945 15.12 48.409 21.72 ;
     RECT  48.409 13.488 48.441 21.72 ;
     RECT  48.269 67.2 48.481 68.184 ;
     RECT  47.833 25.92 48.521 32.088 ;
     RECT  47.761 78.384 48.593 82.728 ;
     RECT  48.521 25.92 48.697 29.592 ;
     RECT  48.017 5.184 48.769 7.08 ;
     RECT  48.481 67.2 48.845 68.232 ;
     RECT  48.301 72.816 48.845 77.16 ;
     RECT  48.373 69.408 48.913 71.736 ;
     RECT  48.441 15.264 48.985 21.72 ;
     RECT  47.945 22.704 48.985 23.928 ;
     RECT  48.845 72.816 48.989 72.84 ;
     RECT  48.441 13.488 49.025 14.28 ;
     RECT  48.913 68.976 49.025 71.736 ;
     RECT  48.265 38.256 49.057 62.232 ;
     RECT  48.269 63.216 49.057 65.784 ;
     RECT  48.017 3.168 49.129 4.152 ;
     RECT  48.769 5.184 49.129 7.128 ;
     RECT  49.025 69.12 49.133 71.736 ;
     RECT  48.593 78.672 49.133 82.728 ;
     RECT  49.129 3.168 49.141 7.128 ;
     RECT  48.373 8.16 49.141 11.448 ;
     RECT  48.985 15.264 49.165 23.928 ;
     RECT  48.697 25.056 49.165 29.592 ;
     RECT  48.845 74.064 49.205 77.16 ;
     RECT  49.141 3.168 49.228 11.448 ;
     RECT  48.337 33.216 49.273 37.032 ;
     RECT  49.057 38.256 49.273 65.784 ;
     RECT  49.133 70.656 49.273 71.736 ;
     RECT  49.228 8.16 49.349 11.448 ;
     RECT  48.521 30.72 49.349 32.088 ;
     RECT  49.205 74.448 49.349 77.16 ;
     RECT  49.133 79.152 49.349 82.728 ;
     RECT  49.349 74.592 49.381 77.16 ;
     RECT  49.349 81.6 49.381 82.728 ;
     RECT  49.349 30.72 49.457 31.752 ;
     RECT  49.133 69.12 49.529 69.528 ;
     RECT  48.845 67.2 49.532 67.848 ;
     RECT  49.273 33.216 49.621 65.784 ;
     RECT  49.165 15.264 49.637 29.592 ;
     RECT  49.349 79.152 49.673 80.376 ;
     RECT  49.637 15.264 49.709 24.264 ;
     RECT  49.457 31.392 49.745 31.752 ;
     RECT  49.381 74.592 49.781 77.4 ;
     RECT  49.228 3.168 49.813 7.128 ;
     RECT  49.025 14.256 49.813 14.28 ;
     RECT  49.709 15.264 49.813 23.4 ;
     RECT  49.621 33.024 49.817 65.784 ;
     RECT  48.275 0.048 49.849 0.216 ;
     RECT  49.813 2.88 49.853 7.128 ;
     RECT  49.381 81.6 49.853 83.256 ;
     RECT  49.817 63.072 49.957 65.784 ;
     RECT  49.532 66.912 49.957 67.848 ;
     RECT  49.349 9.024 49.961 11.448 ;
     RECT  49.637 25.488 49.993 29.592 ;
     RECT  49.129 13.056 50.173 13.224 ;
     RECT  49.813 14.256 50.173 23.4 ;
     RECT  49.273 70.656 50.197 72.456 ;
     RECT  50.173 13.056 50.425 23.4 ;
     RECT  49.781 74.592 50.425 75.192 ;
     RECT  49.781 76.176 50.533 77.4 ;
     RECT  50.533 76.176 50.569 77.544 ;
     RECT  49.673 80.352 50.569 80.376 ;
     RECT  49.853 81.6 50.569 82.536 ;
     RECT  50.569 76.176 50.605 77.928 ;
     RECT  49.673 79.152 50.605 79.176 ;
     RECT  49.957 63.072 50.641 67.848 ;
     RECT  49.529 69.12 50.641 69.432 ;
     RECT  49.849 0.048 50.713 0.264 ;
     RECT  49.993 25.488 50.713 30.12 ;
     RECT  50.197 70.656 50.713 73.224 ;
     RECT  50.713 0.048 50.725 0.312 ;
     RECT  49.745 31.392 50.725 31.704 ;
     RECT  49.817 33.024 50.725 62.04 ;
     RECT  50.713 70.656 50.725 73.272 ;
     RECT  50.425 74.352 50.725 75.192 ;
     RECT  50.425 12.816 50.749 23.4 ;
     RECT  50.725 31.392 50.821 62.04 ;
     RECT  50.641 63.072 50.821 69.432 ;
     RECT  50.749 12.816 50.869 23.928 ;
     RECT  50.713 25.152 50.869 30.12 ;
     RECT  50.605 76.176 50.869 79.176 ;
     RECT  50.569 80.352 50.869 82.536 ;
     RECT  49.853 2.88 51.001 2.904 ;
     RECT  51.001 2.832 51.008 2.904 ;
     RECT  49.853 4.128 51.008 7.128 ;
     RECT  49.961 9.024 51.008 9.288 ;
     RECT  49.961 10.368 51.008 11.448 ;
     RECT  50.869 12.816 51.008 30.12 ;
     RECT  50.821 31.392 51.008 69.432 ;
     RECT  50.725 70.656 51.008 75.192 ;
     RECT  50.869 76.176 51.008 82.536 ;
     RECT  50.492 88.368 51.008 88.392 ;
     RECT  51.008 2.148 51.112 88.572 ;
     RECT  51.112 2.418 51.304 88.302 ;
     RECT  51.304 8.4 51.329 11.976 ;
     RECT  51.304 70.896 51.365 77.4 ;
     RECT  51.304 43.728 51.401 49.32 ;
     RECT  51.365 70.896 51.401 71.976 ;
     RECT  51.401 43.728 51.473 47.448 ;
     RECT  51.365 72.96 51.545 77.4 ;
     RECT  51.473 43.728 51.653 47.4 ;
     RECT  51.304 2.832 51.833 7.416 ;
     RECT  51.304 30.672 51.905 42.744 ;
     RECT  51.905 31.248 51.941 42.744 ;
     RECT  51.304 79.152 52.049 79.752 ;
     RECT  51.401 70.896 52.085 71.832 ;
     RECT  51.833 2.832 52.193 5.208 ;
     RECT  51.304 80.784 52.265 80.808 ;
     RECT  52.049 79.584 52.301 79.752 ;
     RECT  51.304 13.296 52.369 16.824 ;
     RECT  51.304 18 52.369 21.672 ;
     RECT  51.304 26.592 52.369 29.592 ;
     RECT  51.401 48.528 52.369 49.32 ;
     RECT  52.369 13.296 52.405 21.672 ;
     RECT  51.304 23.904 52.445 23.928 ;
     RECT  51.304 65.424 52.445 69.528 ;
     RECT  52.085 70.896 52.477 71.784 ;
     RECT  51.304 24.912 52.549 25.128 ;
     RECT  52.445 65.424 52.589 69 ;
     RECT  52.405 13.296 52.621 21.96 ;
     RECT  51.545 72.96 52.621 77.16 ;
     RECT  52.621 12.96 52.691 21.96 ;
     RECT  51.833 6.24 52.693 7.416 ;
     RECT  51.329 8.4 52.693 8.424 ;
     RECT  51.941 32.4 52.693 42.744 ;
     RECT  51.653 43.872 52.693 47.4 ;
     RECT  51.329 9.84 52.739 11.976 ;
     RECT  52.369 26.16 52.765 29.592 ;
     RECT  52.369 48.432 52.769 49.32 ;
     RECT  52.769 48.432 52.801 48.936 ;
     RECT  52.691 18.48 52.837 21.96 ;
     RECT  51.304 50.592 52.837 63.624 ;
     RECT  52.693 6.24 52.841 8.424 ;
     RECT  52.837 18.48 52.945 22.008 ;
     RECT  52.693 32.4 52.945 47.4 ;
     RECT  52.801 48.384 52.945 48.936 ;
     RECT  52.477 70.08 52.985 71.784 ;
     RECT  51.941 31.248 53.017 31.272 ;
     RECT  52.739 9.84 53.021 10.776 ;
     RECT  52.739 11.952 53.021 11.976 ;
     RECT  52.193 3.264 53.057 5.208 ;
     RECT  52.837 50.592 53.057 64.056 ;
     RECT  53.021 9.84 53.077 10.728 ;
     RECT  53.057 50.592 53.089 62.568 ;
     RECT  52.945 32.4 53.093 48.936 ;
     RECT  52.841 7.104 53.123 8.424 ;
     RECT  53.057 63.6 53.129 64.056 ;
     RECT  53.093 32.4 53.161 33.048 ;
     RECT  52.691 12.96 53.197 17.16 ;
     RECT  53.129 64.032 53.197 64.056 ;
     RECT  52.589 65.424 53.197 68.952 ;
     RECT  53.123 7.104 53.201 7.848 ;
     RECT  53.089 50.4 53.273 62.568 ;
     RECT  52.549 24.48 53.341 25.128 ;
     RECT  52.765 26.16 53.341 30.072 ;
     RECT  53.077 9.696 53.345 10.728 ;
     RECT  53.161 32.352 53.381 33.048 ;
     RECT  53.201 7.776 53.417 7.848 ;
     RECT  53.341 24.48 53.441 30.072 ;
     RECT  53.017 31.248 53.441 31.368 ;
     RECT  52.621 72.96 53.453 77.688 ;
     RECT  53.441 24.48 53.485 31.368 ;
     RECT  53.197 12.048 53.525 17.16 ;
     RECT  53.485 23.952 53.525 31.368 ;
     RECT  52.301 79.728 53.561 79.752 ;
     RECT  53.093 34.176 53.669 48.936 ;
     RECT  52.985 70.08 53.669 70.152 ;
     RECT  53.417 7.824 53.705 7.848 ;
     RECT  53.453 76.368 53.708 77.688 ;
     RECT  53.485 78.672 53.708 78.696 ;
     RECT  52.945 18.48 53.737 22.392 ;
     RECT  53.057 3.264 53.777 4.2 ;
     RECT  53.708 76.368 53.795 78.696 ;
     RECT  53.345 9.84 53.813 10.728 ;
     RECT  53.197 64.032 53.885 68.952 ;
     RECT  53.525 23.952 53.921 30.072 ;
     RECT  53.737 18.24 54.029 22.776 ;
     RECT  53.453 72.96 54.029 75.288 ;
     RECT  53.669 38.496 54.085 48.936 ;
     RECT  53.525 15.264 54.097 17.16 ;
     RECT  54.029 18.24 54.097 18.504 ;
     RECT  53.777 3.408 54.133 4.2 ;
     RECT  53.485 5.712 54.133 5.736 ;
     RECT  52.985 71.184 54.133 71.784 ;
     RECT  54.029 72.96 54.137 74.136 ;
     RECT  53.795 78.672 54.169 78.696 ;
     RECT  54.169 78.672 54.209 79.272 ;
     RECT  53.885 64.032 54.241 68.568 ;
     RECT  54.241 63.888 54.245 68.568 ;
     RECT  54.085 38.496 54.277 49.224 ;
     RECT  53.273 50.4 54.277 62.328 ;
     RECT  53.921 25.344 54.281 30.072 ;
     RECT  50.725 0.048 54.419 0.36 ;
     RECT  53.813 9.84 54.421 10.68 ;
     RECT  54.419 0.096 54.457 0.36 ;
     RECT  53.525 31.248 54.457 31.368 ;
     RECT  53.381 32.448 54.457 33.048 ;
     RECT  54.38 6.768 54.467 6.792 ;
     RECT  54.457 0.096 54.524 0.552 ;
     RECT  54.029 19.824 54.529 22.776 ;
     RECT  54.133 70.416 54.529 71.784 ;
     RECT  54.137 72.96 54.529 74.088 ;
     RECT  54.421 9.648 54.569 10.68 ;
     RECT  54.569 9.648 54.601 10.344 ;
     RECT  54.524 0.096 54.611 1.128 ;
     RECT  54.245 63.888 54.637 68.424 ;
     RECT  54.529 19.824 54.677 22.824 ;
     RECT  54.029 75.216 54.677 75.288 ;
     RECT  54.281 26.544 54.709 30.072 ;
     RECT  54.457 31.248 54.709 33.048 ;
     RECT  53.669 34.176 54.709 37.464 ;
     RECT  54.277 38.496 54.709 62.328 ;
     RECT  54.709 34.176 54.745 62.328 ;
     RECT  53.921 23.952 54.749 23.976 ;
     RECT  54.745 34.08 54.785 62.328 ;
     RECT  54.637 63.6 54.821 68.424 ;
     RECT  54.709 26.544 54.857 33.048 ;
     RECT  54.529 70.416 54.857 74.088 ;
     RECT  54.857 31.248 54.893 33.048 ;
     RECT  54.209 79.104 54.893 79.272 ;
     RECT  54.313 80.928 54.899 80.952 ;
     RECT  54.853 82.08 54.937 82.104 ;
     RECT  54.893 31.248 54.965 31.416 ;
     RECT  53.525 12.048 55.069 14.232 ;
     RECT  54.677 75.216 55.145 75.24 ;
     RECT  54.281 25.344 55.213 25.368 ;
     RECT  54.857 72.24 55.217 74.088 ;
     RECT  55.069 11.952 55.249 14.232 ;
     RECT  54.785 48.576 55.249 62.328 ;
     RECT  55.249 11.472 55.257 14.232 ;
     RECT  54.097 15.264 55.257 18.504 ;
     RECT  54.601 8.88 55.285 10.344 ;
     RECT  55.249 48.576 55.285 62.568 ;
     RECT  54.821 63.6 55.285 68.136 ;
     RECT  55.217 72.24 55.325 73.464 ;
     RECT  54.893 32.448 55.357 33.048 ;
     RECT  54.785 34.08 55.357 47.592 ;
     RECT  54.133 3.408 55.361 5.736 ;
     RECT  54.677 19.824 55.361 22.776 ;
     RECT  55.285 8.544 55.397 10.344 ;
     RECT  53.795 76.368 55.433 76.92 ;
     RECT  55.105 78.096 55.433 78.12 ;
     RECT  55.397 9.648 55.537 10.344 ;
     RECT  55.257 11.472 55.537 18.504 ;
     RECT  55.213 25.056 55.573 25.368 ;
     RECT  54.857 26.544 55.573 30.168 ;
     RECT  54.611 0.096 55.58 0.552 ;
     RECT  55.58 0.096 55.645 1.128 ;
     RECT  55.501 2.256 55.645 2.28 ;
     RECT  55.537 9.648 55.645 18.504 ;
     RECT  55.361 19.824 55.645 21.096 ;
     RECT  55.669 7.392 55.717 7.416 ;
     RECT  55.357 32.448 55.813 47.592 ;
     RECT  55.285 48.576 55.813 68.136 ;
     RECT  54.893 79.104 55.933 79.128 ;
     RECT  54.857 70.416 55.997 71.256 ;
     RECT  55.361 22.272 56.005 22.776 ;
     RECT  55.573 25.056 56.005 30.168 ;
     RECT  56.005 22.272 56.041 23.112 ;
     RECT  56.005 24.816 56.041 30.168 ;
     RECT  54.965 31.296 56.041 31.416 ;
     RECT  55.933 79.104 56.041 79.176 ;
     RECT  56.041 22.272 56.149 23.4 ;
     RECT  56.041 24.816 56.149 31.416 ;
     RECT  55.813 32.448 56.149 68.136 ;
     RECT  56.149 22.272 56.245 23.592 ;
     RECT  56.149 24.816 56.245 68.136 ;
     RECT  56.245 22.272 56.329 68.136 ;
     RECT  55.645 0.096 56.405 2.28 ;
     RECT  56.405 2.016 56.408 2.28 ;
     RECT  55.361 3.408 56.408 4.248 ;
     RECT  55.717 6.288 56.408 7.416 ;
     RECT  55.397 8.544 56.408 8.568 ;
     RECT  55.645 9.648 56.408 21.096 ;
     RECT  56.329 22.272 56.408 68.424 ;
     RECT  55.997 70.128 56.408 71.256 ;
     RECT  55.325 72.24 56.408 73.272 ;
     RECT  55.933 74.64 56.408 74.712 ;
     RECT  55.825 75.744 56.408 75.768 ;
     RECT  55.433 76.896 56.408 76.92 ;
     RECT  56.041 78.912 56.408 79.176 ;
     RECT  55.177 81.216 56.408 81.48 ;
     RECT  56.405 0.096 56.435 0.504 ;
     RECT  56.408 2.016 56.512 88.572 ;
     RECT  56.435 0.096 56.627 0.408 ;
     RECT  56.512 2.016 56.704 88.302 ;
     RECT  56.704 2.016 56.723 2.28 ;
     RECT  56.723 2.064 56.819 2.28 ;
     RECT  56.704 70.656 56.819 78.936 ;
     RECT  56.704 9.84 56.873 20.712 ;
     RECT  56.873 9.84 56.909 17.448 ;
     RECT  56.704 67.44 56.909 68.424 ;
     RECT  56.819 70.656 56.981 74.712 ;
     RECT  56.819 2.064 57.011 2.088 ;
     RECT  56.909 9.84 57.017 17.304 ;
     RECT  56.704 22.272 57.197 65.928 ;
     RECT  56.981 70.656 57.203 74.568 ;
     RECT  56.704 6.288 57.305 8.856 ;
     RECT  56.627 0.096 57.593 0.264 ;
     RECT  56.819 76.32 57.593 78.936 ;
     RECT  57.197 22.608 57.676 65.928 ;
     RECT  57.203 70.656 57.701 71.304 ;
     RECT  57.676 24.24 57.737 65.928 ;
     RECT  57.737 24.24 57.773 62.232 ;
     RECT  57.773 49.584 57.809 62.232 ;
     RECT  57.593 0.096 57.827 0.216 ;
     RECT  57.809 50.16 57.827 62.232 ;
     RECT  57.737 63.36 57.877 65.928 ;
     RECT  56.704 3.408 57.881 5.064 ;
     RECT  57.773 24.24 57.953 48.456 ;
     RECT  56.704 79.968 57.953 79.992 ;
     RECT  57.827 0.192 57.971 0.216 ;
     RECT  57.593 77.184 57.985 78.936 ;
     RECT  56.909 67.44 58.165 68.28 ;
     RECT  58.057 69.408 58.165 69.432 ;
     RECT  56.704 81.12 58.165 81.144 ;
     RECT  57.305 7.392 58.169 8.856 ;
     RECT  56.873 18.48 58.201 20.712 ;
     RECT  57.827 50.304 58.205 62.232 ;
     RECT  58.201 18.48 58.273 21.288 ;
     RECT  57.203 72.432 58.273 74.568 ;
     RECT  57.305 6.288 58.309 6.312 ;
     RECT  58.169 7.392 58.309 7.704 ;
     RECT  57.676 22.608 58.313 23.112 ;
     RECT  58.165 81.12 58.313 82.008 ;
     RECT  57.017 9.84 58.385 17.208 ;
     RECT  58.309 6.288 58.453 7.704 ;
     RECT  58.165 67.44 58.489 69.432 ;
     RECT  57.701 70.656 58.489 71.256 ;
     RECT  58.169 8.832 58.493 8.856 ;
     RECT  58.385 15.936 58.525 17.208 ;
     RECT  57.881 3.408 58.529 5.016 ;
     RECT  57.953 24.24 58.601 30.504 ;
     RECT  58.205 50.304 58.601 61.944 ;
     RECT  57.877 63.36 58.669 66.12 ;
     RECT  58.273 72.432 58.669 74.616 ;
     RECT  57.805 75.84 58.669 76.2 ;
     RECT  58.313 81.984 58.673 82.008 ;
     RECT  58.669 72.288 58.693 74.616 ;
     RECT  58.669 75.696 58.693 76.2 ;
     RECT  58.385 9.84 58.705 14.472 ;
     RECT  58.525 15.936 58.705 17.4 ;
     RECT  58.669 63.36 58.705 66.312 ;
     RECT  58.489 67.44 58.705 71.256 ;
     RECT  58.601 24.24 58.745 24.552 ;
     RECT  58.693 72.288 58.789 76.2 ;
     RECT  57.985 77.184 58.789 79.176 ;
     RECT  57.953 31.536 58.813 48.456 ;
     RECT  58.789 72.288 58.835 79.176 ;
     RECT  58.705 63.36 58.844 71.256 ;
     RECT  58.835 72.288 58.844 76.968 ;
     RECT  58.705 9.072 58.853 14.472 ;
     RECT  58.601 50.304 58.853 50.616 ;
     RECT  58.777 80.928 58.861 80.952 ;
     RECT  58.813 31.536 58.885 48.696 ;
     RECT  58.705 15.936 59.173 17.448 ;
     RECT  58.273 18.48 59.173 21.528 ;
     RECT  58.601 51.648 59.173 61.944 ;
     RECT  58.844 63.36 59.173 76.968 ;
     RECT  59.173 15.936 59.267 21.528 ;
     RECT  58.835 78.048 59.321 79.176 ;
     RECT  59.321 78.624 59.389 79.176 ;
     RECT  59.281 80.16 59.389 80.184 ;
     RECT  59.267 18.432 59.393 21.528 ;
     RECT  58.601 25.584 59.425 30.504 ;
     RECT  58.885 31.536 59.425 48.984 ;
     RECT  59.393 18.432 59.501 21.48 ;
     RECT  58.529 3.696 59.509 5.016 ;
     RECT  58.453 6.24 59.509 7.704 ;
     RECT  58.313 22.8 59.533 23.112 ;
     RECT  58.853 9.072 59.555 14.232 ;
     RECT  59.509 3.696 59.596 7.704 ;
     RECT  59.501 21.456 59.609 21.48 ;
     RECT  59.173 51.648 59.609 76.968 ;
     RECT  58.853 50.4 59.641 50.616 ;
     RECT  59.609 51.648 59.641 64.344 ;
     RECT  59.596 6.24 59.645 7.704 ;
     RECT  59.555 9.072 59.645 12.12 ;
     RECT  59.425 25.584 59.681 48.984 ;
     RECT  59.641 50.4 59.681 64.344 ;
     RECT  59.681 25.584 59.789 48.696 ;
     RECT  59.789 25.584 59.897 37.08 ;
     RECT  59.789 38.112 59.933 48.696 ;
     RECT  59.609 65.328 59.933 76.968 ;
     RECT  59.555 13.296 59.965 14.232 ;
     RECT  59.596 3.696 59.969 4.92 ;
     RECT  59.533 22.752 60.073 23.112 ;
     RECT  58.745 24.24 60.073 24.264 ;
     RECT  60.073 22.752 60.077 24.264 ;
     RECT  59.645 9.648 60.221 12.12 ;
     RECT  59.681 50.4 60.257 63.816 ;
     RECT  59.897 25.584 60.293 33.144 ;
     RECT  59.965 13.296 60.361 14.712 ;
     RECT  59.267 15.936 60.361 17.448 ;
     RECT  60.361 13.296 60.373 17.448 ;
     RECT  59.501 18.432 60.373 20.472 ;
     RECT  59.933 65.328 60.401 74.136 ;
     RECT  60.401 65.328 60.419 73.272 ;
     RECT  60.077 22.752 60.437 24.216 ;
     RECT  59.389 78.624 60.509 80.184 ;
     RECT  59.933 75.264 60.577 76.968 ;
     RECT  60.293 25.584 60.581 33.048 ;
     RECT  60.509 78.624 60.581 79.896 ;
     RECT  60.419 70.8 60.653 73.272 ;
     RECT  60.257 50.4 60.721 57.96 ;
     RECT  60.257 59.232 60.725 63.816 ;
     RECT  59.645 6.768 60.757 7.704 ;
     RECT  60.653 70.848 60.761 73.272 ;
     RECT  59.933 38.256 60.833 48.696 ;
     RECT  60.373 13.296 60.937 20.472 ;
     RECT  59.969 4.176 60.973 4.92 ;
     RECT  60.649 25.296 60.973 25.32 ;
     RECT  60.937 13.296 60.997 21.144 ;
     RECT  60.973 4.176 61.052 5.016 ;
     RECT  60.757 6.576 61.052 7.704 ;
     RECT  60.721 50.112 61.261 57.96 ;
     RECT  60.419 65.328 61.297 69.576 ;
     RECT  60.437 22.848 61.405 24.216 ;
     RECT  60.973 25.2 61.405 25.32 ;
     RECT  61.052 4.176 61.477 7.704 ;
     RECT  60.221 9.648 61.477 10.68 ;
     RECT  60.221 12.096 61.513 12.12 ;
     RECT  61.261 50.112 61.513 58.152 ;
     RECT  60.725 59.232 61.513 62.136 ;
     RECT  60.833 45.456 61.549 48.696 ;
     RECT  61.513 49.824 61.549 62.136 ;
     RECT  61.477 4.176 61.573 10.68 ;
     RECT  61.573 4.176 61.585 10.872 ;
     RECT  61.405 22.848 61.585 25.32 ;
     RECT  61.585 22.848 61.657 25.416 ;
     RECT  60.581 26.448 61.657 33.048 ;
     RECT  59.897 34.176 61.669 37.08 ;
     RECT  60.833 38.256 61.669 38.28 ;
     RECT  60.577 75.264 61.693 77.544 ;
     RECT  60.761 70.848 61.729 71.4 ;
     RECT  60.761 72.864 61.729 73.272 ;
     RECT  61.585 3.696 61.808 10.872 ;
     RECT  61.513 12.048 61.808 12.12 ;
     RECT  60.997 13.296 61.808 21.672 ;
     RECT  61.657 22.848 61.808 33.048 ;
     RECT  61.669 34.176 61.808 38.28 ;
     RECT  60.833 39.408 61.808 44.136 ;
     RECT  61.549 45.456 61.808 62.136 ;
     RECT  60.725 63.12 61.808 63.816 ;
     RECT  61.297 64.944 61.808 69.576 ;
     RECT  61.729 70.848 61.808 73.272 ;
     RECT  61.693 75.216 61.808 77.544 ;
     RECT  60.581 78.72 61.808 79.896 ;
     RECT  59.821 81.888 61.808 81.912 ;
     RECT  61.808 2.148 61.912 88.572 ;
     RECT  61.912 2.418 62.104 88.302 ;
     RECT  62.104 15.216 62.201 21.144 ;
     RECT  62.104 6.576 62.237 8.136 ;
     RECT  62.104 3.696 62.309 5.496 ;
     RECT  62.237 6.576 62.309 7.128 ;
     RECT  62.309 6.576 62.453 6.984 ;
     RECT  62.201 15.312 62.453 21.144 ;
     RECT  62.104 22.32 62.561 30.84 ;
     RECT  62.453 15.312 62.669 19.992 ;
     RECT  62.309 5.472 62.705 5.496 ;
     RECT  62.104 70.656 62.741 73.32 ;
     RECT  62.309 3.696 62.777 4.2 ;
     RECT  62.104 9.12 62.777 10.392 ;
     RECT  62.669 19.536 62.777 19.992 ;
     RECT  62.104 38.736 62.777 47.4 ;
     RECT  62.104 75.216 62.813 77.304 ;
     RECT  62.777 44.016 62.849 47.4 ;
     RECT  62.561 22.8 62.885 30.84 ;
     RECT  62.813 75.216 62.885 77.16 ;
     RECT  62.104 78.336 63.011 79.992 ;
     RECT  62.849 45.408 63.029 47.4 ;
     RECT  63.011 78.768 63.052 79.992 ;
     RECT  62.104 81.36 63.052 82.152 ;
     RECT  63.029 45.504 63.065 47.4 ;
     RECT  62.104 67.44 63.097 69.48 ;
     RECT  62.741 70.656 63.097 71.16 ;
     RECT  62.741 72.336 63.097 73.32 ;
     RECT  62.777 38.736 63.173 43.032 ;
     RECT  63.065 45.792 63.205 47.4 ;
     RECT  62.104 48.384 63.205 58.44 ;
     RECT  62.104 63.648 63.205 63.672 ;
     RECT  63.097 67.44 63.209 71.16 ;
     RECT  62.104 59.568 63.241 59.592 ;
     RECT  62.104 60.816 63.241 62.568 ;
     RECT  62.885 22.8 63.245 30.792 ;
     RECT  63.052 81.36 63.245 81.432 ;
     RECT  63.205 45.792 63.277 58.44 ;
     RECT  63.241 59.568 63.277 62.568 ;
     RECT  63.245 26.784 63.281 30.792 ;
     RECT  63.277 45.792 63.281 62.568 ;
     RECT  63.097 10.848 63.301 10.872 ;
     RECT  62.104 65.424 63.301 66.36 ;
     RECT  63.209 67.44 63.301 71.112 ;
     RECT  62.104 13.296 63.308 14.232 ;
     RECT  62.669 15.312 63.308 18.504 ;
     RECT  63.301 65.424 63.317 71.112 ;
     RECT  63.052 78.768 63.317 79.224 ;
     RECT  63.317 71.088 63.345 71.112 ;
     RECT  63.317 65.424 63.347 70.008 ;
     RECT  63.245 81.36 63.353 81.384 ;
     RECT  63.347 65.424 63.421 69.528 ;
     RECT  63.421 64.896 63.497 69.528 ;
     RECT  63.281 58.992 63.529 62.568 ;
     RECT  63.205 63.6 63.529 63.672 ;
     RECT  62.849 44.016 63.539 44.136 ;
     RECT  62.453 6.624 63.565 6.936 ;
     RECT  62.777 3.696 63.589 4.104 ;
     RECT  62.104 32.592 63.601 33.048 ;
     RECT  62.104 34.176 63.601 37.752 ;
     RECT  62.104 12.048 63.641 12.072 ;
     RECT  63.565 6.432 63.677 6.936 ;
     RECT  62.237 8.112 63.677 8.136 ;
     RECT  63.301 10.848 63.677 11.064 ;
     RECT  62.885 75.216 63.677 76.968 ;
     RECT  63.241 0.192 63.709 0.216 ;
     RECT  62.777 19.632 63.709 19.992 ;
     RECT  62.453 20.976 63.709 21.144 ;
     RECT  63.281 45.792 63.713 57.912 ;
     RECT  63.245 22.8 63.745 25.608 ;
     RECT  63.713 45.792 63.785 50.184 ;
     RECT  63.308 13.296 63.853 18.504 ;
     RECT  63.601 32.592 63.853 37.752 ;
     RECT  63.853 31.968 63.877 37.752 ;
     RECT  63.173 38.736 63.877 38.808 ;
     RECT  63.097 72.336 63.893 73.896 ;
     RECT  63.317 78.768 63.893 78.792 ;
     RECT  63.529 58.992 63.965 63.672 ;
     RECT  63.709 0.048 63.997 0.216 ;
     RECT  62.777 9.12 64.001 9.864 ;
     RECT  63.877 31.968 64.001 38.808 ;
     RECT  63.997 0.048 64.033 0.264 ;
     RECT  64.001 31.968 64.033 37.032 ;
     RECT  63.965 62.544 64.033 63.672 ;
     RECT  63.497 64.896 64.033 67.704 ;
     RECT  63.677 6.432 64.109 6.84 ;
     RECT  63.785 45.792 64.109 48.792 ;
     RECT  64.033 62.544 64.109 67.704 ;
     RECT  63.677 76.944 64.109 76.968 ;
     RECT  63.709 19.632 64.141 21.144 ;
     RECT  63.173 39.792 64.141 43.032 ;
     RECT  63.853 13.056 64.145 18.504 ;
     RECT  64.141 19.488 64.177 21.144 ;
     RECT  63.893 72.816 64.213 73.896 ;
     RECT  63.677 75.216 64.213 75.528 ;
     RECT  64.213 72.816 64.259 75.528 ;
     RECT  64.001 38.016 64.285 38.808 ;
     RECT  64.141 39.792 64.285 43.656 ;
     RECT  64.145 13.296 64.357 18.504 ;
     RECT  64.177 19.488 64.357 21.432 ;
     RECT  63.745 22.512 64.357 25.608 ;
     RECT  63.965 58.992 64.361 61.56 ;
     RECT  64.357 13.296 64.403 25.608 ;
     RECT  63.713 51.168 64.429 57.912 ;
     RECT  64.001 9.36 64.433 9.864 ;
     RECT  64.403 13.296 64.433 19.512 ;
     RECT  63.497 68.928 64.501 69.528 ;
     RECT  64.321 70.56 64.501 70.584 ;
     RECT  64.109 67.248 64.537 67.704 ;
     RECT  64.501 68.928 64.537 70.584 ;
     RECT  64.285 38.016 64.541 43.656 ;
     RECT  63.785 50.064 64.541 50.184 ;
     RECT  64.259 72.816 64.541 74.616 ;
     RECT  64.109 62.544 64.577 65.784 ;
     RECT  64.537 67.248 64.577 70.584 ;
     RECT  64.433 15.312 64.649 19.512 ;
     RECT  64.541 39.216 64.721 43.656 ;
     RECT  64.109 6.528 64.757 6.84 ;
     RECT  64.403 20.592 64.793 25.608 ;
     RECT  64.109 45.792 64.897 47.592 ;
     RECT  64.793 24.48 64.933 25.608 ;
     RECT  63.281 26.784 64.933 30.456 ;
     RECT  64.577 67.44 64.937 70.584 ;
     RECT  64.541 50.16 64.961 50.184 ;
     RECT  64.429 51.168 64.961 58.152 ;
     RECT  64.541 72.816 64.973 73.896 ;
     RECT  63.589 3.168 65.005 4.104 ;
     RECT  64.361 59.184 65.081 61.56 ;
     RECT  64.897 45.36 65.221 47.592 ;
     RECT  64.109 48.672 65.221 48.792 ;
     RECT  64.577 64.896 65.221 65.784 ;
     RECT  64.433 13.296 65.257 14.184 ;
     RECT  65.005 2.88 65.261 4.104 ;
     RECT  64.721 39.216 65.267 42.648 ;
     RECT  65.267 39.216 65.297 40.824 ;
     RECT  63.677 10.848 65.329 10.968 ;
     RECT  65.329 10.848 65.333 11.496 ;
     RECT  65.297 39.792 65.333 40.824 ;
     RECT  64.433 9.36 65.365 9.624 ;
     RECT  64.721 43.632 65.365 43.656 ;
     RECT  64.649 15.504 65.369 19.512 ;
     RECT  65.081 59.568 65.369 61.56 ;
     RECT  65.369 59.808 65.401 61.56 ;
     RECT  64.577 62.544 65.401 63.816 ;
     RECT  64.033 31.488 65.477 37.032 ;
     RECT  65.365 43.632 65.545 43.896 ;
     RECT  65.221 45.36 65.545 48.792 ;
     RECT  64.793 20.592 65.549 23.352 ;
     RECT  65.401 59.808 65.581 63.816 ;
     RECT  65.221 64.896 65.581 66.12 ;
     RECT  65.369 15.648 65.585 19.512 ;
     RECT  64.757 6.528 65.621 6.552 ;
     RECT  64.933 24.48 65.657 30.456 ;
     RECT  64.937 67.44 65.657 70.296 ;
     RECT  65.267 41.952 65.689 42.648 ;
     RECT  65.545 43.632 65.689 48.792 ;
     RECT  65.689 41.952 65.693 48.792 ;
     RECT  64.973 72.816 65.693 73.272 ;
     RECT  65.657 67.44 65.729 67.704 ;
     RECT  64.961 50.16 65.765 58.152 ;
     RECT  65.333 10.944 65.801 11.496 ;
     RECT  65.549 20.592 65.833 21.432 ;
     RECT  65.333 39.792 65.837 40.2 ;
     RECT  65.765 50.16 65.837 57.96 ;
     RECT  65.837 39.792 65.873 40.104 ;
     RECT  65.657 68.688 65.909 70.296 ;
     RECT  65.801 10.944 66.125 10.968 ;
     RECT  65.549 22.512 66.161 23.352 ;
     RECT  65.873 39.792 66.161 39.912 ;
     RECT  65.693 41.952 66.161 48.744 ;
     RECT  65.837 50.16 66.197 50.184 ;
     RECT  65.261 2.88 66.229 2.904 ;
     RECT  64.541 38.016 66.233 38.04 ;
     RECT  66.229 2.88 66.337 2.952 ;
     RECT  66.337 2.784 66.373 2.952 ;
     RECT  65.261 4.032 66.373 4.104 ;
     RECT  66.373 2.784 66.409 4.104 ;
     RECT  65.221 5.424 66.409 5.448 ;
     RECT  65.365 8.544 66.428 9.624 ;
     RECT  65.257 12.864 66.481 14.184 ;
     RECT  65.585 15.648 66.481 18.504 ;
     RECT  66.161 23.136 66.661 23.352 ;
     RECT  65.657 24.48 66.661 29.688 ;
     RECT  65.909 68.928 66.661 70.296 ;
     RECT  65.729 67.68 66.709 67.704 ;
     RECT  65.581 59.808 66.841 66.12 ;
     RECT  65.477 31.488 66.913 36.6 ;
     RECT  66.409 2.784 66.949 5.448 ;
     RECT  66.301 6.816 66.949 6.84 ;
     RECT  66.661 68.928 66.949 70.68 ;
     RECT  64.933 71.76 66.949 71.784 ;
     RECT  66.161 39.888 67.057 39.912 ;
     RECT  66.913 31.104 67.165 36.6 ;
     RECT  66.949 2.784 67.208 6.84 ;
     RECT  66.428 8.16 67.208 9.624 ;
     RECT  66.481 12.864 67.208 18.504 ;
     RECT  65.833 20.352 67.208 21.432 ;
     RECT  66.661 23.136 67.208 29.688 ;
     RECT  67.165 30.672 67.208 36.6 ;
     RECT  66.337 38.784 67.208 38.808 ;
     RECT  67.057 39.888 67.208 40.632 ;
     RECT  66.161 41.952 67.208 44.472 ;
     RECT  66.161 45.696 67.208 48.744 ;
     RECT  66.913 49.776 67.208 49.8 ;
     RECT  65.837 51.216 67.208 57.96 ;
     RECT  66.841 59.28 67.208 66.12 ;
     RECT  66.709 67.392 67.208 67.704 ;
     RECT  66.949 68.928 67.208 71.784 ;
     RECT  65.693 73.248 67.208 73.272 ;
     RECT  67.208 2.148 67.312 88.572 ;
     RECT  64.033 0.048 67.417 0.408 ;
     RECT  67.312 2.148 67.504 88.302 ;
     RECT  67.504 3.408 67.645 6.84 ;
     RECT  67.504 13.008 67.709 19.368 ;
     RECT  67.709 13.296 67.745 19.368 ;
     RECT  67.504 40.608 67.745 48.744 ;
     RECT  67.504 59.28 67.745 62.472 ;
     RECT  67.504 25.2 67.763 33.576 ;
     RECT  67.645 6.288 67.811 6.84 ;
     RECT  67.811 6.816 67.853 6.84 ;
     RECT  67.504 66.864 67.897 68.376 ;
     RECT  67.504 38.208 67.961 39.384 ;
     RECT  67.504 49.776 67.961 57.96 ;
     RECT  67.645 3.408 67.997 4.968 ;
     RECT  67.997 3.696 68.003 4.968 ;
     RECT  67.745 13.296 68.105 15.576 ;
     RECT  67.961 51.216 68.105 57.96 ;
     RECT  67.885 1.968 68.243 1.992 ;
     RECT  67.504 69.744 68.321 70.152 ;
     RECT  67.504 63.6 68.485 65.784 ;
     RECT  67.961 39.36 68.641 39.384 ;
     RECT  67.745 40.608 68.641 48.648 ;
     RECT  68.105 15.312 68.713 15.576 ;
     RECT  67.745 16.56 68.713 19.368 ;
     RECT  67.504 11.808 68.773 11.928 ;
     RECT  68.105 13.296 68.773 14.28 ;
     RECT  68.485 63.216 68.785 65.784 ;
     RECT  67.897 66.864 68.785 67.416 ;
     RECT  67.417 0.048 68.789 0.6 ;
     RECT  67.961 38.208 68.825 38.232 ;
     RECT  68.641 39.36 68.927 48.648 ;
     RECT  67.961 49.776 68.927 50.136 ;
     RECT  68.003 4.176 68.929 4.968 ;
     RECT  67.763 25.2 68.929 29.016 ;
     RECT  67.763 30 68.929 33.576 ;
     RECT  67.504 35.328 68.929 36.6 ;
     RECT  68.929 4.176 68.965 5.208 ;
     RECT  68.105 51.216 68.965 53.4 ;
     RECT  67.504 8.016 69.001 8.04 ;
     RECT  67.504 9.264 69.001 9.288 ;
     RECT  68.929 34.848 69.001 36.6 ;
     RECT  68.927 39.36 69.001 50.136 ;
     RECT  68.965 51.168 69.001 53.4 ;
     RECT  68.105 54.48 69.001 57.96 ;
     RECT  67.745 59.28 69.001 62.232 ;
     RECT  68.924 2.64 69.011 2.664 ;
     RECT  67.504 20.592 69.041 23.256 ;
     RECT  68.965 4.032 69.073 5.208 ;
     RECT  69.001 39.36 69.077 53.4 ;
     RECT  68.929 25.2 69.145 33.576 ;
     RECT  69.077 39.6 69.145 53.4 ;
     RECT  69.001 54.48 69.145 62.232 ;
     RECT  69.145 24.576 69.217 33.576 ;
     RECT  68.821 6.816 69.253 6.84 ;
     RECT  69.001 8.016 69.253 9.288 ;
     RECT  69.253 6.816 69.325 9.288 ;
     RECT  67.504 10.704 69.325 10.728 ;
     RECT  68.773 11.808 69.397 14.28 ;
     RECT  68.713 15.312 69.397 19.368 ;
     RECT  68.789 0.096 69.401 0.6 ;
     RECT  69.145 39.6 69.401 62.232 ;
     RECT  68.321 70.128 69.401 70.152 ;
     RECT  69.073 3.984 69.469 5.208 ;
     RECT  69.041 20.592 69.541 23.208 ;
     RECT  69.401 39.888 69.58 62.232 ;
     RECT  69.541 20.544 69.581 23.208 ;
     RECT  69.217 24.336 69.581 33.576 ;
     RECT  69.581 20.544 69.587 21.576 ;
     RECT  69.58 50.4 69.587 62.232 ;
     RECT  68.785 63.216 69.587 67.416 ;
     RECT  69.397 11.808 69.649 19.368 ;
     RECT  69.587 20.544 69.649 21.432 ;
     RECT  69.001 34.848 69.649 37.368 ;
     RECT  69.649 11.808 69.653 21.432 ;
     RECT  69.587 59.28 69.685 62.232 ;
     RECT  69.587 63.216 69.685 65.784 ;
     RECT  69.587 66.864 69.725 67.416 ;
     RECT  69.325 6.816 69.829 10.728 ;
     RECT  69.581 22.8 69.833 23.208 ;
     RECT  69.829 6.672 69.877 10.728 ;
     RECT  69.469 3.936 69.901 5.208 ;
     RECT  69.877 6.288 69.901 10.728 ;
     RECT  69.649 34.224 69.973 37.368 ;
     RECT  69.901 3.936 70.009 10.728 ;
     RECT  70.009 3.36 70.053 10.728 ;
     RECT  69.653 11.808 70.053 19.08 ;
     RECT  69.937 68.352 70.081 68.376 ;
     RECT  69.425 1.728 70.085 1.8 ;
     RECT  69.587 50.4 70.121 58.152 ;
     RECT  70.053 3.36 70.229 19.08 ;
     RECT  70.229 5.568 70.301 19.08 ;
     RECT  70.301 6.288 70.373 19.08 ;
     RECT  70.081 68.352 70.373 68.952 ;
     RECT  69.833 22.896 70.405 23.208 ;
     RECT  69.58 39.888 70.481 48.984 ;
     RECT  69.973 34.224 70.589 38.232 ;
     RECT  69.725 66.864 70.645 67.272 ;
     RECT  70.481 39.888 70.657 48.216 ;
     RECT  70.373 9.072 70.693 19.08 ;
     RECT  69.653 20.304 70.693 21.432 ;
     RECT  70.085 1.776 70.697 1.8 ;
     RECT  70.693 9.072 70.733 21.432 ;
     RECT  69.685 59.28 70.733 65.784 ;
     RECT  70.121 54.96 70.909 58.152 ;
     RECT  70.733 59.28 70.909 65.688 ;
     RECT  70.657 39.312 70.913 48.216 ;
     RECT  70.229 3.36 71.009 4.536 ;
     RECT  70.373 68.352 71.057 68.376 ;
     RECT  70.405 22.896 71.161 23.256 ;
     RECT  69.581 24.336 71.161 33.144 ;
     RECT  67.504 73.248 71.171 73.272 ;
     RECT  71.009 2.832 71.197 4.536 ;
     RECT  70.733 10.224 71.197 21.432 ;
     RECT  71.161 22.896 71.197 33.144 ;
     RECT  70.121 50.4 71.197 53.928 ;
     RECT  70.645 66.768 71.269 67.272 ;
     RECT  71.197 10.224 71.273 33.144 ;
     RECT  70.913 39.312 71.305 39.384 ;
     RECT  70.373 6.288 71.345 8.04 ;
     RECT  70.913 40.56 71.404 48.216 ;
     RECT  71.404 40.56 71.417 42.456 ;
     RECT  70.589 34.224 71.453 37.368 ;
     RECT  71.197 50.4 71.509 53.976 ;
     RECT  70.909 54.96 71.509 65.688 ;
     RECT  71.197 2.64 71.525 5.208 ;
     RECT  71.417 40.56 71.597 42.264 ;
     RECT  71.525 3.648 71.603 5.208 ;
     RECT  69.401 0.096 71.845 0.552 ;
     RECT  71.404 44.016 71.845 48.216 ;
     RECT  71.845 44.016 71.881 48.264 ;
     RECT  71.509 50.4 71.953 65.688 ;
     RECT  71.269 66.768 71.953 67.416 ;
     RECT  71.881 44.016 71.989 48.936 ;
     RECT  71.953 50.4 71.989 67.416 ;
     RECT  70.733 9.072 72.025 9.096 ;
     RECT  71.273 10.224 72.025 19.368 ;
     RECT  71.881 68.64 72.025 68.664 ;
     RECT  71.269 69.648 72.025 69.672 ;
     RECT  71.845 0.096 72.109 0.6 ;
     RECT  71.345 6.816 72.241 8.04 ;
     RECT  72.025 9.072 72.241 19.368 ;
     RECT  71.603 3.936 72.277 5.208 ;
     RECT  71.273 20.544 72.277 33.144 ;
     RECT  72.241 6.816 72.349 19.368 ;
     RECT  72.277 20.544 72.349 33.24 ;
     RECT  72.349 6.816 72.373 33.24 ;
     RECT  71.453 34.224 72.373 37.176 ;
     RECT  71.989 44.016 72.457 67.416 ;
     RECT  71.525 2.64 72.485 2.664 ;
     RECT  72.025 68.64 72.529 69.672 ;
     RECT  72.485 1.728 72.601 2.664 ;
     RECT  72.277 3.936 72.601 5.256 ;
     RECT  72.601 1.728 72.608 5.256 ;
     RECT  72.373 6.816 72.608 37.176 ;
     RECT  71.305 38.4 72.608 39.384 ;
     RECT  71.597 40.56 72.608 42.216 ;
     RECT  72.457 43.536 72.608 67.416 ;
     RECT  72.529 68.448 72.608 69.672 ;
     RECT  72.608 1.728 72.712 88.572 ;
     RECT  72.712 1.728 72.904 88.302 ;
     RECT  72.109 0.096 72.947 0.552 ;
     RECT  72.904 68.448 72.965 69.48 ;
     RECT  72.904 11.472 73.001 18.504 ;
     RECT  72.904 8.496 73.081 9.624 ;
     RECT  72.904 51.168 73.109 66.792 ;
     RECT  72.965 68.448 73.109 68.904 ;
     RECT  72.904 24.24 73.181 28.872 ;
     RECT  73.109 59.808 73.181 66.792 ;
     RECT  72.904 29.856 73.217 30.216 ;
     RECT  72.904 39.648 73.541 48.984 ;
     RECT  73.181 24.24 73.577 24.984 ;
     RECT  73.109 51.168 73.613 58.68 ;
     RECT  72.947 0.096 73.721 0.408 ;
     RECT  73.181 59.856 73.757 66.792 ;
     RECT  72.904 1.728 73.829 1.752 ;
     RECT  73.181 26.112 73.829 28.872 ;
     RECT  72.904 35.664 73.897 38.424 ;
     RECT  73.541 39.648 73.897 42.168 ;
     RECT  73.757 63.264 73.897 66.792 ;
     RECT  72.904 2.832 73.901 5.592 ;
     RECT  73.081 8.784 73.957 9.624 ;
     RECT  73.109 68.88 73.957 68.904 ;
     RECT  72.904 19.92 73.973 23.256 ;
     RECT  73.957 68.88 74.044 69.672 ;
     RECT  73.957 8.784 74.045 9.768 ;
     RECT  73.897 35.664 74.045 42.168 ;
     RECT  73.901 4.656 74.081 5.592 ;
     RECT  72.904 6.912 74.113 7.416 ;
     RECT  74.045 8.784 74.113 9.72 ;
     RECT  73.541 43.344 74.149 48.984 ;
     RECT  73.613 51.168 74.149 58.152 ;
     RECT  73.973 20.064 74.185 23.256 ;
     RECT  73.897 63.264 74.252 67.608 ;
     RECT  74.044 68.88 74.252 68.904 ;
     RECT  74.149 43.344 74.261 58.152 ;
     RECT  73.901 2.832 74.293 3.24 ;
     RECT  74.113 6.912 74.297 9.72 ;
     RECT  74.252 63.264 74.339 68.904 ;
     RECT  73.721 0.096 74.441 0.36 ;
     RECT  73.577 24.528 74.513 24.984 ;
     RECT  74.045 35.664 74.533 37.608 ;
     RECT  74.297 6.912 74.545 6.936 ;
     RECT  74.045 39.072 74.581 42.168 ;
     RECT  74.261 43.344 74.581 49.608 ;
     RECT  74.513 24.528 74.585 24.648 ;
     RECT  74.533 35.52 74.585 37.608 ;
     RECT  73.001 11.76 74.617 18.504 ;
     RECT  73.829 26.64 74.621 28.872 ;
     RECT  74.617 11.76 74.689 18.6 ;
     RECT  74.185 20.064 74.693 23.4 ;
     RECT  74.339 63.264 74.723 67.608 ;
     RECT  73.757 59.856 74.725 62.28 ;
     RECT  74.693 20.496 74.729 23.4 ;
     RECT  74.723 64.752 74.765 67.608 ;
     RECT  74.581 39.072 74.801 49.608 ;
     RECT  74.441 0.096 74.837 0.168 ;
     RECT  74.621 26.64 74.905 26.664 ;
     RECT  74.293 2.544 74.941 3.24 ;
     RECT  74.723 63.264 74.945 63.624 ;
     RECT  73.217 30.096 74.977 30.216 ;
     RECT  72.904 31.2 74.977 34.392 ;
     RECT  74.977 30.096 75.013 34.392 ;
     RECT  74.585 35.52 75.013 36.456 ;
     RECT  74.837 0.144 75.017 0.168 ;
     RECT  74.689 11.76 75.049 18.792 ;
     RECT  74.585 37.584 75.125 37.608 ;
     RECT  74.585 24.624 75.148 24.648 ;
     RECT  74.545 6.816 75.157 6.936 ;
     RECT  74.765 64.752 75.161 66.744 ;
     RECT  74.725 59.52 75.193 62.28 ;
     RECT  75.049 10.752 75.197 18.792 ;
     RECT  74.081 5.568 75.233 5.592 ;
     RECT  74.941 2.544 75.251 4.008 ;
     RECT  74.297 8.16 75.265 9.72 ;
     RECT  74.801 41.28 75.265 49.608 ;
     RECT  75.265 8.16 75.269 10.632 ;
     RECT  74.729 23.232 75.269 23.4 ;
     RECT  75.251 2.544 75.299 3.384 ;
     RECT  74.905 25.632 75.305 26.664 ;
     RECT  74.621 27.648 75.305 28.872 ;
     RECT  75.197 11.76 75.337 18.792 ;
     RECT  75.253 4.416 75.34 4.44 ;
     RECT  75.269 23.232 75.377 23.256 ;
     RECT  75.013 30.096 75.377 36.456 ;
     RECT  75.377 30.096 75.449 35.352 ;
     RECT  74.801 39.072 75.449 40.296 ;
     RECT  75.193 59.28 75.541 62.28 ;
     RECT  75.337 11.76 75.557 19.272 ;
     RECT  75.449 31.824 75.557 35.352 ;
     RECT  75.265 41.28 75.593 49.752 ;
     RECT  75.269 9.216 75.665 10.632 ;
     RECT  75.557 12.192 75.692 19.272 ;
     RECT  75.157 6.624 75.697 6.936 ;
     RECT  75.301 7.92 75.697 7.944 ;
     RECT  75.305 28.416 75.697 28.872 ;
     RECT  75.449 30.096 75.697 30.84 ;
     RECT  75.541 59.28 75.701 63.192 ;
     RECT  74.729 20.496 75.731 22.248 ;
     RECT  75.731 20.496 75.733 22.2 ;
     RECT  74.261 50.832 75.769 58.152 ;
     RECT  75.665 9.216 75.809 9.72 ;
     RECT  75.733 20.448 75.817 22.2 ;
     RECT  75.305 25.776 75.841 26.664 ;
     RECT  75.593 43.728 75.845 49.752 ;
     RECT  75.697 6.624 75.881 7.944 ;
     RECT  75.769 50.832 75.917 58.488 ;
     RECT  75.161 64.752 75.917 66.696 ;
     RECT  75.809 9.648 75.953 9.72 ;
     RECT  75.557 32.16 75.989 35.352 ;
     RECT  75.593 41.28 76.025 42.744 ;
     RECT  75.917 64.752 76.025 64.776 ;
     RECT  75.917 50.832 76.061 51.048 ;
     RECT  75.989 33.552 76.067 35.352 ;
     RECT  75.449 39.744 76.093 40.296 ;
     RECT  76.025 41.28 76.093 42.696 ;
     RECT  75.953 9.696 76.097 9.72 ;
     RECT  75.692 12.192 76.277 19.32 ;
     RECT  75.881 6.816 76.309 7.944 ;
     RECT  76.061 50.832 76.381 50.856 ;
     RECT  75.845 43.728 76.421 48.888 ;
     RECT  75.697 28.416 76.525 30.84 ;
     RECT  75.989 32.16 76.525 32.472 ;
     RECT  75.377 36.432 76.525 36.456 ;
     RECT  76.309 6.816 76.529 8.184 ;
     RECT  76.381 50.16 76.565 50.856 ;
     RECT  76.565 50.304 76.601 50.856 ;
     RECT  75.817 21.12 76.637 22.2 ;
     RECT  76.525 36.432 76.637 37.08 ;
     RECT  76.277 12.192 76.669 12.456 ;
     RECT  75.841 25.776 76.669 27.336 ;
     RECT  75.701 59.52 76.669 62.424 ;
     RECT  76.669 59.52 76.693 63.048 ;
     RECT  76.093 39.744 76.705 42.696 ;
     RECT  76.705 39.36 76.709 42.696 ;
     RECT  76.693 59.52 76.739 63.288 ;
     RECT  76.067 33.888 76.741 35.352 ;
     RECT  76.637 36.432 76.741 36.792 ;
     RECT  76.709 42.24 76.817 42.696 ;
     RECT  76.421 43.872 76.849 48.888 ;
     RECT  75.917 52.128 76.849 58.488 ;
     RECT  76.739 59.52 76.849 61.032 ;
     RECT  76.739 62.112 76.853 63.288 ;
     RECT  76.529 6.816 76.885 7.608 ;
     RECT  75.917 65.808 76.885 66.696 ;
     RECT  76.273 67.776 76.885 67.8 ;
     RECT  75.697 70.128 76.889 70.152 ;
     RECT  76.885 6.384 76.921 7.608 ;
     RECT  76.637 21.168 76.925 22.2 ;
     RECT  76.849 52.128 76.961 61.032 ;
     RECT  76.925 21.216 76.993 22.2 ;
     RECT  76.741 33.888 76.997 36.792 ;
     RECT  76.817 42.288 76.997 42.696 ;
     RECT  76.669 25.776 77.101 27.384 ;
     RECT  76.525 28.416 77.101 32.472 ;
     RECT  76.961 52.128 77.101 60.648 ;
     RECT  77.101 25.776 77.209 32.472 ;
     RECT  76.997 33.888 77.209 36.264 ;
     RECT  77.101 9.792 77.245 9.816 ;
     RECT  77.209 25.776 77.245 36.264 ;
     RECT  76.997 42.48 77.317 42.696 ;
     RECT  76.853 62.64 77.317 63.288 ;
     RECT  76.885 65.808 77.317 67.8 ;
     RECT  76.669 11.808 77.389 12.456 ;
     RECT  76.277 13.632 77.389 19.32 ;
     RECT  77.389 11.808 77.461 19.32 ;
     RECT  76.601 50.304 77.569 50.664 ;
     RECT  77.101 51.648 77.569 60.648 ;
     RECT  76.993 21.216 77.605 23.112 ;
     RECT  76.709 39.36 77.605 40.92 ;
     RECT  77.605 38.784 77.641 40.92 ;
     RECT  77.605 21.216 77.845 23.16 ;
     RECT  77.245 25.68 77.857 36.264 ;
     RECT  77.641 37.872 77.857 40.92 ;
     RECT  77.317 62.64 77.857 63.624 ;
     RECT  77.857 62.544 77.893 63.624 ;
     RECT  77.317 65.808 77.965 68.52 ;
     RECT  76.921 6.288 78.008 7.608 ;
     RECT  77.245 8.976 78.008 9.816 ;
     RECT  77.461 11.712 78.008 19.32 ;
     RECT  77.845 21.216 78.008 23.976 ;
     RECT  77.857 25.296 78.008 36.264 ;
     RECT  77.857 37.872 78.008 41.496 ;
     RECT  77.317 42.48 78.008 42.744 ;
     RECT  76.849 43.872 78.008 48.984 ;
     RECT  77.569 50.304 78.008 60.648 ;
     RECT  77.893 62.544 78.008 63.816 ;
     RECT  77.965 65.808 78.008 68.952 ;
     RECT  78.008 2.148 78.112 88.572 ;
     RECT  78.112 2.418 78.304 88.302 ;
     RECT  78.304 36.816 78.365 38.76 ;
     RECT  78.304 27.984 78.473 31.272 ;
     RECT  78.304 44.688 78.509 60.648 ;
     RECT  78.304 6.624 78.581 9.816 ;
     RECT  78.581 8.16 78.653 9.816 ;
     RECT  78.304 21.216 78.653 23.976 ;
     RECT  78.304 61.68 78.653 64.968 ;
     RECT  78.304 39.84 78.689 41.496 ;
     RECT  78.304 24.96 78.869 26.76 ;
     RECT  78.581 6.624 78.905 6.888 ;
     RECT  78.304 11.424 78.941 19.272 ;
     RECT  78.653 61.68 79.013 64.392 ;
     RECT  78.905 6.816 79.121 6.888 ;
     RECT  78.509 44.688 79.121 58.488 ;
     RECT  78.941 14.112 79.157 19.272 ;
     RECT  78.304 35.424 79.229 35.448 ;
     RECT  78.304 42.72 79.292 43.704 ;
     RECT  79.121 44.688 79.292 48.216 ;
     RECT  79.121 49.536 79.301 58.488 ;
     RECT  78.304 32.4 79.369 34.104 ;
     RECT  79.157 14.16 79.405 19.272 ;
     RECT  78.365 37.488 79.405 38.76 ;
     RECT  78.304 68.496 79.409 68.664 ;
     RECT  79.409 68.64 79.445 68.664 ;
     RECT  78.473 28.56 79.477 29.928 ;
     RECT  78.473 31.248 79.477 31.272 ;
     RECT  78.304 66.144 79.477 67.272 ;
     RECT  79.292 42.72 79.481 48.216 ;
     RECT  79.477 66.144 79.517 67.32 ;
     RECT  79.405 14.16 79.523 20.136 ;
     RECT  79.013 61.68 79.553 63.816 ;
     RECT  79.481 42.72 79.573 43.848 ;
     RECT  78.941 11.424 79.585 12.888 ;
     RECT  79.553 63.072 79.589 63.816 ;
     RECT  79.301 50.256 79.621 58.488 ;
     RECT  78.509 59.52 79.621 60.648 ;
     RECT  78.653 21.216 79.657 23.928 ;
     RECT  78.869 24.96 79.657 26.52 ;
     RECT  79.523 14.16 79.661 19.224 ;
     RECT  79.621 50.256 79.661 60.648 ;
     RECT  79.477 28.56 79.693 31.272 ;
     RECT  79.369 32.4 79.693 34.776 ;
     RECT  79.121 6.864 79.769 6.888 ;
     RECT  78.653 8.16 79.805 9.096 ;
     RECT  79.585 11.376 79.813 12.888 ;
     RECT  79.481 45.216 79.841 48.216 ;
     RECT  79.805 8.16 79.859 8.52 ;
     RECT  79.693 27.984 79.877 34.776 ;
     RECT  79.661 50.256 79.877 54.888 ;
     RECT  79.589 63.168 79.877 63.816 ;
     RECT  79.813 10.848 80.003 12.888 ;
     RECT  78.689 39.888 80.017 41.496 ;
     RECT  79.877 27.984 80.051 31.272 ;
     RECT  79.657 21.216 80.057 26.52 ;
     RECT  79.405 37.488 80.089 38.856 ;
     RECT  79.661 56.016 80.125 60.648 ;
     RECT  79.553 61.68 80.125 61.896 ;
     RECT  80.089 37.44 80.147 38.856 ;
     RECT  79.877 63.168 80.243 63.624 ;
     RECT  80.057 21.216 80.293 26.232 ;
     RECT  80.233 64.608 80.305 64.728 ;
     RECT  80.003 11.376 80.345 12.888 ;
     RECT  79.877 32.4 80.348 34.776 ;
     RECT  80.017 39.888 80.377 41.64 ;
     RECT  79.573 42.672 80.377 43.848 ;
     RECT  80.293 20.256 80.38 26.232 ;
     RECT  80.377 39.888 80.381 43.848 ;
     RECT  80.348 32.4 80.435 35.736 ;
     RECT  80.125 56.016 80.435 61.896 ;
     RECT  80.435 32.4 80.461 34.872 ;
     RECT  80.38 21.216 80.525 26.232 ;
     RECT  80.435 60.384 80.561 61.896 ;
     RECT  80.525 21.216 80.597 23.688 ;
     RECT  80.147 37.44 80.629 38.712 ;
     RECT  79.841 48.192 80.665 48.216 ;
     RECT  80.269 49.392 80.665 49.416 ;
     RECT  80.435 56.016 80.665 59.208 ;
     RECT  80.561 61.68 80.665 61.896 ;
     RECT  79.859 8.16 80.741 8.184 ;
     RECT  80.381 39.888 80.773 41.16 ;
     RECT  80.345 11.424 80.845 12.888 ;
     RECT  79.661 14.16 80.845 14.952 ;
     RECT  80.461 32.4 80.845 34.776 ;
     RECT  79.813 9.504 80.856 9.528 ;
     RECT  80.381 42.192 80.881 43.848 ;
     RECT  79.841 45.216 80.881 47.208 ;
     RECT  80.665 48.192 80.881 49.416 ;
     RECT  79.877 51.072 80.881 54.888 ;
     RECT  80.665 55.968 80.881 59.208 ;
     RECT  80.051 27.984 80.917 29.688 ;
     RECT  80.243 63.504 80.917 63.624 ;
     RECT  80.305 64.608 80.917 64.968 ;
     RECT  80.917 63.504 80.921 64.968 ;
     RECT  80.597 21.216 80.993 22.776 ;
     RECT  80.881 42.192 81.029 59.208 ;
     RECT  80.845 11.424 81.061 14.952 ;
     RECT  79.661 16.08 81.061 19.224 ;
     RECT  80.993 21.216 81.065 21.672 ;
     RECT  81.029 42.192 81.065 48.936 ;
     RECT  81.029 50.352 81.065 59.208 ;
     RECT  80.921 63.6 81.065 64.968 ;
     RECT  81.061 11.424 81.097 19.224 ;
     RECT  81.065 48.192 81.137 48.936 ;
     RECT  81.065 63.792 81.137 64.968 ;
     RECT  79.517 66.192 81.137 67.32 ;
     RECT  81.065 21.216 81.173 21.24 ;
     RECT  81.137 63.792 81.281 64.728 ;
     RECT  80.629 37.104 81.313 38.712 ;
     RECT  81.097 11.424 81.317 19.944 ;
     RECT  81.137 48.24 81.317 48.936 ;
     RECT  80.917 27.36 81.385 29.688 ;
     RECT  80.051 30.72 81.385 31.272 ;
     RECT  81.065 42.192 81.425 47.016 ;
     RECT  81.317 13.68 81.461 19.944 ;
     RECT  81.065 51.072 81.461 59.208 ;
     RECT  80.525 24.672 81.565 26.232 ;
     RECT  81.461 51.36 81.601 59.208 ;
     RECT  80.561 60.384 81.601 60.552 ;
     RECT  80.856 9.504 81.605 10.344 ;
     RECT  81.425 42.192 81.605 46.968 ;
     RECT  81.601 51.36 81.641 60.552 ;
     RECT  81.461 17.136 81.673 19.944 ;
     RECT  80.665 61.68 81.677 62.184 ;
     RECT  81.677 62.16 81.745 62.184 ;
     RECT  81.565 24.192 81.749 26.232 ;
     RECT  81.313 36.432 81.785 38.712 ;
     RECT  81.385 27.36 81.853 31.272 ;
     RECT  80.845 32.304 81.853 34.776 ;
     RECT  80.993 22.656 81.857 22.776 ;
     RECT  81.749 24.192 81.893 25.224 ;
     RECT  81.317 48.24 81.893 48.84 ;
     RECT  81.673 17.136 81.965 21.096 ;
     RECT  81.605 42.768 81.965 46.968 ;
     RECT  81.853 27.36 82.001 34.776 ;
     RECT  81.745 62.16 82.028 62.232 ;
     RECT  82.001 33.408 82.037 34.776 ;
     RECT  81.281 63.792 82.037 63.816 ;
     RECT  81.965 17.136 82.067 20.568 ;
     RECT  81.641 59.808 82.067 60.552 ;
     RECT  81.785 37.536 82.069 38.712 ;
     RECT  80.773 39.84 82.069 41.16 ;
     RECT  82.067 60 82.069 60.552 ;
     RECT  81.461 13.68 82.109 16.104 ;
     RECT  81.641 51.36 82.109 58.728 ;
     RECT  82.067 17.136 82.115 19.224 ;
     RECT  82.028 62.16 82.177 62.424 ;
     RECT  82.037 33.552 82.253 34.776 ;
     RECT  82.109 57.84 82.253 58.728 ;
     RECT  81.965 43.248 82.289 46.968 ;
     RECT  82.069 60 82.289 61.032 ;
     RECT  82.109 13.68 82.321 16.056 ;
     RECT  82.001 27.36 82.321 32.328 ;
     RECT  82.321 13.44 82.357 16.056 ;
     RECT  82.069 37.536 82.357 41.16 ;
     RECT  81.169 7.632 82.361 7.656 ;
     RECT  82.067 20.544 82.361 20.568 ;
     RECT  82.321 26.592 82.361 32.328 ;
     RECT  82.115 17.28 82.397 19.224 ;
     RECT  82.289 60.528 82.397 61.032 ;
     RECT  81.137 66.192 82.501 66.888 ;
     RECT  81.785 36.432 82.645 36.456 ;
     RECT  82.501 65.568 82.645 66.888 ;
     RECT  82.645 35.856 82.693 36.456 ;
     RECT  82.069 50.112 82.717 50.136 ;
     RECT  82.109 51.36 82.717 56.856 ;
     RECT  81.893 24.48 82.753 25.224 ;
     RECT  82.361 26.592 82.753 26.616 ;
     RECT  82.681 6.864 82.825 7.128 ;
     RECT  82.645 65.424 82.861 66.888 ;
     RECT  82.177 62.16 82.933 63.144 ;
     RECT  81.605 9.504 83.005 10.056 ;
     RECT  81.317 11.424 83.005 12.024 ;
     RECT  82.357 13.152 83.077 16.056 ;
     RECT  82.717 50.112 83.149 56.856 ;
     RECT  82.253 57.84 83.149 58.68 ;
     RECT  82.753 24.48 83.18 26.616 ;
     RECT  83.005 9.504 83.221 12.024 ;
     RECT  83.077 13.056 83.221 16.056 ;
     RECT  81.893 48.24 83.221 48.552 ;
     RECT  83.149 50.112 83.221 58.68 ;
     RECT  82.397 61.008 83.269 61.032 ;
     RECT  82.933 62.016 83.269 63.144 ;
     RECT  82.253 33.648 83.365 33.816 ;
     RECT  82.825 6.816 83.408 7.128 ;
     RECT  83.221 9.504 83.408 16.056 ;
     RECT  82.397 17.28 83.408 17.496 ;
     RECT  82.397 18.768 83.408 19.224 ;
     RECT  81.857 22.656 83.408 22.68 ;
     RECT  83.18 23.712 83.408 26.616 ;
     RECT  82.361 27.792 83.408 32.328 ;
     RECT  83.365 33.552 83.408 33.816 ;
     RECT  82.693 34.8 83.408 36.456 ;
     RECT  82.357 37.536 83.408 41.496 ;
     RECT  82.289 43.248 83.408 43.272 ;
     RECT  82.289 44.352 83.408 46.968 ;
     RECT  83.221 48.24 83.408 58.68 ;
     RECT  83.269 61.008 83.408 63.144 ;
     RECT  82.501 64.368 83.408 64.392 ;
     RECT  82.861 65.424 83.408 67.176 ;
     RECT  83.408 2.148 83.512 88.572 ;
     RECT  83.512 2.418 83.704 88.302 ;
     RECT  83.704 60.384 83.765 62.76 ;
     RECT  83.704 11.424 83.837 16.392 ;
     RECT  83.704 8.448 83.843 10.152 ;
     RECT  83.704 38.688 83.843 40.44 ;
     RECT  83.704 65.664 83.873 65.688 ;
     RECT  83.704 32.832 83.981 33.384 ;
     RECT  83.704 44.16 83.981 59.256 ;
     RECT  83.837 11.424 84.017 11.544 ;
     RECT  83.704 24.624 84.017 24.696 ;
     RECT  83.981 44.16 84.089 55.656 ;
     RECT  83.704 35.712 84.179 35.736 ;
     RECT  83.704 6.816 84.323 7.368 ;
     RECT  83.837 12.528 84.413 16.392 ;
     RECT  83.765 60.384 84.413 61.464 ;
     RECT  83.704 64.416 84.449 64.44 ;
     RECT  84.089 51.456 84.485 55.656 ;
     RECT  83.843 9.072 84.521 10.152 ;
     RECT  83.704 41.472 84.521 42.408 ;
     RECT  83.704 66.816 84.521 67.176 ;
     RECT  83.704 25.68 84.557 26.376 ;
     RECT  84.521 66.816 84.665 66.84 ;
     RECT  83.704 17.424 84.697 19.368 ;
     RECT  83.704 20.544 84.697 21.432 ;
     RECT  84.017 24.624 84.737 24.648 ;
     RECT  83.765 62.544 84.737 62.76 ;
     RECT  84.737 62.544 84.755 62.568 ;
     RECT  83.981 33.024 84.769 33.384 ;
     RECT  83.704 34.464 84.769 34.488 ;
     RECT  84.697 17.424 84.805 21.432 ;
     RECT  84.323 7.104 84.845 7.368 ;
     RECT  84.805 17.424 84.845 21.672 ;
     RECT  84.521 41.76 84.845 42.408 ;
     RECT  84.769 33.024 84.881 34.824 ;
     RECT  84.089 44.16 84.881 50.424 ;
     RECT  84.413 61.104 84.881 61.464 ;
     RECT  83.704 27.888 84.953 31.224 ;
     RECT  84.881 61.44 84.953 61.464 ;
     RECT  84.953 29.616 84.985 31.224 ;
     RECT  84.881 33.024 85.021 33.864 ;
     RECT  84.845 42.048 85.021 42.408 ;
     RECT  85.021 32.496 85.025 33.864 ;
     RECT  84.017 11.424 85.061 11.448 ;
     RECT  84.769 10.176 85.093 10.248 ;
     RECT  84.845 7.104 85.133 7.128 ;
     RECT  84.413 14.304 85.169 16.392 ;
     RECT  84.413 12.528 85.205 13.176 ;
     RECT  84.881 45.552 85.205 50.424 ;
     RECT  84.557 25.68 85.277 25.704 ;
     RECT  83.981 56.832 85.277 59.256 ;
     RECT  85.277 59.232 85.313 59.256 ;
     RECT  85.169 14.304 85.429 14.808 ;
     RECT  84.521 9.072 85.457 9.096 ;
     RECT  85.025 32.496 85.457 33.096 ;
     RECT  85.205 45.552 85.475 47.112 ;
     RECT  84.985 29.616 85.477 31.368 ;
     RECT  85.457 32.496 85.477 33.048 ;
     RECT  85.477 29.616 85.523 33.048 ;
     RECT  85.205 48.192 85.525 50.424 ;
     RECT  84.485 51.456 85.525 55.32 ;
     RECT  85.277 56.832 85.525 57.96 ;
     RECT  85.205 12.528 85.532 12.936 ;
     RECT  85.484 24.432 85.571 24.456 ;
     RECT  85.093 10.176 85.573 10.296 ;
     RECT  83.843 38.928 85.601 40.44 ;
     RECT  85.532 11.904 85.619 12.936 ;
     RECT  85.523 29.616 85.673 31.896 ;
     RECT  85.573 10.176 85.745 10.728 ;
     RECT  85.169 16.368 85.885 16.392 ;
     RECT  84.845 17.424 85.885 20.184 ;
     RECT  85.745 10.704 85.925 10.728 ;
     RECT  84.881 44.16 85.925 44.184 ;
     RECT  85.601 39.264 85.993 40.44 ;
     RECT  85.021 42.048 85.993 42.696 ;
     RECT  85.597 25.872 86.029 26.232 ;
     RECT  85.525 56.4 86.051 57.96 ;
     RECT  84.953 28.32 86.065 28.344 ;
     RECT  85.993 39.264 86.065 42.696 ;
     RECT  86.029 25.872 86.101 26.28 ;
     RECT  86.065 28.128 86.105 28.344 ;
     RECT  86.065 39.264 86.137 42.792 ;
     RECT  85.885 16.368 86.141 20.184 ;
     RECT  85.523 33.024 86.141 33.048 ;
     RECT  86.141 16.752 86.173 20.184 ;
     RECT  84.845 21.648 86.173 21.672 ;
     RECT  86.137 39.264 86.173 42.984 ;
     RECT  86.173 39.264 86.177 43.896 ;
     RECT  85.475 45.744 86.209 47.112 ;
     RECT  85.525 48.192 86.209 55.32 ;
     RECT  86.173 16.752 86.213 21.672 ;
     RECT  86.209 45.744 86.245 55.32 ;
     RECT  86.051 57.024 86.291 57.96 ;
     RECT  86.213 17.424 86.321 21.672 ;
     RECT  86.245 45.744 86.332 55.608 ;
     RECT  86.321 17.424 86.393 21.528 ;
     RECT  86.101 25.872 86.425 26.52 ;
     RECT  86.177 41.232 86.429 43.896 ;
     RECT  86.429 42.048 86.465 43.896 ;
     RECT  86.425 25.872 86.533 26.712 ;
     RECT  86.105 28.128 86.533 28.152 ;
     RECT  86.465 42.768 86.537 43.896 ;
     RECT  86.332 45.744 86.537 54.984 ;
     RECT  86.291 57.936 86.537 57.96 ;
     RECT  86.177 39.264 86.573 40.056 ;
     RECT  86.537 45.744 86.573 50.424 ;
     RECT  86.573 45.744 86.588 48.936 ;
     RECT  86.533 25.872 86.627 28.152 ;
     RECT  85.619 12.048 86.629 12.936 ;
     RECT  85.429 14.304 86.629 14.328 ;
     RECT  86.629 12.048 86.675 14.328 ;
     RECT  86.393 17.424 86.675 19.416 ;
     RECT  86.588 45.024 86.675 48.936 ;
     RECT  86.675 47.088 86.681 48.936 ;
     RECT  86.573 50.112 86.681 50.424 ;
     RECT  86.537 51.456 86.753 54.984 ;
     RECT  86.675 12.048 86.789 12.072 ;
     RECT  86.627 25.872 86.789 26.76 ;
     RECT  85.673 29.616 86.789 30.888 ;
     RECT  86.537 43.872 86.789 43.896 ;
     RECT  86.681 47.088 86.789 48.456 ;
     RECT  86.675 17.424 86.825 19.32 ;
     RECT  86.627 28.128 86.861 28.152 ;
     RECT  86.753 51.456 86.861 53.448 ;
     RECT  86.789 30.288 86.929 30.888 ;
     RECT  86.675 13.344 86.933 13.368 ;
     RECT  86.929 30.288 87.005 31.368 ;
     RECT  86.825 18.768 87.041 19.32 ;
     RECT  86.675 45.504 87.041 46.056 ;
     RECT  87.041 18.912 87.113 19.32 ;
     RECT  87.005 30.288 87.113 30.312 ;
     RECT  86.537 42.768 87.113 42.792 ;
     RECT  86.573 39.984 87.181 40.056 ;
     RECT  87.113 18.96 87.185 19.32 ;
     RECT  86.861 51.6 87.185 53.448 ;
     RECT  86.825 17.424 87.221 17.448 ;
     RECT  86.789 26.256 87.221 26.52 ;
     RECT  87.181 39.984 87.257 40.296 ;
     RECT  87.257 40.272 87.329 40.296 ;
     RECT  87.005 31.344 87.365 31.368 ;
     RECT  87.185 19.056 87.437 19.32 ;
     RECT  87.041 45.792 87.437 46.056 ;
     RECT  86.789 48.192 87.437 48.456 ;
     RECT  86.681 50.112 87.437 50.136 ;
     RECT  87.437 19.296 87.473 19.32 ;
     RECT  86.393 20.736 87.473 21.528 ;
     RECT  83.704 23.136 87.473 23.16 ;
     RECT  87.437 45.936 87.473 46.056 ;
     RECT  87.473 20.736 87.509 20.76 ;
     RECT  86.789 47.088 87.581 47.112 ;
     RECT  87.185 52.8 87.617 53.448 ;
     RECT  87.221 26.496 87.653 26.52 ;
     RECT  86.753 54.96 87.761 54.984 ;
     RECT  87.617 52.992 87.905 53.448 ;
     RECT  87.473 45.936 88.409 45.96 ;
     RECT  87.905 53.424 88.873 53.448 ;
     RECT  87.185 51.6 88.909 51.72 ;
     RECT  88.873 53.424 88.909 54.888 ;
     RECT  88.909 51.6 89.413 54.888 ;
     RECT  89.413 51.6 90.061 54.984 ;
     RECT  87.437 48.192 90.641 48.216 ;
     RECT  90.061 51.408 90.684 54.984 ;
    LAYER M5 ;
     RECT  54.48 0.016 57.48 0.037 ;
     RECT  54.384 0.037 57.48 0.085 ;
     RECT  54.384 0.085 57.816 0.179 ;
     RECT  54.576 0.179 57.816 0.181 ;
     RECT  67.536 0.016 73.608 0.227 ;
     RECT  50.736 0.229 50.76 0.371 ;
     RECT  67.728 0.227 73.608 0.515 ;
     RECT  54.576 0.181 57.96 0.563 ;
     RECT  67.728 0.515 70.44 0.563 ;
     RECT  71.472 0.515 73.608 0.563 ;
     RECT  67.728 0.563 70.152 0.611 ;
     RECT  71.856 0.563 73.608 0.611 ;
     RECT  45.264 0.016 48.264 1.139 ;
     RECT  54.576 0.563 54.6 1.139 ;
     RECT  55.632 0.563 57.96 1.139 ;
     RECT  72.24 0.611 73.608 1.763 ;
     RECT  45.264 1.139 48.168 1.811 ;
     RECT  69.456 0.611 70.152 1.811 ;
     RECT  68.208 0.611 68.232 2.003 ;
     RECT  2.4 2.137 2.52 2.151 ;
     RECT  7.8 2.137 7.92 2.151 ;
     RECT  13.2 2.137 13.32 2.151 ;
     RECT  18.6 2.137 18.72 2.151 ;
     RECT  24 2.137 24.12 2.151 ;
     RECT  29.4 2.137 29.52 2.151 ;
     RECT  34.8 2.137 34.92 2.151 ;
     RECT  40.2 2.137 40.32 2.151 ;
     RECT  51 2.137 51.12 2.151 ;
     RECT  61.8 2.137 61.92 2.151 ;
     RECT  78 2.137 78.12 2.151 ;
     RECT  83.4 2.137 83.52 2.151 ;
     RECT  45.264 1.811 47.208 2.339 ;
     RECT  24 2.151 24.312 2.677 ;
     RECT  67.2 2.137 67.512 2.773 ;
     RECT  51 2.151 51.312 2.821 ;
     RECT  72.24 1.763 72.912 2.821 ;
     RECT  45.264 2.339 46.488 2.915 ;
     RECT  13.2 2.151 13.512 3.157 ;
     RECT  75.264 2.533 75.288 3.157 ;
     RECT  51 2.821 52.152 3.299 ;
     RECT  12.24 3.157 13.512 3.397 ;
     RECT  45.6 2.915 46.488 3.589 ;
     RECT  24 2.677 25.08 3.637 ;
     RECT  71.04 2.821 71.064 3.637 ;
     RECT  72.24 2.821 73.752 3.637 ;
     RECT  66.672 2.773 67.512 3.685 ;
     RECT  51 3.299 51.864 3.971 ;
     RECT  10.848 2.821 10.872 4.019 ;
     RECT  12.24 3.397 14.04 4.019 ;
     RECT  75.216 3.157 75.288 4.019 ;
     RECT  66.672 3.685 67.992 4.021 ;
     RECT  68.976 2.629 69 4.067 ;
     RECT  27.696 3.157 27.72 4.259 ;
     RECT  75.264 4.019 75.288 4.451 ;
     RECT  24 3.637 25.704 4.499 ;
     RECT  7.8 2.151 8.112 4.501 ;
     RECT  20.688 3.829 20.712 4.501 ;
     RECT  61.8 2.151 62.112 4.501 ;
     RECT  25.68 4.499 25.704 4.691 ;
     RECT  71.04 3.637 73.752 4.691 ;
     RECT  13.2 4.019 14.04 4.883 ;
     RECT  66.432 4.021 67.992 4.979 ;
     RECT  20.496 4.501 20.712 5.171 ;
     RECT  51 3.971 51.48 5.219 ;
     RECT  69.888 4.165 69.912 5.219 ;
     RECT  71.04 4.691 73.032 5.219 ;
     RECT  51 5.219 51.432 5.315 ;
     RECT  66.432 4.979 67.608 5.459 ;
     RECT  61.68 4.501 62.112 5.653 ;
     RECT  45.6 3.589 46.728 5.699 ;
     RECT  12 5.125 12.024 5.747 ;
     RECT  40.2 2.151 40.512 5.749 ;
     RECT  27.024 4.357 27.048 6.229 ;
     RECT  34.8 2.151 35.112 6.229 ;
     RECT  32.736 5.317 32.76 6.277 ;
     RECT  67.2 5.459 67.608 6.277 ;
     RECT  69.936 5.557 70.056 6.277 ;
     RECT  24 4.499 24.408 6.323 ;
     RECT  32.736 6.277 33.672 6.323 ;
     RECT  40.2 5.749 40.68 6.563 ;
     RECT  59.52 5.605 59.544 6.757 ;
     RECT  54.432 5.701 54.456 6.803 ;
     RECT  20.688 5.171 20.712 6.805 ;
     RECT  67.2 6.277 67.8 6.805 ;
     RECT  83.4 2.151 83.712 6.805 ;
     RECT  34.8 6.229 35.352 6.851 ;
     RECT  66.48 6.805 67.8 6.851 ;
     RECT  39.168 2.245 39.192 6.853 ;
     RECT  42.528 4.981 42.552 6.853 ;
     RECT  78 2.151 78.312 6.853 ;
     RECT  61.104 5.653 62.112 6.899 ;
     RECT  26.832 6.229 27.048 6.947 ;
     RECT  83.4 6.805 84.312 6.947 ;
     RECT  36.864 6.229 36.888 7.043 ;
     RECT  33.648 6.323 33.672 7.091 ;
     RECT  52.704 5.173 52.728 7.093 ;
     RECT  15.984 6.613 16.008 7.189 ;
     RECT  18.6 2.151 18.912 7.237 ;
     RECT  20.016 6.805 20.712 7.237 ;
     RECT  56.208 1.139 57.96 7.381 ;
     RECT  59.52 6.757 60.12 7.475 ;
     RECT  49.152 6.805 49.176 7.619 ;
     RECT  18.6 7.237 20.712 7.811 ;
     RECT  6.816 4.501 8.112 7.859 ;
     RECT  15.12 7.189 16.008 8.003 ;
     RECT  38.208 6.853 39.192 8.003 ;
     RECT  55.68 7.381 58.152 8.003 ;
     RECT  69.888 6.277 70.056 8.147 ;
     RECT  66.48 6.851 67.512 8.195 ;
     RECT  78 6.853 78.456 8.389 ;
     RECT  83.4 6.947 83.712 8.437 ;
     RECT  45.6 5.699 45.912 8.485 ;
     RECT  61.8 6.899 62.112 8.485 ;
     RECT  71.04 5.219 72.912 8.485 ;
     RECT  78 8.389 78.936 8.485 ;
     RECT  33.072 8.341 33.096 8.531 ;
     RECT  78 8.485 79.848 8.531 ;
     RECT  29.4 2.151 29.712 8.533 ;
     RECT  20.496 7.811 20.712 8.579 ;
     RECT  42.528 6.853 43.368 8.579 ;
     RECT  55.68 8.003 57.96 8.579 ;
     RECT  78 8.531 78.456 8.867 ;
     RECT  15.12 8.003 15.144 9.061 ;
     RECT  45.264 8.485 45.912 9.061 ;
     RECT  83.4 8.437 83.832 9.107 ;
     RECT  48.624 8.149 48.648 9.155 ;
     RECT  71.04 8.485 73.032 9.205 ;
     RECT  25.632 8.485 25.656 9.251 ;
     RECT  71.04 9.205 73.992 9.251 ;
     RECT  9.936 5.077 9.96 9.637 ;
     RECT  56.208 8.579 57.96 9.637 ;
     RECT  61.488 8.485 62.112 9.683 ;
     RECT  52.704 7.093 53.112 9.731 ;
     RECT  15.12 9.061 15.72 9.779 ;
     RECT  27.024 6.947 27.048 9.779 ;
     RECT  28.656 8.533 29.712 9.779 ;
     RECT  73.968 9.251 73.992 9.779 ;
     RECT  49.68 9.253 49.704 10.019 ;
     RECT  18.6 7.811 19.176 10.067 ;
     RECT  13.2 4.883 13.512 10.213 ;
     RECT  69.936 8.147 70.056 10.213 ;
     RECT  71.04 9.251 72.912 10.213 ;
     RECT  22.752 9.013 22.776 10.307 ;
     RECT  45.264 9.061 46.488 10.307 ;
     RECT  45.6 10.307 46.488 10.355 ;
     RECT  80.928 9.637 80.952 10.355 ;
     RECT  51 5.315 51.312 10.405 ;
     RECT  52.704 9.731 52.728 10.405 ;
     RECT  83.4 9.107 83.712 10.453 ;
     RECT  38.736 8.003 39.192 10.595 ;
     RECT  20.688 8.579 20.712 10.789 ;
     RECT  12.528 10.213 13.512 10.835 ;
     RECT  33.696 8.533 33.72 10.835 ;
     RECT  51 10.405 52.728 10.835 ;
     RECT  79.824 8.531 79.848 10.837 ;
     RECT  9.216 9.637 9.96 10.883 ;
     RECT  42.528 8.579 42.552 10.883 ;
     RECT  61.584 9.683 62.112 10.883 ;
     RECT  69.936 10.213 72.912 10.883 ;
     RECT  79.824 10.837 79.992 10.883 ;
     RECT  55.584 9.637 57.96 10.931 ;
     RECT  63.6 3.157 63.624 11.029 ;
     RECT  20.592 10.789 20.712 11.365 ;
     RECT  30.816 9.781 30.84 11.365 ;
     RECT  28.224 10.597 28.248 11.411 ;
     RECT  30.816 11.365 31.224 11.411 ;
     RECT  56.112 10.931 57.96 11.507 ;
     RECT  25.776 9.637 25.8 11.653 ;
     RECT  42.48 11.029 42.504 11.795 ;
     RECT  15.12 9.779 15.144 11.845 ;
     RECT  15.12 11.845 15.48 11.987 ;
     RECT  37.776 11.749 37.8 11.989 ;
     RECT  85.584 10.213 85.608 12.083 ;
     RECT  20.592 11.365 20.904 12.517 ;
     RECT  24 6.323 24.312 12.517 ;
     RECT  45.6 10.355 45.912 12.517 ;
     RECT  15.456 11.987 15.48 12.563 ;
     RECT  37.152 11.989 37.8 12.709 ;
     RECT  9.936 10.883 9.96 12.757 ;
     RECT  7.8 7.859 8.112 12.901 ;
     RECT  56.208 11.507 57.96 12.949 ;
     RECT  52.704 10.835 52.728 12.995 ;
     RECT  59.52 7.475 59.544 12.995 ;
     RECT  7.8 12.901 8.376 13.045 ;
     RECT  9.936 12.757 10.248 13.045 ;
     RECT  56.208 12.949 58.344 13.045 ;
     RECT  78 8.867 78.312 13.045 ;
     RECT  40.2 6.563 40.512 13.093 ;
     RECT  41.952 12.517 41.976 13.093 ;
     RECT  56.208 13.045 59.496 13.427 ;
     RECT  63.312 11.029 63.624 13.429 ;
     RECT  63.312 13.429 63.672 13.475 ;
     RECT  45.6 12.517 46.008 13.523 ;
     RECT  23.376 12.517 24.312 13.525 ;
     RECT  37.152 12.709 37.896 13.571 ;
     RECT  56.208 13.427 57.96 13.573 ;
     RECT  40.2 13.093 41.976 13.619 ;
     RECT  51 10.835 51.312 13.621 ;
     RECT  6.864 13.045 8.376 13.667 ;
     RECT  9.888 13.045 10.248 13.667 ;
     RECT  20.592 12.517 21.336 13.667 ;
     RECT  32.448 12.661 32.472 13.667 ;
     RECT  77.472 13.045 78.312 13.763 ;
     RECT  39.168 10.595 39.192 14.005 ;
     RECT  40.2 13.619 41.304 14.005 ;
     RECT  28.272 12.517 28.296 14.099 ;
     RECT  39.168 14.005 41.304 14.099 ;
     RECT  83.232 10.453 83.712 14.147 ;
     RECT  29.4 9.779 29.712 14.197 ;
     RECT  31.2 11.411 31.224 14.197 ;
     RECT  67.2 8.195 67.512 14.245 ;
     RECT  68.784 12.517 68.808 14.245 ;
     RECT  23.376 13.525 24.408 14.291 ;
     RECT  67.2 14.245 68.808 14.291 ;
     RECT  10.08 13.667 10.248 14.339 ;
     RECT  86.64 12.901 86.664 14.339 ;
     RECT  51 13.621 52.2 14.531 ;
     RECT  79.968 10.883 79.992 14.533 ;
     RECT  6.864 13.667 8.112 14.579 ;
     RECT  63.6 13.475 63.672 14.581 ;
     RECT  24 14.291 24.408 14.627 ;
     RECT  51 14.531 51.312 14.677 ;
     RECT  60.528 13.477 60.552 14.677 ;
     RECT  61.8 10.883 62.112 14.677 ;
     RECT  55.296 13.573 57.96 14.819 ;
     RECT  67.2 14.291 68.088 14.867 ;
     RECT  74.112 12.517 74.136 14.867 ;
     RECT  76.56 14.245 76.584 14.867 ;
     RECT  63.6 14.581 63.72 14.869 ;
     RECT  79.344 14.533 79.992 14.915 ;
     RECT  83.4 14.147 83.712 14.917 ;
     RECT  63.36 14.869 63.72 15.061 ;
     RECT  48 11.317 48.024 15.109 ;
     RECT  48 15.109 48.408 15.155 ;
     RECT  76.224 14.869 76.248 15.155 ;
     RECT  41.568 14.773 41.592 15.203 ;
     RECT  63.36 15.061 64.392 15.299 ;
     RECT  43.92 14.245 43.944 15.349 ;
     RECT  45.6 13.523 45.912 15.349 ;
     RECT  56.208 14.819 57.96 15.349 ;
     RECT  43.92 15.349 45.912 15.395 ;
     RECT  17.088 14.773 17.112 15.443 ;
     RECT  37.872 13.571 37.896 15.445 ;
     RECT  10.224 14.339 10.248 15.587 ;
     RECT  50.784 14.677 51.312 15.589 ;
     RECT  37.872 15.445 38.136 15.685 ;
     RECT  37.824 15.685 38.136 15.827 ;
     RECT  83.4 14.917 83.976 15.973 ;
     RECT  29.4 14.197 31.224 16.019 ;
     RECT  33.408 15.061 33.432 16.019 ;
     RECT  48.384 15.155 48.408 16.021 ;
     RECT  50.448 15.589 51.312 16.307 ;
     RECT  29.4 16.019 30.072 16.355 ;
     RECT  48.384 16.021 49.032 16.355 ;
     RECT  85.392 14.773 85.416 16.403 ;
     RECT  31.2 16.019 31.224 16.501 ;
     RECT  44.64 15.395 45.912 16.547 ;
     RECT  28.08 15.061 28.104 16.595 ;
     RECT  60.528 14.677 62.112 16.787 ;
     RECT  69.936 10.883 70.056 16.837 ;
     RECT  71.04 10.883 72.912 16.837 ;
     RECT  56.208 15.349 58.2 16.981 ;
     RECT  59.472 13.427 59.496 16.981 ;
     RECT  63.696 15.299 64.392 16.981 ;
     RECT  11.952 15.301 11.976 17.027 ;
     RECT  56.208 16.981 59.496 17.027 ;
     RECT  6.432 15.685 6.456 17.077 ;
     RECT  7.8 14.579 8.112 17.077 ;
     RECT  56.208 17.027 58.536 17.077 ;
     RECT  37.008 16.981 37.032 17.123 ;
     RECT  18.6 10.067 18.912 17.125 ;
     RECT  82.08 15.973 82.104 17.171 ;
     RECT  55.776 17.077 58.536 17.219 ;
     RECT  20.592 13.667 20.616 17.363 ;
     RECT  43.296 16.261 43.32 17.411 ;
     RECT  51 16.307 51.312 17.413 ;
     RECT  60.528 16.787 60.552 17.461 ;
     RECT  24 14.627 24.312 17.605 ;
     RECT  31.2 16.501 31.272 17.605 ;
     RECT  63.6 16.981 64.392 17.699 ;
     RECT  83.4 15.973 84.264 17.845 ;
     RECT  6.432 17.077 8.112 17.891 ;
     RECT  45.6 16.547 45.912 17.893 ;
     RECT  56.208 17.219 58.536 18.037 ;
     RECT  50.88 17.413 51.312 18.083 ;
     RECT  69.936 16.837 72.912 18.133 ;
     RECT  25.776 11.653 26.04 18.371 ;
     RECT  20.448 17.893 20.472 18.419 ;
     RECT  60.384 17.461 60.552 18.467 ;
     RECT  34.8 6.851 35.112 18.565 ;
     RECT  29.4 16.355 29.712 18.613 ;
     RECT  52.656 17.605 52.68 18.659 ;
     RECT  28.464 18.613 29.712 18.755 ;
     RECT  17.952 17.125 18.912 18.757 ;
     RECT  45.6 17.893 46.728 18.757 ;
     RECT  79.488 14.915 79.512 18.757 ;
     RECT  31.104 17.605 31.272 18.851 ;
     RECT  56.208 18.037 59.256 18.851 ;
     RECT  75.696 18.757 75.72 18.899 ;
     RECT  56.208 18.851 58.68 18.947 ;
     RECT  24 17.605 24.408 19.187 ;
     RECT  86.736 17.413 86.76 19.285 ;
     RECT  6.432 17.891 6.456 19.333 ;
     RECT  21.648 18.757 21.672 19.427 ;
     RECT  29.28 18.755 29.712 19.427 ;
     RECT  34.176 18.565 35.112 19.427 ;
     RECT  60.528 18.467 60.552 19.429 ;
     RECT  61.8 16.787 62.112 19.429 ;
     RECT  44.784 18.757 46.728 19.477 ;
     RECT  44.496 19.477 46.728 19.523 ;
     RECT  60.528 19.429 62.112 19.571 ;
     RECT  45.6 19.523 46.728 19.907 ;
     RECT  5.712 19.333 6.456 19.955 ;
     RECT  17.952 18.757 19.32 20.003 ;
     RECT  63.696 17.699 64.392 20.003 ;
     RECT  48.384 16.355 48.408 20.099 ;
     RECT  79.488 18.757 80.328 20.147 ;
     RECT  80.304 20.147 80.328 20.291 ;
     RECT  24 19.187 24.312 20.437 ;
     RECT  75.744 19.285 75.768 20.483 ;
     RECT  13.2 10.835 13.512 20.485 ;
     RECT  44.496 19.523 44.52 20.579 ;
     RECT  69.552 18.133 72.912 20.579 ;
     RECT  82.032 19.333 82.056 20.579 ;
     RECT  83.4 17.845 84.36 20.579 ;
     RECT  86.64 19.285 86.76 20.771 ;
     RECT  45.6 19.907 45.912 21.061 ;
     RECT  63.696 20.003 63.816 21.061 ;
     RECT  63.6 21.061 63.816 21.107 ;
     RECT  60.528 19.571 60.552 21.109 ;
     RECT  61.8 19.571 62.112 21.109 ;
     RECT  6.432 19.955 6.456 21.155 ;
     RECT  31.104 18.851 31.128 21.155 ;
     RECT  38.112 15.827 38.136 21.155 ;
     RECT  13.2 20.485 14.472 21.541 ;
     RECT  69.936 20.579 72.912 21.541 ;
     RECT  20.496 20.965 20.52 21.683 ;
     RECT  23.28 20.437 24.312 21.683 ;
     RECT  60.528 21.109 62.112 21.683 ;
     RECT  42.192 20.485 42.216 21.923 ;
     RECT  45.6 21.061 46.248 21.923 ;
     RECT  75.696 21.157 75.72 22.259 ;
     RECT  26.016 18.371 26.04 22.741 ;
     RECT  34.8 19.427 35.112 22.741 ;
     RECT  78 13.763 78.312 22.741 ;
     RECT  69.552 21.541 72.912 22.835 ;
     RECT  39.168 14.099 40.512 23.173 ;
     RECT  79.824 22.741 79.848 23.267 ;
     RECT  24 21.683 24.312 23.317 ;
     RECT  51 18.083 51.312 23.317 ;
     RECT  34.8 22.741 35.256 23.363 ;
     RECT  39.168 23.173 40.632 23.699 ;
     RECT  67.2 14.867 67.512 23.701 ;
     RECT  83.4 20.579 83.712 23.701 ;
     RECT  24 23.317 24.744 23.893 ;
     RECT  32.592 23.317 32.616 23.893 ;
     RECT  61.8 21.683 62.112 23.941 ;
     RECT  77.856 22.741 78.312 23.941 ;
     RECT  77.856 23.941 78.6 23.987 ;
     RECT  32.592 23.893 33.048 24.083 ;
     RECT  39.168 23.699 40.512 24.085 ;
     RECT  61.8 23.941 62.568 24.277 ;
     RECT  18.6 20.003 19.32 24.325 ;
     RECT  10.896 23.317 10.92 24.467 ;
     RECT  23.28 23.893 24.744 24.469 ;
     RECT  17.424 23.701 17.448 24.515 ;
     RECT  18.432 24.325 19.32 24.515 ;
     RECT  22.752 24.469 24.744 24.517 ;
     RECT  83.232 23.701 83.712 24.563 ;
     RECT  75.072 23.365 75.096 24.659 ;
     RECT  22.752 24.517 24.888 24.755 ;
     RECT  33.024 24.083 33.048 24.803 ;
     RECT  7.8 17.891 8.112 25.045 ;
     RECT  31.248 23.893 31.272 25.091 ;
     RECT  45.6 21.923 45.912 25.093 ;
     RECT  52.992 24.469 53.016 25.139 ;
     RECT  78 23.987 78.6 25.139 ;
     RECT  24 24.755 24.888 25.283 ;
     RECT  13.2 21.541 14.904 25.285 ;
     RECT  16.08 20.629 16.104 25.285 ;
     RECT  66.672 23.701 67.512 25.331 ;
     RECT  61.68 24.277 62.568 25.427 ;
     RECT  18.6 24.515 19.32 25.477 ;
     RECT  29.4 19.427 29.712 25.477 ;
     RECT  32.688 25.285 32.712 25.573 ;
     RECT  56.208 18.947 57.96 25.621 ;
     RECT  22.752 24.755 22.776 25.715 ;
     RECT  7.008 25.045 8.112 25.859 ;
     RECT  86.736 20.771 86.76 25.861 ;
     RECT  31.872 25.573 32.712 26.243 ;
     RECT  20.88 24.805 20.904 26.291 ;
     RECT  18.6 25.477 19.56 26.293 ;
     RECT  45.6 25.093 46.2 26.387 ;
     RECT  18.6 26.293 19.656 26.435 ;
     RECT  29.088 25.477 29.712 26.483 ;
     RECT  7.296 25.859 8.112 26.485 ;
     RECT  9.648 25.813 9.672 26.485 ;
     RECT  61.8 25.427 62.568 26.485 ;
     RECT  63.6 21.107 63.624 26.485 ;
     RECT  5.136 26.485 5.16 26.675 ;
     RECT  7.296 26.485 9.672 26.675 ;
     RECT  31.872 26.243 31.896 26.725 ;
     RECT  31.392 26.725 31.896 26.771 ;
     RECT  10.848 26.101 10.872 26.773 ;
     RECT  0.144 26.053 0.168 26.819 ;
     RECT  52.512 26.149 52.536 26.819 ;
     RECT  7.296 26.675 8.112 26.915 ;
     RECT  10.848 26.773 11.016 26.915 ;
     RECT  29.4 26.483 29.712 26.965 ;
     RECT  31.392 26.771 31.416 26.965 ;
     RECT  7.392 26.915 8.112 27.011 ;
     RECT  10.848 26.915 10.872 27.059 ;
     RECT  44.448 26.389 44.472 27.061 ;
     RECT  45.6 26.387 45.912 27.061 ;
     RECT  44.448 27.061 45.912 27.107 ;
     RECT  17.232 26.821 17.256 27.155 ;
     RECT  65.328 24.469 65.352 27.253 ;
     RECT  65.328 27.253 65.544 27.299 ;
     RECT  26.016 22.741 26.856 27.301 ;
     RECT  34.8 23.363 35.112 27.301 ;
     RECT  80.016 25.285 80.04 27.349 ;
     RECT  12.144 25.861 12.168 27.395 ;
     RECT  47.328 27.349 47.352 27.491 ;
     RECT  52.704 27.349 52.728 27.491 ;
     RECT  33.696 27.349 33.72 27.539 ;
     RECT  18.6 26.435 19.416 27.589 ;
     RECT  24 25.283 24.312 27.589 ;
     RECT  80.016 27.349 80.952 27.589 ;
     RECT  21.168 27.349 21.192 27.635 ;
     RECT  29.4 26.965 31.416 27.635 ;
     RECT  44.64 27.107 45.912 27.635 ;
     RECT  74.4 26.725 74.424 27.683 ;
     RECT  13.2 25.285 16.104 27.685 ;
     RECT  80.016 27.589 81 27.731 ;
     RECT  2.4 2.151 2.712 27.733 ;
     RECT  18.6 27.589 20.088 27.779 ;
     RECT  38.208 24.085 40.512 27.781 ;
     RECT  13.2 27.685 16.968 27.827 ;
     RECT  34.8 27.301 35.592 27.877 ;
     RECT  2.4 27.733 2.808 27.923 ;
     RECT  24 27.589 24.888 27.923 ;
     RECT  28.32 27.925 28.344 28.067 ;
     RECT  34.512 27.877 35.592 28.163 ;
     RECT  29.4 27.635 30.36 28.211 ;
     RECT  85.536 24.421 85.56 28.309 ;
     RECT  86.592 25.861 86.76 28.309 ;
     RECT  18.6 27.779 19.848 28.451 ;
     RECT  38.208 27.781 41.16 28.451 ;
     RECT  34.512 28.163 35.112 28.501 ;
     RECT  26.016 27.301 27.288 28.547 ;
     RECT  26.016 28.547 26.04 28.597 ;
     RECT  67.2 25.331 67.512 28.597 ;
     RECT  68.88 28.501 68.904 28.597 ;
     RECT  69.936 22.835 72.912 28.597 ;
     RECT  25.68 28.597 26.04 28.643 ;
     RECT  33.792 28.501 35.112 28.643 ;
     RECT  68.88 28.597 72.912 28.739 ;
     RECT  50.736 23.317 51.312 28.789 ;
     RECT  18.6 28.451 19.416 28.835 ;
     RECT  24 27.923 24.552 28.835 ;
     RECT  13.2 27.827 16.104 28.837 ;
     RECT  13.2 28.837 16.536 28.883 ;
     RECT  50.592 28.789 51.312 28.931 ;
     RECT  56.208 25.621 58.632 28.933 ;
     RECT  0.144 28.789 0.168 28.979 ;
     RECT  24 28.835 24.456 28.979 ;
     RECT  50.736 28.931 51.312 29.029 ;
     RECT  67.2 28.597 67.752 29.075 ;
     RECT  22.8 27.637 22.824 29.123 ;
     RECT  50.736 29.029 51.864 29.171 ;
     RECT  80.016 27.731 80.952 29.171 ;
     RECT  45.6 27.635 45.912 29.173 ;
     RECT  31.392 27.635 31.416 29.219 ;
     RECT  45.6 29.173 46.536 29.315 ;
     RECT  9.648 26.675 9.672 29.365 ;
     RECT  9.504 29.365 9.672 29.411 ;
     RECT  78 25.139 78.312 29.413 ;
     RECT  69.024 28.739 72.912 29.459 ;
     RECT  48.192 28.213 48.216 29.555 ;
     RECT  34.512 28.643 35.112 29.605 ;
     RECT  78 29.413 78.408 29.651 ;
     RECT  56.208 28.933 58.872 29.699 ;
     RECT  75.84 28.405 75.864 29.747 ;
     RECT  85.536 28.309 86.76 30.179 ;
     RECT  29.4 28.211 30.216 30.181 ;
     RECT  34.512 29.605 35.352 30.181 ;
     RECT  56.208 29.699 58.632 30.181 ;
     RECT  78 29.651 78.312 30.181 ;
     RECT  38.208 28.451 40.512 30.227 ;
     RECT  27.264 28.547 27.288 30.229 ;
     RECT  65.52 27.299 65.544 30.323 ;
     RECT  60.528 21.683 60.552 30.373 ;
     RECT  61.8 26.485 63.624 30.373 ;
     RECT  56.064 30.181 58.632 30.515 ;
     RECT  9.504 29.411 9.528 30.517 ;
     RECT  9.504 30.517 9.624 30.563 ;
     RECT  85.536 30.179 85.56 30.563 ;
     RECT  29.4 30.181 30.84 30.565 ;
     RECT  24 28.979 24.408 30.709 ;
     RECT  80.016 29.171 80.04 30.755 ;
     RECT  29.28 30.565 30.84 30.803 ;
     RECT  82.32 30.565 82.344 30.805 ;
     RECT  83.4 24.563 83.712 30.805 ;
     RECT  20.544 29.845 20.568 30.851 ;
     RECT  32.592 29.605 32.616 30.851 ;
     RECT  56.064 30.515 57.96 30.995 ;
     RECT  82.32 30.805 83.712 31.189 ;
     RECT  34.368 30.181 35.352 31.235 ;
     RECT  27.264 30.229 27.912 31.379 ;
     RECT  38.688 30.227 40.512 31.379 ;
     RECT  53.472 30.709 53.496 31.379 ;
     RECT  60.528 30.373 63.624 31.379 ;
     RECT  29.28 30.803 30.168 31.475 ;
     RECT  25.68 28.643 25.704 31.523 ;
     RECT  29.28 31.475 29.928 31.525 ;
     RECT  34.368 31.235 35.112 31.763 ;
     RECT  77.904 30.181 78.312 31.763 ;
     RECT  18.6 28.835 19.32 31.765 ;
     RECT  10.848 31.621 10.872 31.811 ;
     RECT  9.6 30.563 9.624 32.099 ;
     RECT  50.736 29.171 51.312 32.339 ;
     RECT  82.32 31.189 83.928 32.339 ;
     RECT  34.8 31.763 35.112 32.341 ;
     RECT  28.8 31.525 29.928 32.387 ;
     RECT  60.528 31.379 60.552 32.437 ;
     RECT  60.528 32.437 60.744 32.483 ;
     RECT  50.832 32.339 51.312 32.485 ;
     RECT  16.08 28.883 16.536 32.531 ;
     RECT  28.8 32.387 29.712 32.531 ;
     RECT  85.488 30.613 85.512 32.531 ;
     RECT  74.064 31.237 74.088 32.723 ;
     RECT  50.832 32.485 51.432 32.821 ;
     RECT  65.52 31.861 65.544 32.867 ;
     RECT  4.944 31.285 4.968 33.013 ;
     RECT  31.872 32.053 31.896 33.059 ;
     RECT  38.736 31.379 40.512 33.107 ;
     RECT  50.832 32.821 52.152 33.203 ;
     RECT  83.4 32.339 83.928 33.349 ;
     RECT  24 30.709 24.504 33.445 ;
     RECT  29.4 32.531 29.712 33.493 ;
     RECT  18.6 31.765 19.368 33.541 ;
     RECT  4.8 33.013 4.968 33.587 ;
     RECT  34.8 32.341 35.784 33.683 ;
     RECT  49.632 33.013 49.656 33.683 ;
     RECT  29.184 33.493 29.712 33.779 ;
     RECT  33.696 33.445 33.72 33.779 ;
     RECT  82.32 32.339 82.344 33.781 ;
     RECT  83.4 33.349 84.168 33.781 ;
     RECT  82.32 33.781 84.168 33.827 ;
     RECT  76.032 32.437 76.056 34.067 ;
     RECT  21.264 31.525 21.288 34.069 ;
     RECT  59.184 32.965 59.208 34.069 ;
     RECT  29.4 33.779 29.712 34.165 ;
     RECT  45.6 29.315 45.912 34.165 ;
     RECT  78 31.763 78.312 34.165 ;
     RECT  21.264 34.069 21.432 34.211 ;
     RECT  59.184 34.069 59.592 34.211 ;
     RECT  38.736 33.107 39.192 34.259 ;
     RECT  41.664 33.397 41.688 34.259 ;
     RECT  37.68 33.637 37.704 34.355 ;
     RECT  77.232 34.165 78.312 34.357 ;
     RECT  38.736 34.259 38.76 34.643 ;
     RECT  23.328 33.445 24.504 34.645 ;
     RECT  22.272 34.645 24.504 34.691 ;
     RECT  67.2 29.075 67.512 34.693 ;
     RECT  60.72 32.483 60.744 34.741 ;
     RECT  61.8 31.379 63.624 34.741 ;
     RECT  80.688 33.445 80.712 34.741 ;
     RECT  80.4 34.741 80.712 34.787 ;
     RECT  2.4 27.923 2.712 34.789 ;
     RECT  21.264 34.211 21.288 34.789 ;
     RECT  76.944 34.357 78.312 34.835 ;
     RECT  2.4 34.789 2.808 34.979 ;
     RECT  29.4 34.165 29.832 35.027 ;
     RECT  22.272 34.691 22.392 35.075 ;
     RECT  13.2 28.883 14.904 35.221 ;
     RECT  17.952 33.541 19.368 35.363 ;
     RECT  20.352 34.789 21.288 35.363 ;
     RECT  66.768 34.693 67.512 35.363 ;
     RECT  77.232 34.835 78.312 35.459 ;
     RECT  69.936 29.459 72.912 35.509 ;
     RECT  74.544 34.213 74.568 35.555 ;
     RECT  60.72 34.741 63.624 35.557 ;
     RECT  59.184 34.211 59.208 35.699 ;
     RECT  60.72 35.557 63.864 35.701 ;
     RECT  60.384 35.701 63.864 35.747 ;
     RECT  82.656 33.827 84.168 35.747 ;
     RECT  61.68 35.747 63.864 35.845 ;
     RECT  40.2 33.107 40.512 35.893 ;
     RECT  16.08 32.531 16.104 35.939 ;
     RECT  65.664 33.493 65.688 35.939 ;
     RECT  22.272 35.075 22.296 36.133 ;
     RECT  68.976 35.509 72.912 36.371 ;
     RECT  56.208 30.995 57.96 36.373 ;
     RECT  39.216 35.893 40.512 36.515 ;
     RECT  47.616 35.893 47.64 36.515 ;
     RECT  50.832 33.203 51.432 36.563 ;
     RECT  31.968 36.085 31.992 36.803 ;
     RECT  21.264 35.363 21.288 36.805 ;
     RECT  22.272 36.133 22.776 36.805 ;
     RECT  27.264 31.379 27.288 36.997 ;
     RECT  37.296 34.597 37.32 36.997 ;
     RECT  53.472 35.557 53.496 37.043 ;
     RECT  4.944 33.587 4.968 37.091 ;
     RECT  21.264 36.805 22.776 37.091 ;
     RECT  69.072 36.371 72.912 37.379 ;
     RECT  37.296 36.997 37.656 37.381 ;
     RECT  80.4 34.787 80.424 37.475 ;
     RECT  54.72 36.421 54.744 37.571 ;
     RECT  12.816 35.221 14.904 37.573 ;
     RECT  47.376 37.333 47.4 37.573 ;
     RECT  26.88 36.997 27.288 37.619 ;
     RECT  9.36 33.013 9.384 37.667 ;
     RECT  21.264 37.091 21.96 37.667 ;
     RECT  40.08 36.515 40.512 37.667 ;
     RECT  56.208 36.373 58.152 37.859 ;
     RECT  50.832 36.563 51.312 37.861 ;
     RECT  82.656 35.747 83.712 38.149 ;
     RECT  37.2 37.381 37.656 38.197 ;
     RECT  47.328 37.573 47.4 38.197 ;
     RECT  37.104 38.197 37.656 38.243 ;
     RECT  12.816 37.573 15.48 38.675 ;
     RECT  82.512 38.149 83.712 38.677 ;
     RECT  60.384 35.747 60.408 38.723 ;
     RECT  27.264 37.619 27.288 38.725 ;
     RECT  34.8 33.683 35.112 38.725 ;
     RECT  50.832 37.861 51.768 38.725 ;
     RECT  47.328 38.197 47.736 38.771 ;
     RECT  47.328 38.771 47.352 38.819 ;
     RECT  80.112 37.525 80.136 38.867 ;
     RECT  27.264 38.725 27.912 38.915 ;
     RECT  82.512 38.677 83.832 38.963 ;
     RECT  24 34.691 24.504 38.965 ;
     RECT  50.832 38.725 52.2 38.965 ;
     RECT  12.816 38.675 15.336 39.107 ;
     RECT  4.656 38.245 4.68 39.251 ;
     RECT  7.8 27.011 8.112 39.301 ;
     RECT  9.648 38.677 9.672 39.301 ;
     RECT  82.512 38.963 83.712 39.301 ;
     RECT  7.8 39.301 9.672 39.395 ;
     RECT  37.104 38.243 37.224 39.395 ;
     RECT  50.832 38.965 53.16 39.395 ;
     RECT  55.056 38.581 55.08 39.445 ;
     RECT  54.768 39.445 55.08 39.491 ;
     RECT  24 38.965 25.032 39.875 ;
     RECT  2.4 34.979 2.712 39.877 ;
     RECT  7.8 39.395 8.76 39.877 ;
     RECT  69.936 37.379 72.912 39.877 ;
     RECT  21.264 37.667 21.336 39.923 ;
     RECT  54.768 39.491 54.792 39.923 ;
     RECT  61.68 35.845 64.152 39.923 ;
     RECT  27.264 38.915 27.288 39.971 ;
     RECT  82.08 39.301 83.712 40.165 ;
     RECT  6.912 39.877 8.76 40.405 ;
     RECT  60.528 40.117 60.552 40.405 ;
     RECT  53.136 39.395 53.16 40.451 ;
     RECT  82.08 40.165 84.264 40.451 ;
     RECT  6.864 40.405 8.76 40.595 ;
     RECT  6.912 40.595 8.76 40.979 ;
     RECT  17.184 39.301 17.208 40.981 ;
     RECT  17.088 40.981 17.208 41.027 ;
     RECT  2.4 39.877 2.856 41.075 ;
     RECT  37.2 39.395 37.224 41.075 ;
     RECT  82.896 40.451 84.264 41.075 ;
     RECT  38.304 40.405 38.328 41.123 ;
     RECT  17.088 41.027 17.112 41.171 ;
     RECT  76.128 40.981 76.152 41.269 ;
     RECT  75.6 41.269 76.152 41.315 ;
     RECT  61.68 39.923 63.624 41.363 ;
     RECT  40.2 37.667 40.512 41.365 ;
     RECT  83.4 41.075 84.264 41.507 ;
     RECT  21.312 39.923 21.336 41.509 ;
     RECT  61.68 41.363 63.528 41.509 ;
     RECT  69.12 39.877 72.912 41.555 ;
     RECT  45.12 34.165 45.912 41.605 ;
     RECT  7.296 40.979 8.76 41.651 ;
     RECT  59.232 40.981 59.256 41.651 ;
     RECT  32.544 39.877 32.568 41.701 ;
     RECT  18.6 35.363 19.368 41.797 ;
     RECT  44.976 41.605 45.912 41.845 ;
     RECT  34.8 38.725 35.352 41.891 ;
     RECT  12.816 39.107 14.904 42.133 ;
     RECT  24 39.875 24.504 42.133 ;
     RECT  32.016 41.701 32.568 42.179 ;
     RECT  21.312 41.509 21.672 42.227 ;
     RECT  30.816 41.509 30.84 42.227 ;
     RECT  60.432 40.405 60.552 42.227 ;
     RECT  83.4 41.507 84.024 42.419 ;
     RECT  60.528 42.227 60.552 42.421 ;
     RECT  60.528 42.421 60.6 42.565 ;
     RECT  61.584 41.509 63.528 42.565 ;
     RECT  69.744 41.555 72.912 42.565 ;
     RECT  44.976 41.845 46.056 42.707 ;
     RECT  69.744 42.565 73.464 42.707 ;
     RECT  79.584 40.165 79.608 42.707 ;
     RECT  45.12 42.707 46.056 42.709 ;
     RECT  24 42.133 25.08 42.755 ;
     RECT  75.6 41.315 75.624 42.755 ;
     RECT  12.528 42.133 14.904 42.803 ;
     RECT  52.992 40.981 53.016 42.803 ;
     RECT  60.528 42.565 63.528 42.803 ;
     RECT  29.4 35.027 29.712 43.285 ;
     RECT  32.016 42.179 32.04 43.285 ;
     RECT  50.832 39.395 51.312 43.285 ;
     RECT  67.2 35.363 67.512 43.285 ;
     RECT  56.208 37.859 57.96 43.333 ;
     RECT  45.12 42.709 46.584 43.379 ;
     RECT  60.528 42.803 60.6 43.525 ;
     RECT  32.016 43.285 32.712 43.621 ;
     RECT  47.856 41.173 47.88 43.717 ;
     RECT  34.8 41.891 35.112 43.813 ;
     RECT  40.08 41.365 40.512 43.813 ;
     RECT  56.16 43.333 57.96 43.813 ;
     RECT  2.4 41.075 2.712 43.861 ;
     RECT  56.16 43.813 58.632 43.861 ;
     RECT  45.12 43.379 46.104 43.907 ;
     RECT  66.384 43.285 67.512 43.907 ;
     RECT  5.088 41.557 5.112 43.955 ;
     RECT  47.856 43.717 48.696 43.955 ;
     RECT  60.288 43.525 60.6 44.003 ;
     RECT  31.584 43.621 32.712 44.051 ;
     RECT  43.632 43.813 43.656 44.051 ;
     RECT  61.584 42.803 63.528 44.147 ;
     RECT  31.584 44.051 32.04 44.339 ;
     RECT  56.16 43.861 59.016 44.339 ;
     RECT  45.12 43.907 45.912 44.437 ;
     RECT  16.032 43.813 16.056 44.723 ;
     RECT  39.36 43.813 40.512 44.915 ;
     RECT  74.112 43.333 74.136 44.915 ;
     RECT  50.64 43.285 51.312 44.963 ;
     RECT  12.816 42.803 14.904 44.965 ;
     RECT  54.096 41.557 54.12 44.965 ;
     RECT  56.16 44.339 58.632 44.965 ;
     RECT  86.736 30.179 86.76 45.013 ;
     RECT  45.072 44.437 45.912 45.059 ;
     RECT  47.952 43.955 48.696 45.059 ;
     RECT  68.688 43.669 68.712 45.059 ;
     RECT  50.832 44.963 51.312 45.157 ;
     RECT  34.8 43.813 35.544 45.299 ;
     RECT  39.936 44.915 40.512 45.299 ;
     RECT  60.576 44.003 60.6 45.445 ;
     RECT  61.584 44.147 63.384 45.445 ;
     RECT  2.4 43.861 2.856 45.491 ;
     RECT  48.672 45.059 48.696 45.541 ;
     RECT  69.744 42.707 72.912 45.541 ;
     RECT  48.672 45.541 49.56 45.587 ;
     RECT  50.832 45.157 51.864 45.587 ;
     RECT  69.696 45.541 72.912 45.685 ;
     RECT  28.656 43.285 29.712 45.731 ;
     RECT  69.696 45.685 73.608 45.827 ;
     RECT  21.312 42.227 21.336 45.829 ;
     RECT  12.288 44.965 14.904 45.971 ;
     RECT  49.536 45.587 49.56 46.117 ;
     RECT  50.832 45.587 51.312 46.117 ;
     RECT  12.816 45.971 14.904 46.211 ;
     RECT  56.016 44.965 58.632 46.211 ;
     RECT  69.696 45.827 73.224 46.211 ;
     RECT  85.44 45.541 85.464 46.211 ;
     RECT  86.64 45.013 86.76 46.211 ;
     RECT  7.296 41.651 8.112 46.213 ;
     RECT  13.104 46.211 14.904 46.213 ;
     RECT  60.576 45.445 63.384 46.213 ;
     RECT  83.4 42.419 83.712 46.213 ;
     RECT  18.6 41.797 19.704 46.309 ;
     RECT  13.104 46.213 15.72 46.355 ;
     RECT  17.28 45.541 17.304 46.499 ;
     RECT  78 35.459 78.312 46.597 ;
     RECT  79.344 44.437 79.368 46.597 ;
     RECT  18.336 46.309 19.704 46.643 ;
     RECT  78 46.597 79.368 46.643 ;
     RECT  32.016 44.339 32.04 46.645 ;
     RECT  2.4 45.491 2.808 46.739 ;
     RECT  49.536 46.117 51.312 46.739 ;
     RECT  34.8 45.299 35.112 46.741 ;
     RECT  56.016 46.211 57.96 46.741 ;
     RECT  71.616 46.211 73.224 46.787 ;
     RECT  43.056 45.541 43.08 46.835 ;
     RECT  31.872 46.645 32.04 46.883 ;
     RECT  18.6 46.643 19.704 46.885 ;
     RECT  20.784 45.829 21.336 46.885 ;
     RECT  78 46.643 78.504 46.885 ;
     RECT  76.56 46.837 76.584 46.979 ;
     RECT  77.856 46.885 78.504 47.075 ;
     RECT  67.2 43.907 67.512 47.077 ;
     RECT  34.8 46.741 35.256 47.219 ;
     RECT  76.656 47.125 76.68 47.267 ;
     RECT  54.096 44.965 54.312 47.269 ;
     RECT  33.264 45.973 33.288 47.363 ;
     RECT  74.688 47.317 74.712 47.459 ;
     RECT  60.384 46.213 63.384 47.555 ;
     RECT  54.096 47.269 54.6 47.557 ;
     RECT  55.824 46.741 57.96 47.557 ;
     RECT  4.704 46.117 4.728 47.651 ;
     RECT  71.712 46.787 73.224 47.651 ;
     RECT  13.104 46.355 14.904 47.701 ;
     RECT  13.104 47.701 15.576 47.843 ;
     RECT  49.536 46.739 49.56 47.845 ;
     RECT  66.432 47.077 67.512 47.891 ;
     RECT  18.6 46.885 21.336 47.939 ;
     RECT  48.624 47.845 49.56 47.939 ;
     RECT  68.64 45.541 68.664 48.181 ;
     RECT  69.696 46.211 70.488 48.181 ;
     RECT  13.104 47.843 14.904 48.227 ;
     RECT  54.096 47.557 57.96 48.611 ;
     RECT  68.64 48.181 70.488 48.613 ;
     RECT  58.944 46.741 58.968 48.659 ;
     RECT  50.784 46.739 51.312 48.661 ;
     RECT  48.624 47.939 48.648 48.709 ;
     RECT  45.12 45.059 45.912 48.757 ;
     RECT  40.032 45.299 40.512 48.901 ;
     RECT  50.736 48.661 51.312 48.901 ;
     RECT  48.48 48.709 48.648 48.995 ;
     RECT  40.032 48.901 41.016 49.043 ;
     RECT  45.024 48.757 45.912 49.043 ;
     RECT  83.4 46.213 84.696 49.045 ;
     RECT  54.096 48.611 54.696 49.235 ;
     RECT  50.688 48.901 51.312 49.331 ;
     RECT  27.024 47.269 27.048 49.333 ;
     RECT  6.864 46.213 8.112 49.379 ;
     RECT  27.024 49.333 27.192 49.379 ;
     RECT  83.28 49.045 84.696 49.475 ;
     RECT  83.4 49.475 84.696 49.525 ;
     RECT  10.224 47.845 10.248 49.573 ;
     RECT  9.936 49.573 10.248 49.619 ;
     RECT  42.48 48.805 42.504 49.619 ;
     RECT  83.4 49.525 85.032 49.619 ;
     RECT  48.48 48.995 48.504 49.765 ;
     RECT  47.568 49.765 48.504 49.811 ;
     RECT  54.672 49.235 54.696 49.907 ;
     RECT  68.496 48.613 70.488 50.003 ;
     RECT  50.736 49.331 51.312 50.099 ;
     RECT  20.784 47.939 21.336 50.101 ;
     RECT  3.936 48.949 3.96 50.195 ;
     RECT  13.2 48.227 14.904 50.243 ;
     RECT  74.16 48.517 74.184 50.243 ;
     RECT  85.008 49.619 85.032 50.435 ;
     RECT  20.784 50.101 21.384 50.677 ;
     RECT  32.016 46.883 32.04 50.677 ;
     RECT  31.296 50.677 32.04 50.723 ;
     RECT  61.584 47.555 63.384 50.725 ;
     RECT  65.232 41.269 65.256 50.725 ;
     RECT  64.992 50.725 65.256 50.771 ;
     RECT  34.8 47.219 35.112 50.821 ;
     RECT  18.6 47.939 19.704 50.869 ;
     RECT  20.784 50.677 21.864 50.915 ;
     RECT  27.168 49.379 27.192 51.059 ;
     RECT  56.016 48.611 57.96 51.253 ;
     RECT  12 50.101 12.024 51.299 ;
     RECT  60.576 47.555 60.6 51.347 ;
     RECT  40.032 49.043 40.512 51.349 ;
     RECT  83.4 49.619 83.712 51.349 ;
     RECT  7.68 49.379 8.112 51.395 ;
     RECT  61.584 50.725 63.48 51.395 ;
     RECT  61.8 51.395 63.48 51.541 ;
     RECT  49.488 48.997 49.512 51.637 ;
     RECT  61.8 51.541 63.816 51.637 ;
     RECT  64.992 50.771 65.016 51.637 ;
     RECT  68.64 50.003 70.488 51.637 ;
     RECT  71.712 47.651 72.912 51.637 ;
     RECT  68.64 51.637 72.912 51.827 ;
     RECT  16.848 51.253 16.872 51.923 ;
     RECT  28.224 51.013 28.248 51.923 ;
     RECT  34.224 50.821 35.112 51.923 ;
     RECT  83.184 51.349 83.712 51.923 ;
     RECT  86.736 46.211 86.76 51.971 ;
     RECT  29.4 45.731 29.712 52.261 ;
     RECT  29.184 52.261 29.712 52.403 ;
     RECT  49.488 51.637 49.56 52.499 ;
     RECT  85.2 51.781 85.224 52.499 ;
     RECT  49.488 52.499 49.512 52.645 ;
     RECT  49.392 52.645 49.512 52.691 ;
     RECT  34.8 51.923 35.112 52.693 ;
     RECT  24 42.755 24.504 52.741 ;
     RECT  56.016 51.253 58.152 52.835 ;
     RECT  56.016 52.835 57.96 52.885 ;
     RECT  61.8 51.637 65.016 52.979 ;
     RECT  34.8 52.693 35.544 52.981 ;
     RECT  70.464 51.827 72.912 53.029 ;
     RECT  9.936 49.619 9.96 53.075 ;
     RECT  55.824 52.885 57.96 53.269 ;
     RECT  61.8 52.979 63.864 53.315 ;
     RECT  75.072 51.877 75.096 53.509 ;
     RECT  70.464 53.029 73.224 53.555 ;
     RECT  61.8 53.315 62.112 53.557 ;
     RECT  67.2 47.891 67.512 53.557 ;
     RECT  36.96 51.013 36.984 53.845 ;
     RECT  38.256 52.885 38.28 53.845 ;
     RECT  75.072 53.509 75.576 53.893 ;
     RECT  78 47.075 78.504 53.941 ;
     RECT  36.96 53.845 38.28 53.987 ;
     RECT  68.64 51.827 69.192 53.989 ;
     RECT  70.464 53.555 72.912 53.989 ;
     RECT  0.192 44.101 0.216 54.085 ;
     RECT  39.312 51.349 40.512 54.085 ;
     RECT  18 50.869 19.704 54.133 ;
     RECT  13.2 50.243 14.472 54.179 ;
     RECT  68.64 53.989 72.912 54.179 ;
     RECT  45.12 49.043 45.912 54.181 ;
     RECT  50.784 50.099 51.312 54.181 ;
     RECT  0.192 54.085 0.312 54.227 ;
     RECT  55.632 53.269 57.96 54.275 ;
     RECT  61.248 53.557 62.112 54.277 ;
     RECT  34.8 52.981 35.976 54.325 ;
     RECT  36.96 53.987 36.984 54.325 ;
     RECT  47.568 49.811 47.592 54.325 ;
     RECT  17.136 54.133 19.704 54.371 ;
     RECT  29.4 52.403 29.712 54.421 ;
     RECT  34.8 54.325 36.984 54.467 ;
     RECT  54.048 54.373 54.072 54.515 ;
     RECT  25.776 51.349 25.8 54.517 ;
     RECT  25.776 54.517 26.04 54.563 ;
     RECT  29.184 54.421 29.712 54.659 ;
     RECT  50.784 54.181 51.72 54.707 ;
     RECT  63.792 53.315 63.864 54.707 ;
     RECT  67.2 53.557 67.608 54.707 ;
     RECT  68.64 54.179 69.192 54.707 ;
     RECT  75.072 53.893 75.624 54.709 ;
     RECT  61.008 54.277 62.112 54.755 ;
     RECT  68.688 54.707 69.192 54.755 ;
     RECT  83.4 51.923 83.712 54.805 ;
     RECT  36.096 54.467 36.984 54.851 ;
     RECT  74.688 54.709 75.624 54.851 ;
     RECT  63.792 54.707 63.816 54.899 ;
     RECT  47.568 54.325 48.264 54.949 ;
     RECT  49.392 52.691 49.416 54.949 ;
     RECT  83.4 54.805 83.832 54.949 ;
     RECT  47.568 54.949 49.416 54.995 ;
     RECT  6.576 54.085 6.6 55.045 ;
     RECT  7.8 51.395 8.112 55.045 ;
     RECT  56.016 54.275 57.96 55.045 ;
     RECT  38.256 53.987 38.28 55.093 ;
     RECT  39.312 54.085 40.632 55.093 ;
     RECT  75.552 54.851 75.624 55.093 ;
     RECT  43.872 54.469 43.896 55.139 ;
     RECT  77.472 53.941 78.504 55.139 ;
     RECT  45.12 54.181 46.008 55.141 ;
     RECT  6.576 55.045 8.112 55.235 ;
     RECT  56.016 55.045 58.728 55.235 ;
     RECT  78 55.139 78.504 55.237 ;
     RECT  28.128 55.141 28.152 55.283 ;
     RECT  45.12 55.141 46.296 55.283 ;
     RECT  6.576 55.235 6.6 55.331 ;
     RECT  16.512 54.565 16.536 55.477 ;
     RECT  18 54.371 19.704 55.667 ;
     RECT  2.4 46.739 2.712 55.669 ;
     RECT  9.888 53.509 9.912 55.669 ;
     RECT  10.944 55.141 10.968 55.669 ;
     RECT  24 52.741 24.6 55.669 ;
     RECT  9.888 55.669 10.968 55.715 ;
     RECT  16.512 55.477 16.632 55.715 ;
     RECT  38.256 55.093 40.632 55.715 ;
     RECT  83.232 54.949 83.832 55.715 ;
     RECT  47.568 54.995 47.592 55.765 ;
     RECT  38.256 55.715 40.512 55.811 ;
     RECT  13.2 54.179 13.512 55.813 ;
     RECT  83.232 55.715 83.712 55.859 ;
     RECT  64.992 52.979 65.016 55.861 ;
     RECT  10.176 55.715 10.968 55.907 ;
     RECT  36.96 54.851 36.984 55.907 ;
     RECT  45.12 55.283 46.2 55.907 ;
     RECT  50.784 54.707 51.312 55.957 ;
     RECT  64.608 55.861 65.016 56.003 ;
     RECT  24 55.669 24.84 56.053 ;
     RECT  38.784 55.811 40.512 56.195 ;
     RECT  16.512 55.715 16.536 56.243 ;
     RECT  49.008 54.995 49.416 56.243 ;
     RECT  38.784 56.195 38.808 56.339 ;
     RECT  34.8 54.467 35.112 56.389 ;
     RECT  56.016 55.235 57.96 56.389 ;
     RECT  86.256 55.573 86.28 56.389 ;
     RECT  78 55.237 78.696 56.435 ;
     RECT  47.472 55.765 47.592 56.437 ;
     RECT  49.392 56.243 49.416 56.483 ;
     RECT  64.608 56.003 64.632 56.483 ;
     RECT  68.688 54.755 68.76 56.483 ;
     RECT  7.8 55.235 8.112 56.677 ;
     RECT  24 56.053 25.032 56.771 ;
     RECT  29.4 54.659 29.712 56.773 ;
     RECT  47.472 56.437 47.976 56.867 ;
     RECT  79.968 56.725 79.992 56.867 ;
     RECT  64.464 56.821 64.488 56.917 ;
     RECT  64.368 56.917 64.488 56.963 ;
     RECT  41.568 56.437 41.592 57.011 ;
     RECT  4.512 55.813 4.536 57.059 ;
     RECT  6.816 56.677 8.112 57.059 ;
     RECT  31.296 50.723 31.32 57.059 ;
     RECT  75.552 55.093 75.96 57.059 ;
     RECT  86.016 56.389 86.28 57.059 ;
     RECT  10.944 55.907 10.968 57.107 ;
     RECT  18.192 55.667 19.704 57.107 ;
     RECT  40.2 56.195 40.512 57.109 ;
     RECT  78 56.435 78.408 57.155 ;
     RECT  40.2 57.109 40.632 57.299 ;
     RECT  13.056 55.813 13.512 57.301 ;
     RECT  12.96 57.301 13.512 57.443 ;
     RECT  43.488 56.821 43.512 57.589 ;
     RECT  28.656 56.773 29.712 57.827 ;
     RECT  55.248 56.389 57.96 57.827 ;
     RECT  86.016 57.059 86.04 57.827 ;
     RECT  56.016 57.827 57.96 57.875 ;
     RECT  18.192 57.107 19.464 58.117 ;
     RECT  21.36 50.915 21.864 58.117 ;
     RECT  68.736 56.483 68.76 58.117 ;
     RECT  13.104 57.443 13.512 58.211 ;
     RECT  43.488 57.589 44.088 58.403 ;
     RECT  56.016 57.875 57.336 58.403 ;
     RECT  26.016 54.563 26.04 58.645 ;
     RECT  50.736 55.957 51.312 58.645 ;
     RECT  61.8 54.755 62.112 58.645 ;
     RECT  80.4 58.549 80.424 58.645 ;
     RECT  32.64 57.541 32.664 58.691 ;
     RECT  43.488 58.403 43.512 58.691 ;
     RECT  34.56 56.389 35.112 58.739 ;
     RECT  68.736 58.117 69.576 58.739 ;
     RECT  54.672 58.693 54.696 58.835 ;
     RECT  18.048 58.117 19.464 58.883 ;
     RECT  26.016 58.645 26.232 59.171 ;
     RECT  20.88 58.117 21.864 59.267 ;
     RECT  61.632 58.645 62.112 59.267 ;
     RECT  84.816 58.693 84.84 59.267 ;
     RECT  50.736 58.645 52.296 59.507 ;
     RECT  50.736 59.507 51.312 59.605 ;
     RECT  18.6 58.883 19.464 59.797 ;
     RECT  29.4 57.827 29.712 59.845 ;
     RECT  80.352 58.645 80.424 59.891 ;
     RECT  14.784 59.269 14.808 60.035 ;
     RECT  43.44 58.741 43.464 60.035 ;
     RECT  56.016 58.403 57 60.277 ;
     RECT  29.4 59.845 29.832 60.373 ;
     RECT  40.2 57.299 40.512 60.373 ;
     RECT  67.2 54.707 67.512 60.373 ;
     RECT  28.944 60.373 29.832 60.419 ;
     RECT  56.016 60.277 57.288 60.419 ;
     RECT  66.432 60.373 67.512 60.421 ;
     RECT  47.952 56.867 47.976 60.467 ;
     RECT  82.032 59.797 82.056 60.563 ;
     RECT  64.368 56.963 64.392 60.659 ;
     RECT  70.944 54.179 72.912 60.659 ;
     RECT  45.12 55.907 45.912 60.661 ;
     RECT  61.8 59.267 62.112 60.709 ;
     RECT  7.8 57.059 8.112 60.757 ;
     RECT  10.368 58.645 10.392 60.803 ;
     RECT  28.944 60.419 29.712 60.947 ;
     RECT  50.448 59.605 51.312 60.947 ;
     RECT  61.2 60.709 62.112 60.947 ;
     RECT  61.8 60.947 62.112 60.997 ;
     RECT  24 56.771 24.84 61.043 ;
     RECT  56.016 60.419 57 61.043 ;
     RECT  59.856 58.645 59.88 61.043 ;
     RECT  36.816 60.997 36.84 61.139 ;
     RECT  83.28 55.859 83.712 61.139 ;
     RECT  39.84 60.373 40.512 61.141 ;
     RECT  7.8 60.757 8.568 61.475 ;
     RECT  22.896 60.661 22.92 61.475 ;
     RECT  61.8 60.997 62.664 61.475 ;
     RECT  18.6 59.797 19.512 61.525 ;
     RECT  65.568 60.421 67.512 61.571 ;
     RECT  80.352 59.891 80.376 61.717 ;
     RECT  80.208 61.717 80.376 61.763 ;
     RECT  56.016 61.043 56.712 62.005 ;
     RECT  26.016 59.171 26.04 62.101 ;
     RECT  63.84 61.573 63.864 62.101 ;
     RECT  60.672 61.237 60.696 62.147 ;
     RECT  65.76 61.571 67.512 62.147 ;
     RECT  18.6 61.525 19.992 62.195 ;
     RECT  39.84 61.141 41.016 62.195 ;
     RECT  45.12 60.661 46.152 62.195 ;
     RECT  63.36 62.101 63.864 62.195 ;
     RECT  71.136 60.659 72.912 62.195 ;
     RECT  45.6 62.195 46.152 62.197 ;
     RECT  68.736 58.739 68.76 62.243 ;
     RECT  70.128 60.709 70.152 62.341 ;
     RECT  71.136 62.195 71.16 62.341 ;
     RECT  70.128 62.341 71.16 62.387 ;
     RECT  66.432 62.147 67.512 62.435 ;
     RECT  82.08 60.997 82.104 62.435 ;
     RECT  84.72 61.429 84.744 62.579 ;
     RECT  45.6 62.197 46.776 62.581 ;
     RECT  50.736 60.947 51.312 62.629 ;
     RECT  24 61.043 24.456 62.771 ;
     RECT  55.296 62.005 56.712 62.771 ;
     RECT  26.016 62.101 26.76 62.867 ;
     RECT  21.36 59.267 21.864 63.109 ;
     RECT  75.552 57.059 75.624 63.157 ;
     RECT  75.552 63.157 75.672 63.203 ;
     RECT  45.6 62.581 47.544 63.251 ;
     RECT  64.992 62.725 65.016 63.251 ;
     RECT  9.648 62.629 9.672 63.299 ;
     RECT  49.776 62.629 51.312 63.299 ;
     RECT  76.704 59.797 76.728 63.299 ;
     RECT  40.2 62.195 41.016 63.301 ;
     RECT  14.832 62.677 14.856 63.539 ;
     RECT  63.36 62.195 63.816 63.683 ;
     RECT  10.752 61.525 10.776 63.781 ;
     RECT  40.2 63.301 41.064 63.781 ;
     RECT  42.432 60.373 42.456 63.781 ;
     RECT  72.6 62.195 72.912 63.781 ;
     RECT  27.504 63.733 27.528 63.875 ;
     RECT  68.496 63.205 68.52 63.875 ;
     RECT  42.432 63.781 43.368 64.019 ;
     RECT  70.656 62.387 71.16 64.357 ;
     RECT  75.6 63.203 75.672 64.357 ;
     RECT  83.4 61.139 83.712 64.357 ;
     RECT  34.8 58.739 35.112 64.405 ;
     RECT  10.752 63.781 10.824 64.595 ;
     RECT  43.056 64.019 43.368 64.739 ;
     RECT  67.2 62.435 67.512 64.741 ;
     RECT  21.072 63.109 21.864 64.835 ;
     RECT  40.2 63.781 41.112 64.835 ;
     RECT  4.272 63.829 4.296 64.883 ;
     RECT  45.6 63.251 46.776 64.931 ;
     RECT  31.776 63.781 31.8 64.979 ;
     RECT  70.656 64.357 71.208 65.027 ;
     RECT  72.48 63.781 72.912 65.027 ;
     RECT  26.016 62.867 26.04 65.029 ;
     RECT  58.08 63.781 58.104 65.123 ;
     RECT  65.616 64.213 65.64 65.219 ;
     RECT  13.2 58.211 13.512 65.269 ;
     RECT  50.736 63.299 51.312 65.269 ;
     RECT  40.2 64.835 41.064 65.411 ;
     RECT  7.8 61.475 8.112 65.413 ;
     RECT  56.016 62.771 56.712 65.413 ;
     RECT  66.816 64.741 67.512 65.509 ;
     RECT  56.016 65.413 57.672 65.555 ;
     RECT  82.656 64.357 83.712 65.603 ;
     RECT  74.688 64.357 75.672 65.699 ;
     RECT  45.6 64.931 45.912 65.749 ;
     RECT  21.36 64.835 21.864 65.795 ;
     RECT  58.704 65.653 58.728 65.795 ;
     RECT  63.36 63.683 63.384 65.797 ;
     RECT  69.552 63.781 69.576 65.939 ;
     RECT  21.36 65.795 21.672 65.987 ;
     RECT  60.336 65.317 60.36 65.989 ;
     RECT  61.8 61.475 62.112 65.989 ;
     RECT  49.968 65.269 51.312 66.083 ;
     RECT  45.504 65.749 45.912 66.085 ;
     RECT  63.312 65.797 63.384 66.085 ;
     RECT  40.2 65.411 41.016 66.131 ;
     RECT  29.4 60.947 29.712 66.133 ;
     RECT  30.72 61.525 30.744 66.133 ;
     RECT  78 57.155 78.312 66.133 ;
     RECT  26.016 65.029 26.952 66.179 ;
     RECT  34.8 64.405 35.352 66.179 ;
     RECT  72.6 65.027 72.912 66.277 ;
     RECT  7.8 65.413 9.096 66.515 ;
     RECT  72.48 66.277 72.912 66.565 ;
     RECT  74.688 65.699 74.712 66.659 ;
     RECT  63.312 66.085 63.624 66.755 ;
     RECT  78 66.133 78.408 66.803 ;
     RECT  29.4 66.133 30.744 66.805 ;
     RECT  40.2 66.131 40.728 66.853 ;
     RECT  82.032 66.181 82.056 66.899 ;
     RECT  48.048 66.613 48.072 66.901 ;
     RECT  49.968 66.083 49.992 66.901 ;
     RECT  29.4 66.805 31.224 66.947 ;
     RECT  49.584 66.901 49.992 66.947 ;
     RECT  54.576 65.557 54.6 67.043 ;
     RECT  5.376 62.341 5.4 67.141 ;
     RECT  18.6 62.195 19.176 67.189 ;
     RECT  20.784 66.085 20.808 67.189 ;
     RECT  10.752 64.595 10.776 67.237 ;
     RECT  10.368 67.237 10.776 67.283 ;
     RECT  13.2 65.269 14.232 67.283 ;
     RECT  22.656 66.085 22.68 67.283 ;
     RECT  70.656 65.027 71.16 67.283 ;
     RECT  80.208 61.763 80.232 67.283 ;
     RECT  66.72 65.509 67.512 67.427 ;
     RECT  72.384 66.565 72.912 67.427 ;
     RECT  60.336 65.989 62.112 67.475 ;
     RECT  7.8 66.515 8.112 67.525 ;
     RECT  7.68 67.525 8.112 67.667 ;
     RECT  0.192 54.227 0.216 67.763 ;
     RECT  5.088 67.141 5.4 67.811 ;
     RECT  18.6 67.189 20.808 67.859 ;
     RECT  49.584 66.947 49.608 67.859 ;
     RECT  38.16 66.661 38.184 68.053 ;
     RECT  39.936 66.853 40.728 68.099 ;
     RECT  44.976 66.085 45.912 68.099 ;
     RECT  57.888 66.085 57.912 68.291 ;
     RECT  18.6 67.859 19.176 68.341 ;
     RECT  29.4 66.947 30.6 68.341 ;
     RECT  67.2 67.427 67.512 68.341 ;
     RECT  47.568 66.901 48.072 68.389 ;
     RECT  5.376 67.811 5.4 68.435 ;
     RECT  38.16 68.053 38.232 68.435 ;
     RECT  60.192 67.957 60.216 68.867 ;
     RECT  74.304 67.573 74.328 68.869 ;
     RECT  53.568 66.085 53.592 68.915 ;
     RECT  73.968 68.869 74.328 68.915 ;
     RECT  10.368 67.283 10.392 68.917 ;
     RECT  51 66.083 51.312 68.917 ;
     RECT  67.2 68.341 67.848 68.917 ;
     RECT  14.88 68.389 14.904 68.963 ;
     RECT  26.016 66.179 26.04 68.965 ;
     RECT  63.6 66.755 63.624 68.965 ;
     RECT  26.016 68.965 26.232 69.011 ;
     RECT  20.784 67.859 20.808 69.013 ;
     RECT  29.4 68.341 30.84 69.059 ;
     RECT  0.144 68.773 0.168 69.061 ;
     RECT  34.8 66.179 35.112 69.109 ;
     RECT  61.248 67.475 62.112 69.251 ;
     RECT  26.208 69.011 26.232 69.253 ;
     RECT  38.208 68.435 38.232 69.301 ;
     RECT  38.208 69.301 38.424 69.347 ;
     RECT  16.176 60.949 16.2 69.349 ;
     RECT  40.2 68.099 40.728 69.397 ;
     RECT  41.952 68.917 41.976 69.397 ;
     RECT  34.8 69.109 35.256 69.443 ;
     RECT  40.2 69.397 41.976 69.443 ;
     RECT  18.096 68.341 19.176 69.491 ;
     RECT  26.208 69.253 26.76 69.491 ;
     RECT  47.472 68.389 48.072 69.491 ;
     RECT  63.312 68.965 63.624 69.493 ;
     RECT  16.176 69.349 16.584 69.539 ;
     RECT  26.64 69.491 26.76 69.539 ;
     RECT  63.264 69.493 63.624 69.539 ;
     RECT  29.4 69.059 30.504 69.541 ;
     RECT  66.72 68.917 67.848 69.587 ;
     RECT  10.272 68.917 10.392 69.635 ;
     RECT  72.48 67.427 72.912 69.683 ;
     RECT  73.968 68.915 73.992 69.683 ;
     RECT  67.2 69.587 67.848 69.779 ;
     RECT  20.784 69.013 21.336 69.877 ;
     RECT  0.144 69.061 0.216 69.923 ;
     RECT  20.784 69.877 22.2 69.923 ;
     RECT  0.192 69.923 0.216 69.925 ;
     RECT  10.368 69.635 10.392 69.973 ;
     RECT  16.464 69.539 16.584 69.973 ;
     RECT  21.312 69.923 22.2 69.973 ;
     RECT  63.264 69.539 63.336 70.019 ;
     RECT  2.4 55.669 2.952 70.069 ;
     RECT  16.464 69.973 17.112 70.115 ;
     RECT  21.312 69.973 22.824 70.115 ;
     RECT  40.2 69.443 41.64 70.163 ;
     RECT  43.056 64.739 43.08 70.163 ;
     RECT  56.016 65.555 56.712 70.163 ;
     RECT  64.704 68.341 64.728 70.307 ;
     RECT  10.368 69.973 10.536 70.309 ;
     RECT  18.6 69.491 19.176 70.309 ;
     RECT  0.192 69.925 0.552 70.355 ;
     RECT  0.192 70.355 0.216 70.403 ;
     RECT  13.2 67.283 13.512 70.405 ;
     RECT  28.272 69.877 28.296 70.405 ;
     RECT  34.8 69.443 35.112 70.405 ;
     RECT  27.696 70.405 28.296 70.451 ;
     RECT  13.104 70.405 13.512 70.549 ;
     RECT  18.6 70.309 19.272 70.595 ;
     RECT  24 62.771 24.312 70.597 ;
     RECT  10.368 70.309 10.872 70.643 ;
     RECT  44.496 69.205 44.52 70.645 ;
     RECT  45.6 68.099 45.912 70.645 ;
     RECT  61.8 69.251 62.112 70.645 ;
     RECT  63.264 70.019 63.288 70.645 ;
     RECT  26.64 69.539 26.664 70.691 ;
     RECT  21.312 70.115 22.728 70.739 ;
     RECT  10.368 70.643 10.536 70.741 ;
     RECT  22.176 70.739 22.728 70.835 ;
     RECT  44.496 70.645 45.912 70.835 ;
     RECT  9.6 70.741 10.536 70.883 ;
     RECT  26.304 70.789 26.328 70.931 ;
     RECT  40.2 70.163 40.728 71.027 ;
     RECT  61.8 70.645 63.288 71.077 ;
     RECT  48.048 69.491 48.072 71.123 ;
     RECT  61.536 71.077 63.288 71.123 ;
     RECT  34.8 70.405 35.352 71.221 ;
     RECT  56.4 70.163 56.712 71.269 ;
     RECT  24 70.597 24.552 71.603 ;
     RECT  60.384 70.069 60.408 71.603 ;
     RECT  40.2 71.027 40.632 71.701 ;
     RECT  22.176 70.835 22.2 71.797 ;
     RECT  16.464 70.115 17.016 71.843 ;
     RECT  22.032 71.797 22.2 71.843 ;
     RECT  34.224 71.221 35.352 71.843 ;
     RECT  34.224 71.843 35.112 71.891 ;
     RECT  44.976 70.835 45.912 71.891 ;
     RECT  56.4 71.269 57.192 71.891 ;
     RECT  40.08 71.701 40.632 72.037 ;
     RECT  58.896 71.749 58.92 72.277 ;
     RECT  58.896 72.277 59.256 72.323 ;
     RECT  29.28 69.541 30.504 72.325 ;
     RECT  31.968 69.205 31.992 72.325 ;
     RECT  4.896 70.981 4.92 72.419 ;
     RECT  12.528 70.549 13.512 72.419 ;
     RECT  50.88 68.917 51.312 72.421 ;
     RECT  27.696 70.451 27.72 72.517 ;
     RECT  29.28 72.325 31.992 72.563 ;
     RECT  61.536 71.123 62.664 72.659 ;
     RECT  27.696 72.517 27.912 72.661 ;
     RECT  27.504 72.661 27.912 72.707 ;
     RECT  2.4 70.069 3.144 72.803 ;
     RECT  47.904 71.893 47.928 72.851 ;
     RECT  40.08 72.037 40.92 72.949 ;
     RECT  29.28 72.563 29.712 72.995 ;
     RECT  31.44 72.563 31.992 72.995 ;
     RECT  31.968 72.995 31.992 73.043 ;
     RECT  61.536 72.659 62.112 73.189 ;
     RECT  50.208 72.421 51.312 73.235 ;
     RECT  71.136 67.283 71.16 73.283 ;
     RECT  16.464 71.843 16.584 73.523 ;
     RECT  16.464 73.523 16.488 73.571 ;
     RECT  59.232 72.323 59.256 73.571 ;
     RECT  38.4 69.347 38.424 73.619 ;
     RECT  52.944 72.949 52.968 73.763 ;
     RECT  11.712 72.901 11.736 73.907 ;
     RECT  18.6 70.595 19.176 73.907 ;
     RECT  10.512 70.883 10.536 74.053 ;
     RECT  24 71.603 24.312 74.053 ;
     RECT  45.6 71.891 45.912 74.197 ;
     RECT  47.28 74.053 47.304 74.197 ;
     RECT  50.736 73.235 51.312 74.387 ;
     RECT  43.008 72.325 43.032 74.629 ;
     RECT  56.4 71.891 56.712 74.629 ;
     RECT  45.6 74.197 47.304 74.675 ;
     RECT  50.832 74.387 51.312 74.675 ;
     RECT  33.36 72.997 33.384 74.723 ;
     RECT  47.28 74.675 47.304 74.723 ;
     RECT  36.096 74.629 36.12 74.819 ;
     RECT  23.328 74.053 24.312 75.107 ;
     RECT  22.032 71.843 22.056 75.109 ;
     RECT  39.408 72.949 40.92 75.205 ;
     RECT  61.008 73.189 62.112 75.205 ;
     RECT  34.8 71.891 35.112 75.253 ;
     RECT  61.008 75.205 62.856 75.299 ;
     RECT  42.72 74.629 43.032 75.347 ;
     RECT  10.512 74.053 11.448 75.395 ;
     RECT  64.224 74.581 64.248 75.539 ;
     RECT  10.512 75.395 11.16 75.875 ;
     RECT  43.008 75.347 43.032 75.875 ;
     RECT  58.704 75.493 58.728 75.875 ;
     RECT  11.136 75.875 11.16 75.923 ;
     RECT  27.504 72.707 27.528 76.165 ;
     RECT  29.4 72.995 29.712 76.165 ;
     RECT  25.68 74.677 25.704 76.211 ;
     RECT  37.632 74.053 37.656 76.211 ;
     RECT  34.416 75.253 35.112 76.357 ;
     RECT  50.88 74.675 51.312 76.357 ;
     RECT  21.12 75.109 22.056 76.403 ;
     RECT  56.4 74.629 56.808 76.451 ;
     RECT  59.952 75.829 59.976 76.451 ;
     RECT  61.8 75.299 62.856 76.451 ;
     RECT  27.504 76.165 29.712 76.645 ;
     RECT  61.8 76.451 62.112 76.933 ;
     RECT  39.408 75.205 40.968 77.075 ;
     RECT  27.504 76.645 30.648 77.267 ;
     RECT  45.6 74.675 45.912 77.269 ;
     RECT  61.536 76.933 62.112 77.315 ;
     RECT  22.032 76.403 22.056 77.555 ;
     RECT  27.504 77.267 27.528 77.555 ;
     RECT  50.736 76.357 51.312 77.699 ;
     RECT  44.832 77.269 45.912 77.795 ;
     RECT  61.8 77.315 62.112 78.325 ;
     RECT  34.176 76.357 35.112 78.371 ;
     RECT  38.16 78.037 38.184 78.707 ;
     RECT  53.76 77.701 53.784 78.707 ;
     RECT  48.096 78.373 48.12 79.187 ;
     RECT  39.408 77.075 40.512 79.189 ;
     RECT  45.6 77.795 45.912 79.189 ;
     RECT  26.496 77.701 26.52 79.235 ;
     RECT  27.984 78.517 28.008 79.331 ;
     RECT  31.008 78.853 31.032 79.331 ;
     RECT  39.312 79.189 41.208 79.859 ;
     RECT  39.312 79.859 41.016 80.005 ;
     RECT  34.8 78.371 35.112 80.389 ;
     RECT  42.72 79.813 42.744 80.435 ;
     RECT  37.872 80.389 37.896 80.963 ;
     RECT  38.88 80.005 41.016 80.963 ;
     RECT  58.8 76.933 58.824 80.963 ;
     RECT  34.8 80.389 36.024 81.059 ;
     RECT  45.6 79.189 46.776 81.059 ;
     RECT  39.36 80.963 41.016 81.635 ;
     RECT  50.88 77.699 51.312 81.635 ;
     RECT  54.864 80.917 54.888 82.115 ;
     RECT  61.8 78.325 63 82.163 ;
     RECT  42.768 81.445 42.792 82.691 ;
     RECT  40.2 81.635 41.016 82.739 ;
     RECT  44.448 82.837 44.472 83.795 ;
     RECT  51 81.635 51.312 88.357 ;
     RECT  2.4 72.803 2.712 88.569 ;
     RECT  7.8 67.667 8.112 88.569 ;
     RECT  13.2 72.419 13.512 88.569 ;
     RECT  18.6 73.907 18.912 88.569 ;
     RECT  24 75.107 24.312 88.569 ;
     RECT  29.4 77.267 29.712 88.569 ;
     RECT  34.8 81.059 35.112 88.569 ;
     RECT  40.2 82.739 40.512 88.569 ;
     RECT  45.6 81.059 45.912 88.569 ;
     RECT  50.544 88.357 51.312 88.569 ;
     RECT  56.4 76.451 56.712 88.569 ;
     RECT  61.8 82.163 62.112 88.569 ;
     RECT  67.2 69.779 67.512 88.569 ;
     RECT  72.6 69.683 72.912 88.569 ;
     RECT  78 66.803 78.312 88.569 ;
     RECT  83.4 65.603 83.712 88.569 ;
     RECT  2.4 88.569 2.52 88.583 ;
     RECT  7.8 88.569 7.92 88.583 ;
     RECT  13.2 88.569 13.32 88.583 ;
     RECT  18.6 88.569 18.72 88.583 ;
     RECT  24 88.569 24.12 88.583 ;
     RECT  29.4 88.569 29.52 88.583 ;
     RECT  34.8 88.569 34.92 88.583 ;
     RECT  40.2 88.569 40.32 88.583 ;
     RECT  45.6 88.569 45.72 88.583 ;
     RECT  50.544 88.569 51.12 88.583 ;
     RECT  56.4 88.569 56.52 88.583 ;
     RECT  61.8 88.569 61.92 88.583 ;
     RECT  67.2 88.569 67.32 88.583 ;
     RECT  72.6 88.569 72.72 88.583 ;
     RECT  78 88.569 78.12 88.583 ;
     RECT  83.4 88.569 83.52 88.583 ;
  END
END ot_dsrom_window_column_halfwrite_distributed
END LIBRARY
